VERSION 5.8 ;
BUSBITCHARS "[]" ;
DIVIDERCHAR "/" ;
UNITS
    DATABASE MICRONS 1000 ;
END UNITS

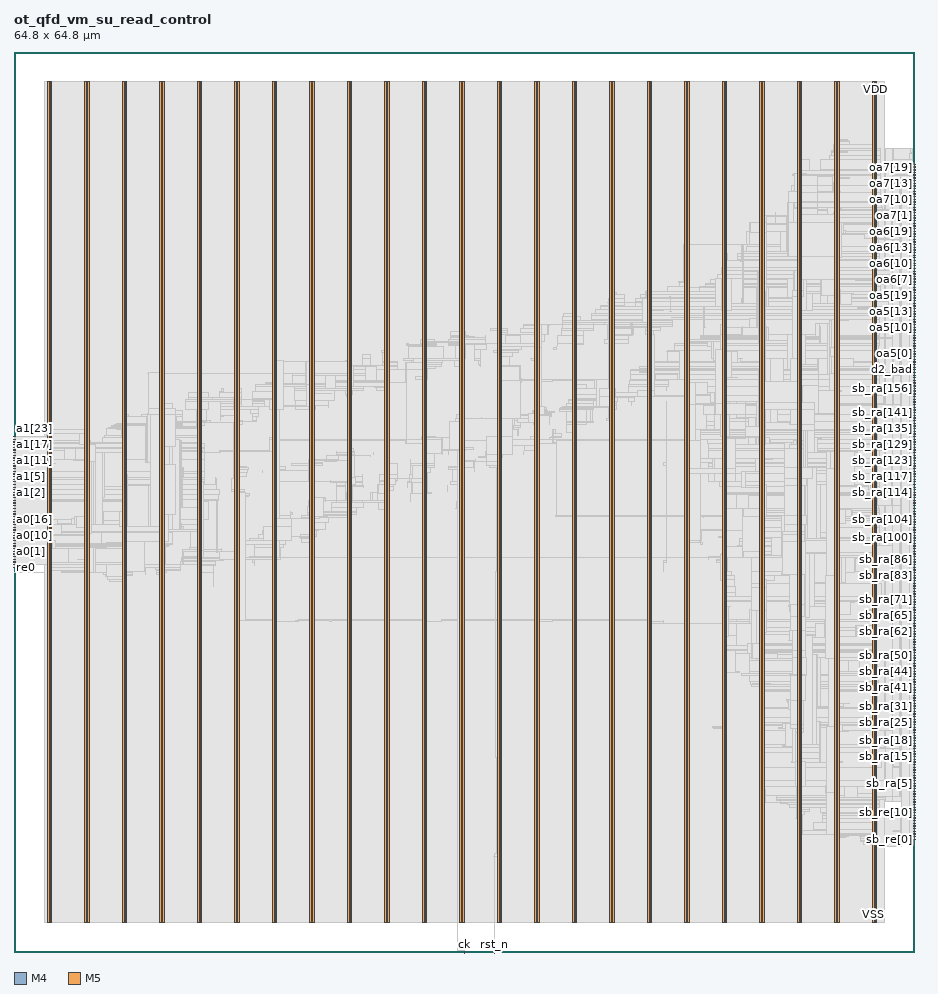
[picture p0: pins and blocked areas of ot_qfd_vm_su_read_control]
MACRO ot_qfd_vm_su_read_control
  FOREIGN ot_qfd_vm_su_read_control 0 0 ;
  CLASS BLOCK ;
  SIZE 64.8 BY 64.8 ;
  PIN a0[0]
    DIRECTION INPUT ;
    USE SIGNAL ;
    PORT
      LAYER M4 ;
        RECT  -0.072 28.08 0.072 28.104 ;
    END
  END a0[0]
  PIN a0[10]
    DIRECTION INPUT ;
    USE SIGNAL ;
    PORT
      LAYER M4 ;
        RECT  -0.072 30 0.072 30.024 ;
    END
  END a0[10]
  PIN a0[11]
    DIRECTION INPUT ;
    USE SIGNAL ;
    PORT
      LAYER M4 ;
        RECT  -0.072 30.192 0.072 30.216 ;
    END
  END a0[11]
  PIN a0[12]
    DIRECTION INPUT ;
    USE SIGNAL ;
    PORT
      LAYER M4 ;
        RECT  -0.072 30.384 0.072 30.408 ;
    END
  END a0[12]
  PIN a0[13]
    DIRECTION INPUT ;
    USE SIGNAL ;
    PORT
      LAYER M4 ;
        RECT  -0.072 30.576 0.072 30.6 ;
    END
  END a0[13]
  PIN a0[14]
    DIRECTION INPUT ;
    USE SIGNAL ;
    PORT
      LAYER M4 ;
        RECT  -0.072 30.768 0.072 30.792 ;
    END
  END a0[14]
  PIN a0[15]
    DIRECTION INPUT ;
    USE SIGNAL ;
    PORT
      LAYER M4 ;
        RECT  -0.072 30.96 0.072 30.984 ;
    END
  END a0[15]
  PIN a0[16]
    DIRECTION INPUT ;
    USE SIGNAL ;
    PORT
      LAYER M4 ;
        RECT  -0.072 31.152 0.072 31.176 ;
    END
  END a0[16]
  PIN a0[17]
    DIRECTION INPUT ;
    USE SIGNAL ;
    PORT
      LAYER M4 ;
        RECT  -0.072 31.344 0.072 31.368 ;
    END
  END a0[17]
  PIN a0[18]
    DIRECTION INPUT ;
    USE SIGNAL ;
    PORT
      LAYER M4 ;
        RECT  -0.072 31.536 0.072 31.56 ;
    END
  END a0[18]
  PIN a0[19]
    DIRECTION INPUT ;
    USE SIGNAL ;
    PORT
      LAYER M4 ;
        RECT  -0.072 31.728 0.072 31.752 ;
    END
  END a0[19]
  PIN a0[1]
    DIRECTION INPUT ;
    USE SIGNAL ;
    PORT
      LAYER M4 ;
        RECT  -0.072 28.272 0.072 28.296 ;
    END
  END a0[1]
  PIN a0[20]
    DIRECTION INPUT ;
    USE SIGNAL ;
    PORT
      LAYER M4 ;
        RECT  -0.072 31.92 0.072 31.944 ;
    END
  END a0[20]
  PIN a0[21]
    DIRECTION INPUT ;
    USE SIGNAL ;
    PORT
      LAYER M4 ;
        RECT  -0.072 32.112 0.072 32.136 ;
    END
  END a0[21]
  PIN a0[22]
    DIRECTION INPUT ;
    USE SIGNAL ;
    PORT
      LAYER M4 ;
        RECT  -0.072 32.304 0.072 32.328 ;
    END
  END a0[22]
  PIN a0[23]
    DIRECTION INPUT ;
    USE SIGNAL ;
    PORT
      LAYER M4 ;
        RECT  -0.072 32.496 0.072 32.52 ;
    END
  END a0[23]
  PIN a0[2]
    DIRECTION INPUT ;
    USE SIGNAL ;
    PORT
      LAYER M4 ;
        RECT  -0.072 28.464 0.072 28.488 ;
    END
  END a0[2]
  PIN a0[3]
    DIRECTION INPUT ;
    USE SIGNAL ;
    PORT
      LAYER M4 ;
        RECT  -0.072 28.656 0.072 28.68 ;
    END
  END a0[3]
  PIN a0[4]
    DIRECTION INPUT ;
    USE SIGNAL ;
    PORT
      LAYER M4 ;
        RECT  -0.072 28.848 0.072 28.872 ;
    END
  END a0[4]
  PIN a0[5]
    DIRECTION INPUT ;
    USE SIGNAL ;
    PORT
      LAYER M4 ;
        RECT  -0.072 29.04 0.072 29.064 ;
    END
  END a0[5]
  PIN a0[6]
    DIRECTION INPUT ;
    USE SIGNAL ;
    PORT
      LAYER M4 ;
        RECT  -0.072 29.232 0.072 29.256 ;
    END
  END a0[6]
  PIN a0[7]
    DIRECTION INPUT ;
    USE SIGNAL ;
    PORT
      LAYER M4 ;
        RECT  -0.072 29.424 0.072 29.448 ;
    END
  END a0[7]
  PIN a0[8]
    DIRECTION INPUT ;
    USE SIGNAL ;
    PORT
      LAYER M4 ;
        RECT  -0.072 29.616 0.072 29.64 ;
    END
  END a0[8]
  PIN a0[9]
    DIRECTION INPUT ;
    USE SIGNAL ;
    PORT
      LAYER M4 ;
        RECT  -0.072 29.808 0.072 29.832 ;
    END
  END a0[9]
  PIN a1[0]
    DIRECTION INPUT ;
    USE SIGNAL ;
    PORT
      LAYER M4 ;
        RECT  -0.072 32.688 0.072 32.712 ;
    END
  END a1[0]
  PIN a1[10]
    DIRECTION INPUT ;
    USE SIGNAL ;
    PORT
      LAYER M4 ;
        RECT  -0.072 34.608 0.072 34.632 ;
    END
  END a1[10]
  PIN a1[11]
    DIRECTION INPUT ;
    USE SIGNAL ;
    PORT
      LAYER M4 ;
        RECT  -0.072 34.8 0.072 34.824 ;
    END
  END a1[11]
  PIN a1[12]
    DIRECTION INPUT ;
    USE SIGNAL ;
    PORT
      LAYER M4 ;
        RECT  -0.072 34.992 0.072 35.016 ;
    END
  END a1[12]
  PIN a1[13]
    DIRECTION INPUT ;
    USE SIGNAL ;
    PORT
      LAYER M4 ;
        RECT  -0.072 35.184 0.072 35.208 ;
    END
  END a1[13]
  PIN a1[14]
    DIRECTION INPUT ;
    USE SIGNAL ;
    PORT
      LAYER M4 ;
        RECT  -0.072 35.376 0.072 35.4 ;
    END
  END a1[14]
  PIN a1[15]
    DIRECTION INPUT ;
    USE SIGNAL ;
    PORT
      LAYER M4 ;
        RECT  -0.072 35.568 0.072 35.592 ;
    END
  END a1[15]
  PIN a1[16]
    DIRECTION INPUT ;
    USE SIGNAL ;
    PORT
      LAYER M4 ;
        RECT  -0.072 35.76 0.072 35.784 ;
    END
  END a1[16]
  PIN a1[17]
    DIRECTION INPUT ;
    USE SIGNAL ;
    PORT
      LAYER M4 ;
        RECT  -0.072 35.952 0.072 35.976 ;
    END
  END a1[17]
  PIN a1[18]
    DIRECTION INPUT ;
    USE SIGNAL ;
    PORT
      LAYER M4 ;
        RECT  -0.072 36.144 0.072 36.168 ;
    END
  END a1[18]
  PIN a1[19]
    DIRECTION INPUT ;
    USE SIGNAL ;
    PORT
      LAYER M4 ;
        RECT  -0.072 36.336 0.072 36.36 ;
    END
  END a1[19]
  PIN a1[1]
    DIRECTION INPUT ;
    USE SIGNAL ;
    PORT
      LAYER M4 ;
        RECT  -0.072 32.88 0.072 32.904 ;
    END
  END a1[1]
  PIN a1[20]
    DIRECTION INPUT ;
    USE SIGNAL ;
    PORT
      LAYER M4 ;
        RECT  -0.072 36.528 0.072 36.552 ;
    END
  END a1[20]
  PIN a1[21]
    DIRECTION INPUT ;
    USE SIGNAL ;
    PORT
      LAYER M4 ;
        RECT  -0.072 36.72 0.072 36.744 ;
    END
  END a1[21]
  PIN a1[22]
    DIRECTION INPUT ;
    USE SIGNAL ;
    PORT
      LAYER M4 ;
        RECT  -0.072 36.912 0.072 36.936 ;
    END
  END a1[22]
  PIN a1[23]
    DIRECTION INPUT ;
    USE SIGNAL ;
    PORT
      LAYER M4 ;
        RECT  -0.072 37.104 0.072 37.128 ;
    END
  END a1[23]
  PIN a1[2]
    DIRECTION INPUT ;
    USE SIGNAL ;
    PORT
      LAYER M4 ;
        RECT  -0.072 33.072 0.072 33.096 ;
    END
  END a1[2]
  PIN a1[3]
    DIRECTION INPUT ;
    USE SIGNAL ;
    PORT
      LAYER M4 ;
        RECT  -0.072 33.264 0.072 33.288 ;
    END
  END a1[3]
  PIN a1[4]
    DIRECTION INPUT ;
    USE SIGNAL ;
    PORT
      LAYER M4 ;
        RECT  -0.072 33.456 0.072 33.48 ;
    END
  END a1[4]
  PIN a1[5]
    DIRECTION INPUT ;
    USE SIGNAL ;
    PORT
      LAYER M4 ;
        RECT  -0.072 33.648 0.072 33.672 ;
    END
  END a1[5]
  PIN a1[6]
    DIRECTION INPUT ;
    USE SIGNAL ;
    PORT
      LAYER M4 ;
        RECT  -0.072 33.84 0.072 33.864 ;
    END
  END a1[6]
  PIN a1[7]
    DIRECTION INPUT ;
    USE SIGNAL ;
    PORT
      LAYER M4 ;
        RECT  -0.072 34.032 0.072 34.056 ;
    END
  END a1[7]
  PIN a1[8]
    DIRECTION INPUT ;
    USE SIGNAL ;
    PORT
      LAYER M4 ;
        RECT  -0.072 34.224 0.072 34.248 ;
    END
  END a1[8]
  PIN a1[9]
    DIRECTION INPUT ;
    USE SIGNAL ;
    PORT
      LAYER M4 ;
        RECT  -0.072 34.416 0.072 34.44 ;
    END
  END a1[9]
  PIN ck
    DIRECTION INPUT ;
    USE SIGNAL ;
    PORT
      LAYER M5 ;
        RECT  32.4 -0.072 32.424 0.072 ;
    END
  END ck
  PIN d2_bad
    DIRECTION OUTPUT ;
    USE SIGNAL ;
    PORT
      LAYER M4 ;
        RECT  64.728 41.904 64.872 41.928 ;
    END
  END d2_bad
  PIN oa5[0]
    DIRECTION OUTPUT ;
    USE SIGNAL ;
    PORT
      LAYER M4 ;
        RECT  64.728 43.056 64.872 43.08 ;
    END
  END oa5[0]
  PIN oa5[10]
    DIRECTION OUTPUT ;
    USE SIGNAL ;
    PORT
      LAYER M4 ;
        RECT  64.728 44.976 64.872 45 ;
    END
  END oa5[10]
  PIN oa5[11]
    DIRECTION OUTPUT ;
    USE SIGNAL ;
    PORT
      LAYER M4 ;
        RECT  64.728 45.168 64.872 45.192 ;
    END
  END oa5[11]
  PIN oa5[12]
    DIRECTION OUTPUT ;
    USE SIGNAL ;
    PORT
      LAYER M4 ;
        RECT  64.728 45.36 64.872 45.384 ;
    END
  END oa5[12]
  PIN oa5[13]
    DIRECTION OUTPUT ;
    USE SIGNAL ;
    PORT
      LAYER M4 ;
        RECT  64.728 45.552 64.872 45.576 ;
    END
  END oa5[13]
  PIN oa5[14]
    DIRECTION OUTPUT ;
    USE SIGNAL ;
    PORT
      LAYER M4 ;
        RECT  64.728 45.744 64.872 45.768 ;
    END
  END oa5[14]
  PIN oa5[15]
    DIRECTION OUTPUT ;
    USE SIGNAL ;
    PORT
      LAYER M4 ;
        RECT  64.728 45.936 64.872 45.96 ;
    END
  END oa5[15]
  PIN oa5[16]
    DIRECTION OUTPUT ;
    USE SIGNAL ;
    PORT
      LAYER M4 ;
        RECT  64.728 46.128 64.872 46.152 ;
    END
  END oa5[16]
  PIN oa5[17]
    DIRECTION OUTPUT ;
    USE SIGNAL ;
    PORT
      LAYER M4 ;
        RECT  64.728 46.32 64.872 46.344 ;
    END
  END oa5[17]
  PIN oa5[18]
    DIRECTION OUTPUT ;
    USE SIGNAL ;
    PORT
      LAYER M4 ;
        RECT  64.728 46.512 64.872 46.536 ;
    END
  END oa5[18]
  PIN oa5[19]
    DIRECTION OUTPUT ;
    USE SIGNAL ;
    PORT
      LAYER M4 ;
        RECT  64.728 46.704 64.872 46.728 ;
    END
  END oa5[19]
  PIN oa5[1]
    DIRECTION OUTPUT ;
    USE SIGNAL ;
    PORT
      LAYER M4 ;
        RECT  64.728 43.248 64.872 43.272 ;
    END
  END oa5[1]
  PIN oa5[20]
    DIRECTION OUTPUT ;
    USE SIGNAL ;
    PORT
      LAYER M4 ;
        RECT  64.728 46.896 64.872 46.92 ;
    END
  END oa5[20]
  PIN oa5[21]
    DIRECTION OUTPUT ;
    USE SIGNAL ;
    PORT
      LAYER M4 ;
        RECT  64.728 47.088 64.872 47.112 ;
    END
  END oa5[21]
  PIN oa5[22]
    DIRECTION OUTPUT ;
    USE SIGNAL ;
    PORT
      LAYER M4 ;
        RECT  64.728 47.28 64.872 47.304 ;
    END
  END oa5[22]
  PIN oa5[23]
    DIRECTION OUTPUT ;
    USE SIGNAL ;
    PORT
      LAYER M4 ;
        RECT  64.728 47.472 64.872 47.496 ;
    END
  END oa5[23]
  PIN oa5[2]
    DIRECTION OUTPUT ;
    USE SIGNAL ;
    PORT
      LAYER M4 ;
        RECT  64.728 43.44 64.872 43.464 ;
    END
  END oa5[2]
  PIN oa5[3]
    DIRECTION OUTPUT ;
    USE SIGNAL ;
    PORT
      LAYER M4 ;
        RECT  64.728 43.632 64.872 43.656 ;
    END
  END oa5[3]
  PIN oa5[4]
    DIRECTION OUTPUT ;
    USE SIGNAL ;
    PORT
      LAYER M4 ;
        RECT  64.728 43.824 64.872 43.848 ;
    END
  END oa5[4]
  PIN oa5[5]
    DIRECTION OUTPUT ;
    USE SIGNAL ;
    PORT
      LAYER M4 ;
        RECT  64.728 44.016 64.872 44.04 ;
    END
  END oa5[5]
  PIN oa5[6]
    DIRECTION OUTPUT ;
    USE SIGNAL ;
    PORT
      LAYER M4 ;
        RECT  64.728 44.208 64.872 44.232 ;
    END
  END oa5[6]
  PIN oa5[7]
    DIRECTION OUTPUT ;
    USE SIGNAL ;
    PORT
      LAYER M4 ;
        RECT  64.728 44.4 64.872 44.424 ;
    END
  END oa5[7]
  PIN oa5[8]
    DIRECTION OUTPUT ;
    USE SIGNAL ;
    PORT
      LAYER M4 ;
        RECT  64.728 44.592 64.872 44.616 ;
    END
  END oa5[8]
  PIN oa5[9]
    DIRECTION OUTPUT ;
    USE SIGNAL ;
    PORT
      LAYER M4 ;
        RECT  64.728 44.784 64.872 44.808 ;
    END
  END oa5[9]
  PIN oa6[0]
    DIRECTION OUTPUT ;
    USE SIGNAL ;
    PORT
      LAYER M4 ;
        RECT  64.728 47.664 64.872 47.688 ;
    END
  END oa6[0]
  PIN oa6[10]
    DIRECTION OUTPUT ;
    USE SIGNAL ;
    PORT
      LAYER M4 ;
        RECT  64.728 49.584 64.872 49.608 ;
    END
  END oa6[10]
  PIN oa6[11]
    DIRECTION OUTPUT ;
    USE SIGNAL ;
    PORT
      LAYER M4 ;
        RECT  64.728 49.776 64.872 49.8 ;
    END
  END oa6[11]
  PIN oa6[12]
    DIRECTION OUTPUT ;
    USE SIGNAL ;
    PORT
      LAYER M4 ;
        RECT  64.728 49.968 64.872 49.992 ;
    END
  END oa6[12]
  PIN oa6[13]
    DIRECTION OUTPUT ;
    USE SIGNAL ;
    PORT
      LAYER M4 ;
        RECT  64.728 50.16 64.872 50.184 ;
    END
  END oa6[13]
  PIN oa6[14]
    DIRECTION OUTPUT ;
    USE SIGNAL ;
    PORT
      LAYER M4 ;
        RECT  64.728 50.352 64.872 50.376 ;
    END
  END oa6[14]
  PIN oa6[15]
    DIRECTION OUTPUT ;
    USE SIGNAL ;
    PORT
      LAYER M4 ;
        RECT  64.728 50.544 64.872 50.568 ;
    END
  END oa6[15]
  PIN oa6[16]
    DIRECTION OUTPUT ;
    USE SIGNAL ;
    PORT
      LAYER M4 ;
        RECT  64.728 50.736 64.872 50.76 ;
    END
  END oa6[16]
  PIN oa6[17]
    DIRECTION OUTPUT ;
    USE SIGNAL ;
    PORT
      LAYER M4 ;
        RECT  64.728 50.928 64.872 50.952 ;
    END
  END oa6[17]
  PIN oa6[18]
    DIRECTION OUTPUT ;
    USE SIGNAL ;
    PORT
      LAYER M4 ;
        RECT  64.728 51.12 64.872 51.144 ;
    END
  END oa6[18]
  PIN oa6[19]
    DIRECTION OUTPUT ;
    USE SIGNAL ;
    PORT
      LAYER M4 ;
        RECT  64.728 51.312 64.872 51.336 ;
    END
  END oa6[19]
  PIN oa6[1]
    DIRECTION OUTPUT ;
    USE SIGNAL ;
    PORT
      LAYER M4 ;
        RECT  64.728 47.856 64.872 47.88 ;
    END
  END oa6[1]
  PIN oa6[20]
    DIRECTION OUTPUT ;
    USE SIGNAL ;
    PORT
      LAYER M4 ;
        RECT  64.728 51.504 64.872 51.528 ;
    END
  END oa6[20]
  PIN oa6[21]
    DIRECTION OUTPUT ;
    USE SIGNAL ;
    PORT
      LAYER M4 ;
        RECT  64.728 51.696 64.872 51.72 ;
    END
  END oa6[21]
  PIN oa6[22]
    DIRECTION OUTPUT ;
    USE SIGNAL ;
    PORT
      LAYER M4 ;
        RECT  64.728 51.888 64.872 51.912 ;
    END
  END oa6[22]
  PIN oa6[23]
    DIRECTION OUTPUT ;
    USE SIGNAL ;
    PORT
      LAYER M4 ;
        RECT  64.728 52.08 64.872 52.104 ;
    END
  END oa6[23]
  PIN oa6[2]
    DIRECTION OUTPUT ;
    USE SIGNAL ;
    PORT
      LAYER M4 ;
        RECT  64.728 48.048 64.872 48.072 ;
    END
  END oa6[2]
  PIN oa6[3]
    DIRECTION OUTPUT ;
    USE SIGNAL ;
    PORT
      LAYER M4 ;
        RECT  64.728 48.24 64.872 48.264 ;
    END
  END oa6[3]
  PIN oa6[4]
    DIRECTION OUTPUT ;
    USE SIGNAL ;
    PORT
      LAYER M4 ;
        RECT  64.728 48.432 64.872 48.456 ;
    END
  END oa6[4]
  PIN oa6[5]
    DIRECTION OUTPUT ;
    USE SIGNAL ;
    PORT
      LAYER M4 ;
        RECT  64.728 48.624 64.872 48.648 ;
    END
  END oa6[5]
  PIN oa6[6]
    DIRECTION OUTPUT ;
    USE SIGNAL ;
    PORT
      LAYER M4 ;
        RECT  64.728 48.816 64.872 48.84 ;
    END
  END oa6[6]
  PIN oa6[7]
    DIRECTION OUTPUT ;
    USE SIGNAL ;
    PORT
      LAYER M4 ;
        RECT  64.728 49.008 64.872 49.032 ;
    END
  END oa6[7]
  PIN oa6[8]
    DIRECTION OUTPUT ;
    USE SIGNAL ;
    PORT
      LAYER M4 ;
        RECT  64.728 49.2 64.872 49.224 ;
    END
  END oa6[8]
  PIN oa6[9]
    DIRECTION OUTPUT ;
    USE SIGNAL ;
    PORT
      LAYER M4 ;
        RECT  64.728 49.392 64.872 49.416 ;
    END
  END oa6[9]
  PIN oa7[0]
    DIRECTION OUTPUT ;
    USE SIGNAL ;
    PORT
      LAYER M4 ;
        RECT  64.728 52.272 64.872 52.296 ;
    END
  END oa7[0]
  PIN oa7[10]
    DIRECTION OUTPUT ;
    USE SIGNAL ;
    PORT
      LAYER M4 ;
        RECT  64.728 54.192 64.872 54.216 ;
    END
  END oa7[10]
  PIN oa7[11]
    DIRECTION OUTPUT ;
    USE SIGNAL ;
    PORT
      LAYER M4 ;
        RECT  64.728 54.384 64.872 54.408 ;
    END
  END oa7[11]
  PIN oa7[12]
    DIRECTION OUTPUT ;
    USE SIGNAL ;
    PORT
      LAYER M4 ;
        RECT  64.728 54.576 64.872 54.6 ;
    END
  END oa7[12]
  PIN oa7[13]
    DIRECTION OUTPUT ;
    USE SIGNAL ;
    PORT
      LAYER M4 ;
        RECT  64.728 54.768 64.872 54.792 ;
    END
  END oa7[13]
  PIN oa7[14]
    DIRECTION OUTPUT ;
    USE SIGNAL ;
    PORT
      LAYER M4 ;
        RECT  64.728 54.96 64.872 54.984 ;
    END
  END oa7[14]
  PIN oa7[15]
    DIRECTION OUTPUT ;
    USE SIGNAL ;
    PORT
      LAYER M4 ;
        RECT  64.728 55.152 64.872 55.176 ;
    END
  END oa7[15]
  PIN oa7[16]
    DIRECTION OUTPUT ;
    USE SIGNAL ;
    PORT
      LAYER M4 ;
        RECT  64.728 55.344 64.872 55.368 ;
    END
  END oa7[16]
  PIN oa7[17]
    DIRECTION OUTPUT ;
    USE SIGNAL ;
    PORT
      LAYER M4 ;
        RECT  64.728 55.536 64.872 55.56 ;
    END
  END oa7[17]
  PIN oa7[18]
    DIRECTION OUTPUT ;
    USE SIGNAL ;
    PORT
      LAYER M4 ;
        RECT  64.728 55.728 64.872 55.752 ;
    END
  END oa7[18]
  PIN oa7[19]
    DIRECTION OUTPUT ;
    USE SIGNAL ;
    PORT
      LAYER M4 ;
        RECT  64.728 55.92 64.872 55.944 ;
    END
  END oa7[19]
  PIN oa7[1]
    DIRECTION OUTPUT ;
    USE SIGNAL ;
    PORT
      LAYER M4 ;
        RECT  64.728 52.464 64.872 52.488 ;
    END
  END oa7[1]
  PIN oa7[20]
    DIRECTION OUTPUT ;
    USE SIGNAL ;
    PORT
      LAYER M4 ;
        RECT  64.728 56.112 64.872 56.136 ;
    END
  END oa7[20]
  PIN oa7[21]
    DIRECTION OUTPUT ;
    USE SIGNAL ;
    PORT
      LAYER M4 ;
        RECT  64.728 56.304 64.872 56.328 ;
    END
  END oa7[21]
  PIN oa7[22]
    DIRECTION OUTPUT ;
    USE SIGNAL ;
    PORT
      LAYER M4 ;
        RECT  64.728 56.496 64.872 56.52 ;
    END
  END oa7[22]
  PIN oa7[23]
    DIRECTION OUTPUT ;
    USE SIGNAL ;
    PORT
      LAYER M4 ;
        RECT  64.728 56.688 64.872 56.712 ;
    END
  END oa7[23]
  PIN oa7[2]
    DIRECTION OUTPUT ;
    USE SIGNAL ;
    PORT
      LAYER M4 ;
        RECT  64.728 52.656 64.872 52.68 ;
    END
  END oa7[2]
  PIN oa7[3]
    DIRECTION OUTPUT ;
    USE SIGNAL ;
    PORT
      LAYER M4 ;
        RECT  64.728 52.848 64.872 52.872 ;
    END
  END oa7[3]
  PIN oa7[4]
    DIRECTION OUTPUT ;
    USE SIGNAL ;
    PORT
      LAYER M4 ;
        RECT  64.728 53.04 64.872 53.064 ;
    END
  END oa7[4]
  PIN oa7[5]
    DIRECTION OUTPUT ;
    USE SIGNAL ;
    PORT
      LAYER M4 ;
        RECT  64.728 53.232 64.872 53.256 ;
    END
  END oa7[5]
  PIN oa7[6]
    DIRECTION OUTPUT ;
    USE SIGNAL ;
    PORT
      LAYER M4 ;
        RECT  64.728 53.424 64.872 53.448 ;
    END
  END oa7[6]
  PIN oa7[7]
    DIRECTION OUTPUT ;
    USE SIGNAL ;
    PORT
      LAYER M4 ;
        RECT  64.728 53.616 64.872 53.64 ;
    END
  END oa7[7]
  PIN oa7[8]
    DIRECTION OUTPUT ;
    USE SIGNAL ;
    PORT
      LAYER M4 ;
        RECT  64.728 53.808 64.872 53.832 ;
    END
  END oa7[8]
  PIN oa7[9]
    DIRECTION OUTPUT ;
    USE SIGNAL ;
    PORT
      LAYER M4 ;
        RECT  64.728 54 64.872 54.024 ;
    END
  END oa7[9]
  PIN osi7
    DIRECTION OUTPUT ;
    USE SIGNAL ;
    PORT
      LAYER M4 ;
        RECT  64.728 42.864 64.872 42.888 ;
    END
  END osi7
  PIN ov3
    DIRECTION OUTPUT ;
    USE SIGNAL ;
    PORT
      LAYER M4 ;
        RECT  64.728 42.096 64.872 42.12 ;
    END
  END ov3
  PIN ov5
    DIRECTION OUTPUT ;
    USE SIGNAL ;
    PORT
      LAYER M4 ;
        RECT  64.728 42.288 64.872 42.312 ;
    END
  END ov5
  PIN ov6
    DIRECTION OUTPUT ;
    USE SIGNAL ;
    PORT
      LAYER M4 ;
        RECT  64.728 42.48 64.872 42.504 ;
    END
  END ov6
  PIN ov7
    DIRECTION OUTPUT ;
    USE SIGNAL ;
    PORT
      LAYER M4 ;
        RECT  64.728 42.672 64.872 42.696 ;
    END
  END ov7
  PIN re0
    DIRECTION INPUT ;
    USE SIGNAL ;
    PORT
      LAYER M4 ;
        RECT  -0.072 27.696 0.072 27.72 ;
    END
  END re0
  PIN re1
    DIRECTION INPUT ;
    USE SIGNAL ;
    PORT
      LAYER M4 ;
        RECT  -0.072 27.888 0.072 27.912 ;
    END
  END re1
  PIN rst_n
    DIRECTION INPUT ;
    USE SIGNAL ;
    PORT
      LAYER M5 ;
        RECT  34.56 -0.072 34.584 0.072 ;
    END
  END rst_n
  PIN sb_ra[0]
    DIRECTION OUTPUT ;
    USE SIGNAL ;
    PORT
      LAYER M4 ;
        RECT  64.728 11.184 64.872 11.208 ;
    END
  END sb_ra[0]
  PIN sb_ra[100]
    DIRECTION OUTPUT ;
    USE SIGNAL ;
    PORT
      LAYER M4 ;
        RECT  64.728 30.384 64.872 30.408 ;
    END
  END sb_ra[100]
  PIN sb_ra[101]
    DIRECTION OUTPUT ;
    USE SIGNAL ;
    PORT
      LAYER M4 ;
        RECT  64.728 30.576 64.872 30.6 ;
    END
  END sb_ra[101]
  PIN sb_ra[102]
    DIRECTION OUTPUT ;
    USE SIGNAL ;
    PORT
      LAYER M4 ;
        RECT  64.728 30.768 64.872 30.792 ;
    END
  END sb_ra[102]
  PIN sb_ra[103]
    DIRECTION OUTPUT ;
    USE SIGNAL ;
    PORT
      LAYER M4 ;
        RECT  64.728 30.96 64.872 30.984 ;
    END
  END sb_ra[103]
  PIN sb_ra[104]
    DIRECTION OUTPUT ;
    USE SIGNAL ;
    PORT
      LAYER M4 ;
        RECT  64.728 31.152 64.872 31.176 ;
    END
  END sb_ra[104]
  PIN sb_ra[105]
    DIRECTION OUTPUT ;
    USE SIGNAL ;
    PORT
      LAYER M4 ;
        RECT  64.728 31.344 64.872 31.368 ;
    END
  END sb_ra[105]
  PIN sb_ra[106]
    DIRECTION OUTPUT ;
    USE SIGNAL ;
    PORT
      LAYER M4 ;
        RECT  64.728 31.536 64.872 31.56 ;
    END
  END sb_ra[106]
  PIN sb_ra[107]
    DIRECTION OUTPUT ;
    USE SIGNAL ;
    PORT
      LAYER M4 ;
        RECT  64.728 31.728 64.872 31.752 ;
    END
  END sb_ra[107]
  PIN sb_ra[108]
    DIRECTION OUTPUT ;
    USE SIGNAL ;
    PORT
      LAYER M4 ;
        RECT  64.728 31.92 64.872 31.944 ;
    END
  END sb_ra[108]
  PIN sb_ra[109]
    DIRECTION OUTPUT ;
    USE SIGNAL ;
    PORT
      LAYER M4 ;
        RECT  64.728 32.112 64.872 32.136 ;
    END
  END sb_ra[109]
  PIN sb_ra[10]
    DIRECTION OUTPUT ;
    USE SIGNAL ;
    PORT
      LAYER M4 ;
        RECT  64.728 13.104 64.872 13.128 ;
    END
  END sb_ra[10]
  PIN sb_ra[110]
    DIRECTION OUTPUT ;
    USE SIGNAL ;
    PORT
      LAYER M4 ;
        RECT  64.728 32.304 64.872 32.328 ;
    END
  END sb_ra[110]
  PIN sb_ra[111]
    DIRECTION OUTPUT ;
    USE SIGNAL ;
    PORT
      LAYER M4 ;
        RECT  64.728 32.496 64.872 32.52 ;
    END
  END sb_ra[111]
  PIN sb_ra[112]
    DIRECTION OUTPUT ;
    USE SIGNAL ;
    PORT
      LAYER M4 ;
        RECT  64.728 32.688 64.872 32.712 ;
    END
  END sb_ra[112]
  PIN sb_ra[113]
    DIRECTION OUTPUT ;
    USE SIGNAL ;
    PORT
      LAYER M4 ;
        RECT  64.728 32.88 64.872 32.904 ;
    END
  END sb_ra[113]
  PIN sb_ra[114]
    DIRECTION OUTPUT ;
    USE SIGNAL ;
    PORT
      LAYER M4 ;
        RECT  64.728 33.072 64.872 33.096 ;
    END
  END sb_ra[114]
  PIN sb_ra[115]
    DIRECTION OUTPUT ;
    USE SIGNAL ;
    PORT
      LAYER M4 ;
        RECT  64.728 33.264 64.872 33.288 ;
    END
  END sb_ra[115]
  PIN sb_ra[116]
    DIRECTION OUTPUT ;
    USE SIGNAL ;
    PORT
      LAYER M4 ;
        RECT  64.728 33.456 64.872 33.48 ;
    END
  END sb_ra[116]
  PIN sb_ra[117]
    DIRECTION OUTPUT ;
    USE SIGNAL ;
    PORT
      LAYER M4 ;
        RECT  64.728 33.648 64.872 33.672 ;
    END
  END sb_ra[117]
  PIN sb_ra[118]
    DIRECTION OUTPUT ;
    USE SIGNAL ;
    PORT
      LAYER M4 ;
        RECT  64.728 33.84 64.872 33.864 ;
    END
  END sb_ra[118]
  PIN sb_ra[119]
    DIRECTION OUTPUT ;
    USE SIGNAL ;
    PORT
      LAYER M4 ;
        RECT  64.728 34.032 64.872 34.056 ;
    END
  END sb_ra[119]
  PIN sb_ra[11]
    DIRECTION OUTPUT ;
    USE SIGNAL ;
    PORT
      LAYER M4 ;
        RECT  64.728 13.296 64.872 13.32 ;
    END
  END sb_ra[11]
  PIN sb_ra[120]
    DIRECTION OUTPUT ;
    USE SIGNAL ;
    PORT
      LAYER M4 ;
        RECT  64.728 34.224 64.872 34.248 ;
    END
  END sb_ra[120]
  PIN sb_ra[121]
    DIRECTION OUTPUT ;
    USE SIGNAL ;
    PORT
      LAYER M4 ;
        RECT  64.728 34.416 64.872 34.44 ;
    END
  END sb_ra[121]
  PIN sb_ra[122]
    DIRECTION OUTPUT ;
    USE SIGNAL ;
    PORT
      LAYER M4 ;
        RECT  64.728 34.608 64.872 34.632 ;
    END
  END sb_ra[122]
  PIN sb_ra[123]
    DIRECTION OUTPUT ;
    USE SIGNAL ;
    PORT
      LAYER M4 ;
        RECT  64.728 34.8 64.872 34.824 ;
    END
  END sb_ra[123]
  PIN sb_ra[124]
    DIRECTION OUTPUT ;
    USE SIGNAL ;
    PORT
      LAYER M4 ;
        RECT  64.728 34.992 64.872 35.016 ;
    END
  END sb_ra[124]
  PIN sb_ra[125]
    DIRECTION OUTPUT ;
    USE SIGNAL ;
    PORT
      LAYER M4 ;
        RECT  64.728 35.184 64.872 35.208 ;
    END
  END sb_ra[125]
  PIN sb_ra[126]
    DIRECTION OUTPUT ;
    USE SIGNAL ;
    PORT
      LAYER M4 ;
        RECT  64.728 35.376 64.872 35.4 ;
    END
  END sb_ra[126]
  PIN sb_ra[127]
    DIRECTION OUTPUT ;
    USE SIGNAL ;
    PORT
      LAYER M4 ;
        RECT  64.728 35.568 64.872 35.592 ;
    END
  END sb_ra[127]
  PIN sb_ra[128]
    DIRECTION OUTPUT ;
    USE SIGNAL ;
    PORT
      LAYER M4 ;
        RECT  64.728 35.76 64.872 35.784 ;
    END
  END sb_ra[128]
  PIN sb_ra[129]
    DIRECTION OUTPUT ;
    USE SIGNAL ;
    PORT
      LAYER M4 ;
        RECT  64.728 35.952 64.872 35.976 ;
    END
  END sb_ra[129]
  PIN sb_ra[12]
    DIRECTION OUTPUT ;
    USE SIGNAL ;
    PORT
      LAYER M4 ;
        RECT  64.728 13.488 64.872 13.512 ;
    END
  END sb_ra[12]
  PIN sb_ra[130]
    DIRECTION OUTPUT ;
    USE SIGNAL ;
    PORT
      LAYER M4 ;
        RECT  64.728 36.144 64.872 36.168 ;
    END
  END sb_ra[130]
  PIN sb_ra[131]
    DIRECTION OUTPUT ;
    USE SIGNAL ;
    PORT
      LAYER M4 ;
        RECT  64.728 36.336 64.872 36.36 ;
    END
  END sb_ra[131]
  PIN sb_ra[132]
    DIRECTION OUTPUT ;
    USE SIGNAL ;
    PORT
      LAYER M4 ;
        RECT  64.728 36.528 64.872 36.552 ;
    END
  END sb_ra[132]
  PIN sb_ra[133]
    DIRECTION OUTPUT ;
    USE SIGNAL ;
    PORT
      LAYER M4 ;
        RECT  64.728 36.72 64.872 36.744 ;
    END
  END sb_ra[133]
  PIN sb_ra[134]
    DIRECTION OUTPUT ;
    USE SIGNAL ;
    PORT
      LAYER M4 ;
        RECT  64.728 36.912 64.872 36.936 ;
    END
  END sb_ra[134]
  PIN sb_ra[135]
    DIRECTION OUTPUT ;
    USE SIGNAL ;
    PORT
      LAYER M4 ;
        RECT  64.728 37.104 64.872 37.128 ;
    END
  END sb_ra[135]
  PIN sb_ra[136]
    DIRECTION OUTPUT ;
    USE SIGNAL ;
    PORT
      LAYER M4 ;
        RECT  64.728 37.296 64.872 37.32 ;
    END
  END sb_ra[136]
  PIN sb_ra[137]
    DIRECTION OUTPUT ;
    USE SIGNAL ;
    PORT
      LAYER M4 ;
        RECT  64.728 37.488 64.872 37.512 ;
    END
  END sb_ra[137]
  PIN sb_ra[138]
    DIRECTION OUTPUT ;
    USE SIGNAL ;
    PORT
      LAYER M4 ;
        RECT  64.728 37.68 64.872 37.704 ;
    END
  END sb_ra[138]
  PIN sb_ra[139]
    DIRECTION OUTPUT ;
    USE SIGNAL ;
    PORT
      LAYER M4 ;
        RECT  64.728 37.872 64.872 37.896 ;
    END
  END sb_ra[139]
  PIN sb_ra[13]
    DIRECTION OUTPUT ;
    USE SIGNAL ;
    PORT
      LAYER M4 ;
        RECT  64.728 13.68 64.872 13.704 ;
    END
  END sb_ra[13]
  PIN sb_ra[140]
    DIRECTION OUTPUT ;
    USE SIGNAL ;
    PORT
      LAYER M4 ;
        RECT  64.728 38.064 64.872 38.088 ;
    END
  END sb_ra[140]
  PIN sb_ra[141]
    DIRECTION OUTPUT ;
    USE SIGNAL ;
    PORT
      LAYER M4 ;
        RECT  64.728 38.256 64.872 38.28 ;
    END
  END sb_ra[141]
  PIN sb_ra[142]
    DIRECTION OUTPUT ;
    USE SIGNAL ;
    PORT
      LAYER M4 ;
        RECT  64.728 38.448 64.872 38.472 ;
    END
  END sb_ra[142]
  PIN sb_ra[143]
    DIRECTION OUTPUT ;
    USE SIGNAL ;
    PORT
      LAYER M4 ;
        RECT  64.728 38.64 64.872 38.664 ;
    END
  END sb_ra[143]
  PIN sb_ra[144]
    DIRECTION OUTPUT ;
    USE SIGNAL ;
    PORT
      LAYER M4 ;
        RECT  64.728 38.832 64.872 38.856 ;
    END
  END sb_ra[144]
  PIN sb_ra[145]
    DIRECTION OUTPUT ;
    USE SIGNAL ;
    PORT
      LAYER M4 ;
        RECT  64.728 39.024 64.872 39.048 ;
    END
  END sb_ra[145]
  PIN sb_ra[146]
    DIRECTION OUTPUT ;
    USE SIGNAL ;
    PORT
      LAYER M4 ;
        RECT  64.728 39.216 64.872 39.24 ;
    END
  END sb_ra[146]
  PIN sb_ra[147]
    DIRECTION OUTPUT ;
    USE SIGNAL ;
    PORT
      LAYER M4 ;
        RECT  64.728 39.408 64.872 39.432 ;
    END
  END sb_ra[147]
  PIN sb_ra[148]
    DIRECTION OUTPUT ;
    USE SIGNAL ;
    PORT
      LAYER M4 ;
        RECT  64.728 39.6 64.872 39.624 ;
    END
  END sb_ra[148]
  PIN sb_ra[149]
    DIRECTION OUTPUT ;
    USE SIGNAL ;
    PORT
      LAYER M4 ;
        RECT  64.728 39.792 64.872 39.816 ;
    END
  END sb_ra[149]
  PIN sb_ra[14]
    DIRECTION OUTPUT ;
    USE SIGNAL ;
    PORT
      LAYER M4 ;
        RECT  64.728 13.872 64.872 13.896 ;
    END
  END sb_ra[14]
  PIN sb_ra[150]
    DIRECTION OUTPUT ;
    USE SIGNAL ;
    PORT
      LAYER M4 ;
        RECT  64.728 39.984 64.872 40.008 ;
    END
  END sb_ra[150]
  PIN sb_ra[151]
    DIRECTION OUTPUT ;
    USE SIGNAL ;
    PORT
      LAYER M4 ;
        RECT  64.728 40.176 64.872 40.2 ;
    END
  END sb_ra[151]
  PIN sb_ra[152]
    DIRECTION OUTPUT ;
    USE SIGNAL ;
    PORT
      LAYER M4 ;
        RECT  64.728 40.368 64.872 40.392 ;
    END
  END sb_ra[152]
  PIN sb_ra[153]
    DIRECTION OUTPUT ;
    USE SIGNAL ;
    PORT
      LAYER M4 ;
        RECT  64.728 40.56 64.872 40.584 ;
    END
  END sb_ra[153]
  PIN sb_ra[154]
    DIRECTION OUTPUT ;
    USE SIGNAL ;
    PORT
      LAYER M4 ;
        RECT  64.728 40.752 64.872 40.776 ;
    END
  END sb_ra[154]
  PIN sb_ra[155]
    DIRECTION OUTPUT ;
    USE SIGNAL ;
    PORT
      LAYER M4 ;
        RECT  64.728 40.944 64.872 40.968 ;
    END
  END sb_ra[155]
  PIN sb_ra[156]
    DIRECTION OUTPUT ;
    USE SIGNAL ;
    PORT
      LAYER M4 ;
        RECT  64.728 41.136 64.872 41.16 ;
    END
  END sb_ra[156]
  PIN sb_ra[157]
    DIRECTION OUTPUT ;
    USE SIGNAL ;
    PORT
      LAYER M4 ;
        RECT  64.728 41.328 64.872 41.352 ;
    END
  END sb_ra[157]
  PIN sb_ra[158]
    DIRECTION OUTPUT ;
    USE SIGNAL ;
    PORT
      LAYER M4 ;
        RECT  64.728 41.52 64.872 41.544 ;
    END
  END sb_ra[158]
  PIN sb_ra[159]
    DIRECTION OUTPUT ;
    USE SIGNAL ;
    PORT
      LAYER M4 ;
        RECT  64.728 41.712 64.872 41.736 ;
    END
  END sb_ra[159]
  PIN sb_ra[15]
    DIRECTION OUTPUT ;
    USE SIGNAL ;
    PORT
      LAYER M4 ;
        RECT  64.728 14.064 64.872 14.088 ;
    END
  END sb_ra[15]
  PIN sb_ra[16]
    DIRECTION OUTPUT ;
    USE SIGNAL ;
    PORT
      LAYER M4 ;
        RECT  64.728 14.256 64.872 14.28 ;
    END
  END sb_ra[16]
  PIN sb_ra[17]
    DIRECTION OUTPUT ;
    USE SIGNAL ;
    PORT
      LAYER M4 ;
        RECT  64.728 14.448 64.872 14.472 ;
    END
  END sb_ra[17]
  PIN sb_ra[18]
    DIRECTION OUTPUT ;
    USE SIGNAL ;
    PORT
      LAYER M4 ;
        RECT  64.728 14.64 64.872 14.664 ;
    END
  END sb_ra[18]
  PIN sb_ra[19]
    DIRECTION OUTPUT ;
    USE SIGNAL ;
    PORT
      LAYER M4 ;
        RECT  64.728 14.832 64.872 14.856 ;
    END
  END sb_ra[19]
  PIN sb_ra[1]
    DIRECTION OUTPUT ;
    USE SIGNAL ;
    PORT
      LAYER M4 ;
        RECT  64.728 11.376 64.872 11.4 ;
    END
  END sb_ra[1]
  PIN sb_ra[20]
    DIRECTION OUTPUT ;
    USE SIGNAL ;
    PORT
      LAYER M4 ;
        RECT  64.728 15.024 64.872 15.048 ;
    END
  END sb_ra[20]
  PIN sb_ra[21]
    DIRECTION OUTPUT ;
    USE SIGNAL ;
    PORT
      LAYER M4 ;
        RECT  64.728 15.216 64.872 15.24 ;
    END
  END sb_ra[21]
  PIN sb_ra[22]
    DIRECTION OUTPUT ;
    USE SIGNAL ;
    PORT
      LAYER M4 ;
        RECT  64.728 15.408 64.872 15.432 ;
    END
  END sb_ra[22]
  PIN sb_ra[23]
    DIRECTION OUTPUT ;
    USE SIGNAL ;
    PORT
      LAYER M4 ;
        RECT  64.728 15.6 64.872 15.624 ;
    END
  END sb_ra[23]
  PIN sb_ra[24]
    DIRECTION OUTPUT ;
    USE SIGNAL ;
    PORT
      LAYER M4 ;
        RECT  64.728 15.792 64.872 15.816 ;
    END
  END sb_ra[24]
  PIN sb_ra[25]
    DIRECTION OUTPUT ;
    USE SIGNAL ;
    PORT
      LAYER M4 ;
        RECT  64.728 15.984 64.872 16.008 ;
    END
  END sb_ra[25]
  PIN sb_ra[26]
    DIRECTION OUTPUT ;
    USE SIGNAL ;
    PORT
      LAYER M4 ;
        RECT  64.728 16.176 64.872 16.2 ;
    END
  END sb_ra[26]
  PIN sb_ra[27]
    DIRECTION OUTPUT ;
    USE SIGNAL ;
    PORT
      LAYER M4 ;
        RECT  64.728 16.368 64.872 16.392 ;
    END
  END sb_ra[27]
  PIN sb_ra[28]
    DIRECTION OUTPUT ;
    USE SIGNAL ;
    PORT
      LAYER M4 ;
        RECT  64.728 16.56 64.872 16.584 ;
    END
  END sb_ra[28]
  PIN sb_ra[29]
    DIRECTION OUTPUT ;
    USE SIGNAL ;
    PORT
      LAYER M4 ;
        RECT  64.728 16.752 64.872 16.776 ;
    END
  END sb_ra[29]
  PIN sb_ra[2]
    DIRECTION OUTPUT ;
    USE SIGNAL ;
    PORT
      LAYER M4 ;
        RECT  64.728 11.568 64.872 11.592 ;
    END
  END sb_ra[2]
  PIN sb_ra[30]
    DIRECTION OUTPUT ;
    USE SIGNAL ;
    PORT
      LAYER M4 ;
        RECT  64.728 16.944 64.872 16.968 ;
    END
  END sb_ra[30]
  PIN sb_ra[31]
    DIRECTION OUTPUT ;
    USE SIGNAL ;
    PORT
      LAYER M4 ;
        RECT  64.728 17.136 64.872 17.16 ;
    END
  END sb_ra[31]
  PIN sb_ra[32]
    DIRECTION OUTPUT ;
    USE SIGNAL ;
    PORT
      LAYER M4 ;
        RECT  64.728 17.328 64.872 17.352 ;
    END
  END sb_ra[32]
  PIN sb_ra[33]
    DIRECTION OUTPUT ;
    USE SIGNAL ;
    PORT
      LAYER M4 ;
        RECT  64.728 17.52 64.872 17.544 ;
    END
  END sb_ra[33]
  PIN sb_ra[34]
    DIRECTION OUTPUT ;
    USE SIGNAL ;
    PORT
      LAYER M4 ;
        RECT  64.728 17.712 64.872 17.736 ;
    END
  END sb_ra[34]
  PIN sb_ra[35]
    DIRECTION OUTPUT ;
    USE SIGNAL ;
    PORT
      LAYER M4 ;
        RECT  64.728 17.904 64.872 17.928 ;
    END
  END sb_ra[35]
  PIN sb_ra[36]
    DIRECTION OUTPUT ;
    USE SIGNAL ;
    PORT
      LAYER M4 ;
        RECT  64.728 18.096 64.872 18.12 ;
    END
  END sb_ra[36]
  PIN sb_ra[37]
    DIRECTION OUTPUT ;
    USE SIGNAL ;
    PORT
      LAYER M4 ;
        RECT  64.728 18.288 64.872 18.312 ;
    END
  END sb_ra[37]
  PIN sb_ra[38]
    DIRECTION OUTPUT ;
    USE SIGNAL ;
    PORT
      LAYER M4 ;
        RECT  64.728 18.48 64.872 18.504 ;
    END
  END sb_ra[38]
  PIN sb_ra[39]
    DIRECTION OUTPUT ;
    USE SIGNAL ;
    PORT
      LAYER M4 ;
        RECT  64.728 18.672 64.872 18.696 ;
    END
  END sb_ra[39]
  PIN sb_ra[3]
    DIRECTION OUTPUT ;
    USE SIGNAL ;
    PORT
      LAYER M4 ;
        RECT  64.728 11.76 64.872 11.784 ;
    END
  END sb_ra[3]
  PIN sb_ra[40]
    DIRECTION OUTPUT ;
    USE SIGNAL ;
    PORT
      LAYER M4 ;
        RECT  64.728 18.864 64.872 18.888 ;
    END
  END sb_ra[40]
  PIN sb_ra[41]
    DIRECTION OUTPUT ;
    USE SIGNAL ;
    PORT
      LAYER M4 ;
        RECT  64.728 19.056 64.872 19.08 ;
    END
  END sb_ra[41]
  PIN sb_ra[42]
    DIRECTION OUTPUT ;
    USE SIGNAL ;
    PORT
      LAYER M4 ;
        RECT  64.728 19.248 64.872 19.272 ;
    END
  END sb_ra[42]
  PIN sb_ra[43]
    DIRECTION OUTPUT ;
    USE SIGNAL ;
    PORT
      LAYER M4 ;
        RECT  64.728 19.44 64.872 19.464 ;
    END
  END sb_ra[43]
  PIN sb_ra[44]
    DIRECTION OUTPUT ;
    USE SIGNAL ;
    PORT
      LAYER M4 ;
        RECT  64.728 19.632 64.872 19.656 ;
    END
  END sb_ra[44]
  PIN sb_ra[45]
    DIRECTION OUTPUT ;
    USE SIGNAL ;
    PORT
      LAYER M4 ;
        RECT  64.728 19.824 64.872 19.848 ;
    END
  END sb_ra[45]
  PIN sb_ra[46]
    DIRECTION OUTPUT ;
    USE SIGNAL ;
    PORT
      LAYER M4 ;
        RECT  64.728 20.016 64.872 20.04 ;
    END
  END sb_ra[46]
  PIN sb_ra[47]
    DIRECTION OUTPUT ;
    USE SIGNAL ;
    PORT
      LAYER M4 ;
        RECT  64.728 20.208 64.872 20.232 ;
    END
  END sb_ra[47]
  PIN sb_ra[48]
    DIRECTION OUTPUT ;
    USE SIGNAL ;
    PORT
      LAYER M4 ;
        RECT  64.728 20.4 64.872 20.424 ;
    END
  END sb_ra[48]
  PIN sb_ra[49]
    DIRECTION OUTPUT ;
    USE SIGNAL ;
    PORT
      LAYER M4 ;
        RECT  64.728 20.592 64.872 20.616 ;
    END
  END sb_ra[49]
  PIN sb_ra[4]
    DIRECTION OUTPUT ;
    USE SIGNAL ;
    PORT
      LAYER M4 ;
        RECT  64.728 11.952 64.872 11.976 ;
    END
  END sb_ra[4]
  PIN sb_ra[50]
    DIRECTION OUTPUT ;
    USE SIGNAL ;
    PORT
      LAYER M4 ;
        RECT  64.728 20.784 64.872 20.808 ;
    END
  END sb_ra[50]
  PIN sb_ra[51]
    DIRECTION OUTPUT ;
    USE SIGNAL ;
    PORT
      LAYER M4 ;
        RECT  64.728 20.976 64.872 21 ;
    END
  END sb_ra[51]
  PIN sb_ra[52]
    DIRECTION OUTPUT ;
    USE SIGNAL ;
    PORT
      LAYER M4 ;
        RECT  64.728 21.168 64.872 21.192 ;
    END
  END sb_ra[52]
  PIN sb_ra[53]
    DIRECTION OUTPUT ;
    USE SIGNAL ;
    PORT
      LAYER M4 ;
        RECT  64.728 21.36 64.872 21.384 ;
    END
  END sb_ra[53]
  PIN sb_ra[54]
    DIRECTION OUTPUT ;
    USE SIGNAL ;
    PORT
      LAYER M4 ;
        RECT  64.728 21.552 64.872 21.576 ;
    END
  END sb_ra[54]
  PIN sb_ra[55]
    DIRECTION OUTPUT ;
    USE SIGNAL ;
    PORT
      LAYER M4 ;
        RECT  64.728 21.744 64.872 21.768 ;
    END
  END sb_ra[55]
  PIN sb_ra[56]
    DIRECTION OUTPUT ;
    USE SIGNAL ;
    PORT
      LAYER M4 ;
        RECT  64.728 21.936 64.872 21.96 ;
    END
  END sb_ra[56]
  PIN sb_ra[57]
    DIRECTION OUTPUT ;
    USE SIGNAL ;
    PORT
      LAYER M4 ;
        RECT  64.728 22.128 64.872 22.152 ;
    END
  END sb_ra[57]
  PIN sb_ra[58]
    DIRECTION OUTPUT ;
    USE SIGNAL ;
    PORT
      LAYER M4 ;
        RECT  64.728 22.32 64.872 22.344 ;
    END
  END sb_ra[58]
  PIN sb_ra[59]
    DIRECTION OUTPUT ;
    USE SIGNAL ;
    PORT
      LAYER M4 ;
        RECT  64.728 22.512 64.872 22.536 ;
    END
  END sb_ra[59]
  PIN sb_ra[5]
    DIRECTION OUTPUT ;
    USE SIGNAL ;
    PORT
      LAYER M4 ;
        RECT  64.728 12.144 64.872 12.168 ;
    END
  END sb_ra[5]
  PIN sb_ra[60]
    DIRECTION OUTPUT ;
    USE SIGNAL ;
    PORT
      LAYER M4 ;
        RECT  64.728 22.704 64.872 22.728 ;
    END
  END sb_ra[60]
  PIN sb_ra[61]
    DIRECTION OUTPUT ;
    USE SIGNAL ;
    PORT
      LAYER M4 ;
        RECT  64.728 22.896 64.872 22.92 ;
    END
  END sb_ra[61]
  PIN sb_ra[62]
    DIRECTION OUTPUT ;
    USE SIGNAL ;
    PORT
      LAYER M4 ;
        RECT  64.728 23.088 64.872 23.112 ;
    END
  END sb_ra[62]
  PIN sb_ra[63]
    DIRECTION OUTPUT ;
    USE SIGNAL ;
    PORT
      LAYER M4 ;
        RECT  64.728 23.28 64.872 23.304 ;
    END
  END sb_ra[63]
  PIN sb_ra[64]
    DIRECTION OUTPUT ;
    USE SIGNAL ;
    PORT
      LAYER M4 ;
        RECT  64.728 23.472 64.872 23.496 ;
    END
  END sb_ra[64]
  PIN sb_ra[65]
    DIRECTION OUTPUT ;
    USE SIGNAL ;
    PORT
      LAYER M4 ;
        RECT  64.728 23.664 64.872 23.688 ;
    END
  END sb_ra[65]
  PIN sb_ra[66]
    DIRECTION OUTPUT ;
    USE SIGNAL ;
    PORT
      LAYER M4 ;
        RECT  64.728 23.856 64.872 23.88 ;
    END
  END sb_ra[66]
  PIN sb_ra[67]
    DIRECTION OUTPUT ;
    USE SIGNAL ;
    PORT
      LAYER M4 ;
        RECT  64.728 24.048 64.872 24.072 ;
    END
  END sb_ra[67]
  PIN sb_ra[68]
    DIRECTION OUTPUT ;
    USE SIGNAL ;
    PORT
      LAYER M4 ;
        RECT  64.728 24.24 64.872 24.264 ;
    END
  END sb_ra[68]
  PIN sb_ra[69]
    DIRECTION OUTPUT ;
    USE SIGNAL ;
    PORT
      LAYER M4 ;
        RECT  64.728 24.432 64.872 24.456 ;
    END
  END sb_ra[69]
  PIN sb_ra[6]
    DIRECTION OUTPUT ;
    USE SIGNAL ;
    PORT
      LAYER M4 ;
        RECT  64.728 12.336 64.872 12.36 ;
    END
  END sb_ra[6]
  PIN sb_ra[70]
    DIRECTION OUTPUT ;
    USE SIGNAL ;
    PORT
      LAYER M4 ;
        RECT  64.728 24.624 64.872 24.648 ;
    END
  END sb_ra[70]
  PIN sb_ra[71]
    DIRECTION OUTPUT ;
    USE SIGNAL ;
    PORT
      LAYER M4 ;
        RECT  64.728 24.816 64.872 24.84 ;
    END
  END sb_ra[71]
  PIN sb_ra[72]
    DIRECTION OUTPUT ;
    USE SIGNAL ;
    PORT
      LAYER M4 ;
        RECT  64.728 25.008 64.872 25.032 ;
    END
  END sb_ra[72]
  PIN sb_ra[73]
    DIRECTION OUTPUT ;
    USE SIGNAL ;
    PORT
      LAYER M4 ;
        RECT  64.728 25.2 64.872 25.224 ;
    END
  END sb_ra[73]
  PIN sb_ra[74]
    DIRECTION OUTPUT ;
    USE SIGNAL ;
    PORT
      LAYER M4 ;
        RECT  64.728 25.392 64.872 25.416 ;
    END
  END sb_ra[74]
  PIN sb_ra[75]
    DIRECTION OUTPUT ;
    USE SIGNAL ;
    PORT
      LAYER M4 ;
        RECT  64.728 25.584 64.872 25.608 ;
    END
  END sb_ra[75]
  PIN sb_ra[76]
    DIRECTION OUTPUT ;
    USE SIGNAL ;
    PORT
      LAYER M4 ;
        RECT  64.728 25.776 64.872 25.8 ;
    END
  END sb_ra[76]
  PIN sb_ra[77]
    DIRECTION OUTPUT ;
    USE SIGNAL ;
    PORT
      LAYER M4 ;
        RECT  64.728 25.968 64.872 25.992 ;
    END
  END sb_ra[77]
  PIN sb_ra[78]
    DIRECTION OUTPUT ;
    USE SIGNAL ;
    PORT
      LAYER M4 ;
        RECT  64.728 26.16 64.872 26.184 ;
    END
  END sb_ra[78]
  PIN sb_ra[79]
    DIRECTION OUTPUT ;
    USE SIGNAL ;
    PORT
      LAYER M4 ;
        RECT  64.728 26.352 64.872 26.376 ;
    END
  END sb_ra[79]
  PIN sb_ra[7]
    DIRECTION OUTPUT ;
    USE SIGNAL ;
    PORT
      LAYER M4 ;
        RECT  64.728 12.528 64.872 12.552 ;
    END
  END sb_ra[7]
  PIN sb_ra[80]
    DIRECTION OUTPUT ;
    USE SIGNAL ;
    PORT
      LAYER M4 ;
        RECT  64.728 26.544 64.872 26.568 ;
    END
  END sb_ra[80]
  PIN sb_ra[81]
    DIRECTION OUTPUT ;
    USE SIGNAL ;
    PORT
      LAYER M4 ;
        RECT  64.728 26.736 64.872 26.76 ;
    END
  END sb_ra[81]
  PIN sb_ra[82]
    DIRECTION OUTPUT ;
    USE SIGNAL ;
    PORT
      LAYER M4 ;
        RECT  64.728 26.928 64.872 26.952 ;
    END
  END sb_ra[82]
  PIN sb_ra[83]
    DIRECTION OUTPUT ;
    USE SIGNAL ;
    PORT
      LAYER M4 ;
        RECT  64.728 27.12 64.872 27.144 ;
    END
  END sb_ra[83]
  PIN sb_ra[84]
    DIRECTION OUTPUT ;
    USE SIGNAL ;
    PORT
      LAYER M4 ;
        RECT  64.728 27.312 64.872 27.336 ;
    END
  END sb_ra[84]
  PIN sb_ra[85]
    DIRECTION OUTPUT ;
    USE SIGNAL ;
    PORT
      LAYER M4 ;
        RECT  64.728 27.504 64.872 27.528 ;
    END
  END sb_ra[85]
  PIN sb_ra[86]
    DIRECTION OUTPUT ;
    USE SIGNAL ;
    PORT
      LAYER M4 ;
        RECT  64.728 27.696 64.872 27.72 ;
    END
  END sb_ra[86]
  PIN sb_ra[87]
    DIRECTION OUTPUT ;
    USE SIGNAL ;
    PORT
      LAYER M4 ;
        RECT  64.728 27.888 64.872 27.912 ;
    END
  END sb_ra[87]
  PIN sb_ra[88]
    DIRECTION OUTPUT ;
    USE SIGNAL ;
    PORT
      LAYER M4 ;
        RECT  64.728 28.08 64.872 28.104 ;
    END
  END sb_ra[88]
  PIN sb_ra[89]
    DIRECTION OUTPUT ;
    USE SIGNAL ;
    PORT
      LAYER M4 ;
        RECT  64.728 28.272 64.872 28.296 ;
    END
  END sb_ra[89]
  PIN sb_ra[8]
    DIRECTION OUTPUT ;
    USE SIGNAL ;
    PORT
      LAYER M4 ;
        RECT  64.728 12.72 64.872 12.744 ;
    END
  END sb_ra[8]
  PIN sb_ra[90]
    DIRECTION OUTPUT ;
    USE SIGNAL ;
    PORT
      LAYER M4 ;
        RECT  64.728 28.464 64.872 28.488 ;
    END
  END sb_ra[90]
  PIN sb_ra[91]
    DIRECTION OUTPUT ;
    USE SIGNAL ;
    PORT
      LAYER M4 ;
        RECT  64.728 28.656 64.872 28.68 ;
    END
  END sb_ra[91]
  PIN sb_ra[92]
    DIRECTION OUTPUT ;
    USE SIGNAL ;
    PORT
      LAYER M4 ;
        RECT  64.728 28.848 64.872 28.872 ;
    END
  END sb_ra[92]
  PIN sb_ra[93]
    DIRECTION OUTPUT ;
    USE SIGNAL ;
    PORT
      LAYER M4 ;
        RECT  64.728 29.04 64.872 29.064 ;
    END
  END sb_ra[93]
  PIN sb_ra[94]
    DIRECTION OUTPUT ;
    USE SIGNAL ;
    PORT
      LAYER M4 ;
        RECT  64.728 29.232 64.872 29.256 ;
    END
  END sb_ra[94]
  PIN sb_ra[95]
    DIRECTION OUTPUT ;
    USE SIGNAL ;
    PORT
      LAYER M4 ;
        RECT  64.728 29.424 64.872 29.448 ;
    END
  END sb_ra[95]
  PIN sb_ra[96]
    DIRECTION OUTPUT ;
    USE SIGNAL ;
    PORT
      LAYER M4 ;
        RECT  64.728 29.616 64.872 29.64 ;
    END
  END sb_ra[96]
  PIN sb_ra[97]
    DIRECTION OUTPUT ;
    USE SIGNAL ;
    PORT
      LAYER M4 ;
        RECT  64.728 29.808 64.872 29.832 ;
    END
  END sb_ra[97]
  PIN sb_ra[98]
    DIRECTION OUTPUT ;
    USE SIGNAL ;
    PORT
      LAYER M4 ;
        RECT  64.728 30 64.872 30.024 ;
    END
  END sb_ra[98]
  PIN sb_ra[99]
    DIRECTION OUTPUT ;
    USE SIGNAL ;
    PORT
      LAYER M4 ;
        RECT  64.728 30.192 64.872 30.216 ;
    END
  END sb_ra[99]
  PIN sb_ra[9]
    DIRECTION OUTPUT ;
    USE SIGNAL ;
    PORT
      LAYER M4 ;
        RECT  64.728 12.912 64.872 12.936 ;
    END
  END sb_ra[9]
  PIN sb_re[0]
    DIRECTION OUTPUT ;
    USE SIGNAL ;
    PORT
      LAYER M4 ;
        RECT  64.728 8.112 64.872 8.136 ;
    END
  END sb_re[0]
  PIN sb_re[10]
    DIRECTION OUTPUT ;
    USE SIGNAL ;
    PORT
      LAYER M4 ;
        RECT  64.728 10.032 64.872 10.056 ;
    END
  END sb_re[10]
  PIN sb_re[11]
    DIRECTION OUTPUT ;
    USE SIGNAL ;
    PORT
      LAYER M4 ;
        RECT  64.728 10.224 64.872 10.248 ;
    END
  END sb_re[11]
  PIN sb_re[12]
    DIRECTION OUTPUT ;
    USE SIGNAL ;
    PORT
      LAYER M4 ;
        RECT  64.728 10.416 64.872 10.44 ;
    END
  END sb_re[12]
  PIN sb_re[13]
    DIRECTION OUTPUT ;
    USE SIGNAL ;
    PORT
      LAYER M4 ;
        RECT  64.728 10.608 64.872 10.632 ;
    END
  END sb_re[13]
  PIN sb_re[14]
    DIRECTION OUTPUT ;
    USE SIGNAL ;
    PORT
      LAYER M4 ;
        RECT  64.728 10.8 64.872 10.824 ;
    END
  END sb_re[14]
  PIN sb_re[15]
    DIRECTION OUTPUT ;
    USE SIGNAL ;
    PORT
      LAYER M4 ;
        RECT  64.728 10.992 64.872 11.016 ;
    END
  END sb_re[15]
  PIN sb_re[1]
    DIRECTION OUTPUT ;
    USE SIGNAL ;
    PORT
      LAYER M4 ;
        RECT  64.728 8.304 64.872 8.328 ;
    END
  END sb_re[1]
  PIN sb_re[2]
    DIRECTION OUTPUT ;
    USE SIGNAL ;
    PORT
      LAYER M4 ;
        RECT  64.728 8.496 64.872 8.52 ;
    END
  END sb_re[2]
  PIN sb_re[3]
    DIRECTION OUTPUT ;
    USE SIGNAL ;
    PORT
      LAYER M4 ;
        RECT  64.728 8.688 64.872 8.712 ;
    END
  END sb_re[3]
  PIN sb_re[4]
    DIRECTION OUTPUT ;
    USE SIGNAL ;
    PORT
      LAYER M4 ;
        RECT  64.728 8.88 64.872 8.904 ;
    END
  END sb_re[4]
  PIN sb_re[5]
    DIRECTION OUTPUT ;
    USE SIGNAL ;
    PORT
      LAYER M4 ;
        RECT  64.728 9.072 64.872 9.096 ;
    END
  END sb_re[5]
  PIN sb_re[6]
    DIRECTION OUTPUT ;
    USE SIGNAL ;
    PORT
      LAYER M4 ;
        RECT  64.728 9.264 64.872 9.288 ;
    END
  END sb_re[6]
  PIN sb_re[7]
    DIRECTION OUTPUT ;
    USE SIGNAL ;
    PORT
      LAYER M4 ;
        RECT  64.728 9.456 64.872 9.48 ;
    END
  END sb_re[7]
  PIN sb_re[8]
    DIRECTION OUTPUT ;
    USE SIGNAL ;
    PORT
      LAYER M4 ;
        RECT  64.728 9.648 64.872 9.672 ;
    END
  END sb_re[8]
  PIN sb_re[9]
    DIRECTION OUTPUT ;
    USE SIGNAL ;
    PORT
      LAYER M4 ;
        RECT  64.728 9.84 64.872 9.864 ;
    END
  END sb_re[9]
  PIN VDD
    DIRECTION INOUT ;
    USE POWER ;
    PORT
      LAYER M5 ;
        RECT  61.992 2.151 62.112 62.649 ;
        RECT  59.292 2.151 59.412 62.649 ;
        RECT  56.592 2.151 56.712 62.649 ;
        RECT  53.892 2.151 54.012 62.649 ;
        RECT  51.192 2.151 51.312 62.649 ;
        RECT  48.492 2.151 48.612 62.649 ;
        RECT  45.792 2.151 45.912 62.649 ;
        RECT  43.092 2.151 43.212 62.649 ;
        RECT  40.392 2.151 40.512 62.649 ;
        RECT  37.692 2.151 37.812 62.649 ;
        RECT  34.992 2.151 35.112 62.649 ;
        RECT  32.292 2.151 32.412 62.649 ;
        RECT  29.592 2.151 29.712 62.649 ;
        RECT  26.892 2.151 27.012 62.649 ;
        RECT  24.192 2.151 24.312 62.649 ;
        RECT  21.492 2.151 21.612 62.649 ;
        RECT  18.792 2.151 18.912 62.649 ;
        RECT  16.092 2.151 16.212 62.649 ;
        RECT  13.392 2.151 13.512 62.649 ;
        RECT  10.692 2.151 10.812 62.649 ;
        RECT  7.992 2.151 8.112 62.649 ;
        RECT  5.292 2.151 5.412 62.649 ;
        RECT  2.592 2.151 2.712 62.649 ;
    END
  END VDD
  PIN VSS
    DIRECTION INOUT ;
    USE GROUND ;
    PORT
      LAYER M5 ;
        RECT  61.8 2.137 61.92 62.663 ;
        RECT  59.1 2.137 59.22 62.663 ;
        RECT  56.4 2.137 56.52 62.663 ;
        RECT  53.7 2.137 53.82 62.663 ;
        RECT  51 2.137 51.12 62.663 ;
        RECT  48.3 2.137 48.42 62.663 ;
        RECT  45.6 2.137 45.72 62.663 ;
        RECT  42.9 2.137 43.02 62.663 ;
        RECT  40.2 2.137 40.32 62.663 ;
        RECT  37.5 2.137 37.62 62.663 ;
        RECT  34.8 2.137 34.92 62.663 ;
        RECT  32.1 2.137 32.22 62.663 ;
        RECT  29.4 2.137 29.52 62.663 ;
        RECT  26.7 2.137 26.82 62.663 ;
        RECT  24 2.137 24.12 62.663 ;
        RECT  21.3 2.137 21.42 62.663 ;
        RECT  18.6 2.137 18.72 62.663 ;
        RECT  15.9 2.137 16.02 62.663 ;
        RECT  13.2 2.137 13.32 62.663 ;
        RECT  10.5 2.137 10.62 62.663 ;
        RECT  7.8 2.137 7.92 62.663 ;
        RECT  5.1 2.137 5.22 62.663 ;
        RECT  2.4 2.137 2.52 62.663 ;
    END
  END VSS
  OBS
    LAYER RVTN ;
     RECT  2.16 2.16 62.64 2.295 ;
     RECT  2.16 2.565 62.64 2.835 ;
     RECT  2.16 3.105 62.64 3.375 ;
     RECT  2.16 3.645 62.64 3.915 ;
     RECT  2.16 4.185 62.64 4.455 ;
     RECT  2.16 4.725 62.64 4.995 ;
     RECT  2.16 5.265 62.64 5.535 ;
     RECT  2.16 5.805 62.64 6.075 ;
     RECT  2.16 6.345 62.64 6.615 ;
     RECT  2.16 6.885 62.64 7.155 ;
     RECT  2.16 7.425 62.64 7.695 ;
     RECT  2.16 7.965 62.64 8.235 ;
     RECT  2.16 8.505 62.64 8.775 ;
     RECT  2.16 9.045 62.64 9.315 ;
     RECT  2.16 9.585 62.64 9.855 ;
     RECT  2.16 10.125 62.64 10.395 ;
     RECT  2.16 10.665 62.64 10.935 ;
     RECT  2.16 11.205 62.64 11.475 ;
     RECT  2.16 11.745 62.64 12.015 ;
     RECT  2.16 12.285 62.64 12.555 ;
     RECT  2.16 12.825 62.64 13.095 ;
     RECT  2.16 13.365 62.64 13.635 ;
     RECT  2.16 13.905 62.64 14.175 ;
     RECT  2.16 14.445 62.64 14.715 ;
     RECT  2.16 14.985 62.64 15.255 ;
     RECT  2.16 15.525 62.64 15.795 ;
     RECT  2.16 16.065 62.64 16.335 ;
     RECT  2.16 16.605 62.64 16.875 ;
     RECT  2.16 17.145 62.64 17.415 ;
     RECT  2.16 17.685 62.64 17.955 ;
     RECT  2.16 18.225 62.64 18.495 ;
     RECT  2.16 18.765 62.64 19.035 ;
     RECT  2.16 19.305 62.64 19.575 ;
     RECT  2.16 19.845 62.64 20.115 ;
     RECT  2.16 20.385 62.64 20.655 ;
     RECT  2.16 20.925 62.64 21.195 ;
     RECT  2.16 21.465 62.64 21.735 ;
     RECT  2.16 22.005 62.64 22.275 ;
     RECT  2.16 22.545 62.64 22.815 ;
     RECT  2.16 23.085 62.64 23.355 ;
     RECT  2.16 23.625 62.64 23.895 ;
     RECT  2.16 24.165 62.64 24.435 ;
     RECT  2.16 24.705 62.64 24.975 ;
     RECT  2.16 25.245 62.64 25.515 ;
     RECT  2.16 25.785 62.64 26.055 ;
     RECT  2.16 26.325 62.64 26.595 ;
     RECT  2.16 26.865 62.64 27.135 ;
     RECT  2.16 27.405 62.64 27.675 ;
     RECT  2.16 27.945 62.64 28.215 ;
     RECT  2.16 28.485 62.64 28.755 ;
     RECT  2.16 29.025 62.64 29.295 ;
     RECT  2.16 29.565 62.64 29.835 ;
     RECT  2.16 30.105 62.64 30.375 ;
     RECT  2.16 30.645 62.64 30.915 ;
     RECT  2.16 31.185 62.64 31.455 ;
     RECT  2.16 31.725 62.64 31.995 ;
     RECT  2.16 32.265 62.64 32.535 ;
     RECT  2.16 32.805 62.64 33.075 ;
     RECT  2.16 33.345 62.64 33.615 ;
     RECT  2.16 33.885 62.64 34.155 ;
     RECT  2.16 34.425 62.64 34.695 ;
     RECT  2.16 34.965 62.64 35.235 ;
     RECT  2.16 35.505 62.64 35.775 ;
     RECT  2.16 36.045 62.64 36.315 ;
     RECT  2.16 36.585 62.64 36.855 ;
     RECT  2.16 37.125 62.64 37.395 ;
     RECT  2.16 37.665 62.64 37.935 ;
     RECT  2.16 38.205 62.64 38.475 ;
     RECT  2.16 38.745 62.64 39.015 ;
     RECT  2.16 39.285 62.64 39.555 ;
     RECT  2.16 39.825 62.64 40.095 ;
     RECT  2.16 40.365 62.64 40.635 ;
     RECT  2.16 40.905 62.64 41.175 ;
     RECT  2.16 41.445 62.64 41.715 ;
     RECT  2.16 41.985 62.64 42.255 ;
     RECT  2.16 42.525 62.64 42.795 ;
     RECT  2.16 43.065 62.64 43.335 ;
     RECT  2.16 43.605 62.64 43.875 ;
     RECT  2.16 44.145 62.64 44.415 ;
     RECT  2.16 44.685 62.64 44.955 ;
     RECT  2.16 45.225 62.64 45.495 ;
     RECT  2.16 45.765 62.64 46.035 ;
     RECT  2.16 46.305 62.64 46.575 ;
     RECT  2.16 46.845 62.64 47.115 ;
     RECT  2.16 47.385 62.64 47.655 ;
     RECT  2.16 47.925 62.64 48.195 ;
     RECT  2.16 48.465 62.64 48.735 ;
     RECT  2.16 49.005 62.64 49.275 ;
     RECT  2.16 49.545 62.64 49.815 ;
     RECT  2.16 50.085 62.64 50.355 ;
     RECT  2.16 50.625 62.64 50.895 ;
     RECT  2.16 51.165 62.64 51.435 ;
     RECT  2.16 51.705 62.64 51.975 ;
     RECT  2.16 52.245 62.64 52.515 ;
     RECT  2.16 52.785 62.64 53.055 ;
     RECT  2.16 53.325 62.64 53.595 ;
     RECT  2.16 53.865 62.64 54.135 ;
     RECT  2.16 54.405 62.64 54.675 ;
     RECT  2.16 54.945 62.64 55.215 ;
     RECT  2.16 55.485 62.64 55.755 ;
     RECT  2.16 56.025 62.64 56.295 ;
     RECT  2.16 56.565 62.64 56.835 ;
     RECT  2.16 57.105 62.64 57.375 ;
     RECT  2.16 57.645 62.64 57.915 ;
     RECT  2.16 58.185 62.64 58.455 ;
     RECT  2.16 58.725 62.64 58.995 ;
     RECT  2.16 59.265 62.64 59.535 ;
     RECT  2.16 59.805 62.64 60.075 ;
     RECT  2.16 60.345 62.64 60.615 ;
     RECT  2.16 60.885 62.64 61.155 ;
     RECT  2.16 61.425 62.64 61.695 ;
     RECT  2.16 61.965 62.64 62.235 ;
     RECT  2.16 62.505 62.64 62.64 ;
    LAYER RVTP ;
     RECT  2.16 2.295 62.64 2.565 ;
     RECT  2.16 2.835 62.64 3.105 ;
     RECT  2.16 3.375 62.64 3.645 ;
     RECT  2.16 3.915 62.64 4.185 ;
     RECT  2.16 4.455 62.64 4.725 ;
     RECT  2.16 4.995 62.64 5.265 ;
     RECT  2.16 5.535 62.64 5.805 ;
     RECT  2.16 6.075 62.64 6.345 ;
     RECT  2.16 6.615 62.64 6.885 ;
     RECT  2.16 7.155 62.64 7.425 ;
     RECT  2.16 7.695 62.64 7.965 ;
     RECT  2.16 8.235 62.64 8.505 ;
     RECT  2.16 8.775 62.64 9.045 ;
     RECT  2.16 9.315 62.64 9.585 ;
     RECT  2.16 9.855 62.64 10.125 ;
     RECT  2.16 10.395 62.64 10.665 ;
     RECT  2.16 10.935 62.64 11.205 ;
     RECT  2.16 11.475 62.64 11.745 ;
     RECT  2.16 12.015 62.64 12.285 ;
     RECT  2.16 12.555 62.64 12.825 ;
     RECT  2.16 13.095 62.64 13.365 ;
     RECT  2.16 13.635 62.64 13.905 ;
     RECT  2.16 14.175 62.64 14.445 ;
     RECT  2.16 14.715 62.64 14.985 ;
     RECT  2.16 15.255 62.64 15.525 ;
     RECT  2.16 15.795 62.64 16.065 ;
     RECT  2.16 16.335 62.64 16.605 ;
     RECT  2.16 16.875 62.64 17.145 ;
     RECT  2.16 17.415 62.64 17.685 ;
     RECT  2.16 17.955 62.64 18.225 ;
     RECT  2.16 18.495 62.64 18.765 ;
     RECT  2.16 19.035 62.64 19.305 ;
     RECT  2.16 19.575 62.64 19.845 ;
     RECT  2.16 20.115 62.64 20.385 ;
     RECT  2.16 20.655 62.64 20.925 ;
     RECT  2.16 21.195 62.64 21.465 ;
     RECT  2.16 21.735 62.64 22.005 ;
     RECT  2.16 22.275 62.64 22.545 ;
     RECT  2.16 22.815 62.64 23.085 ;
     RECT  2.16 23.355 62.64 23.625 ;
     RECT  2.16 23.895 62.64 24.165 ;
     RECT  2.16 24.435 62.64 24.705 ;
     RECT  2.16 24.975 62.64 25.245 ;
     RECT  2.16 25.515 62.64 25.785 ;
     RECT  2.16 26.055 62.64 26.325 ;
     RECT  2.16 26.595 62.64 26.865 ;
     RECT  2.16 27.135 62.64 27.405 ;
     RECT  2.16 27.675 62.64 27.945 ;
     RECT  2.16 28.215 62.64 28.485 ;
     RECT  2.16 28.755 62.64 29.025 ;
     RECT  2.16 29.295 62.64 29.565 ;
     RECT  2.16 29.835 62.64 30.105 ;
     RECT  2.16 30.375 62.64 30.645 ;
     RECT  2.16 30.915 62.64 31.185 ;
     RECT  2.16 31.455 62.64 31.725 ;
     RECT  2.16 31.995 62.64 32.265 ;
     RECT  2.16 32.535 62.64 32.805 ;
     RECT  2.16 33.075 62.64 33.345 ;
     RECT  2.16 33.615 62.64 33.885 ;
     RECT  2.16 34.155 62.64 34.425 ;
     RECT  2.16 34.695 62.64 34.965 ;
     RECT  2.16 35.235 62.64 35.505 ;
     RECT  2.16 35.775 62.64 36.045 ;
     RECT  2.16 36.315 62.64 36.585 ;
     RECT  2.16 36.855 62.64 37.125 ;
     RECT  2.16 37.395 62.64 37.665 ;
     RECT  2.16 37.935 62.64 38.205 ;
     RECT  2.16 38.475 62.64 38.745 ;
     RECT  2.16 39.015 62.64 39.285 ;
     RECT  2.16 39.555 62.64 39.825 ;
     RECT  2.16 40.095 62.64 40.365 ;
     RECT  2.16 40.635 62.64 40.905 ;
     RECT  2.16 41.175 62.64 41.445 ;
     RECT  2.16 41.715 62.64 41.985 ;
     RECT  2.16 42.255 62.64 42.525 ;
     RECT  2.16 42.795 62.64 43.065 ;
     RECT  2.16 43.335 62.64 43.605 ;
     RECT  2.16 43.875 62.64 44.145 ;
     RECT  2.16 44.415 62.64 44.685 ;
     RECT  2.16 44.955 62.64 45.225 ;
     RECT  2.16 45.495 62.64 45.765 ;
     RECT  2.16 46.035 62.64 46.305 ;
     RECT  2.16 46.575 62.64 46.845 ;
     RECT  2.16 47.115 62.64 47.385 ;
     RECT  2.16 47.655 62.64 47.925 ;
     RECT  2.16 48.195 62.64 48.465 ;
     RECT  2.16 48.735 62.64 49.005 ;
     RECT  2.16 49.275 62.64 49.545 ;
     RECT  2.16 49.815 62.64 50.085 ;
     RECT  2.16 50.355 62.64 50.625 ;
     RECT  2.16 50.895 62.64 51.165 ;
     RECT  2.16 51.435 62.64 51.705 ;
     RECT  2.16 51.975 62.64 52.245 ;
     RECT  2.16 52.515 62.64 52.785 ;
     RECT  2.16 53.055 62.64 53.325 ;
     RECT  2.16 53.595 62.64 53.865 ;
     RECT  2.16 54.135 62.64 54.405 ;
     RECT  2.16 54.675 62.64 54.945 ;
     RECT  2.16 55.215 62.64 55.485 ;
     RECT  2.16 55.755 62.64 56.025 ;
     RECT  2.16 56.295 62.64 56.565 ;
     RECT  2.16 56.835 62.64 57.105 ;
     RECT  2.16 57.375 62.64 57.645 ;
     RECT  2.16 57.915 62.64 58.185 ;
     RECT  2.16 58.455 62.64 58.725 ;
     RECT  2.16 58.995 62.64 59.265 ;
     RECT  2.16 59.535 62.64 59.805 ;
     RECT  2.16 60.075 62.64 60.345 ;
     RECT  2.16 60.615 62.64 60.885 ;
     RECT  2.16 61.155 62.64 61.425 ;
     RECT  2.16 61.695 62.64 61.965 ;
     RECT  2.16 62.235 62.64 62.505 ;
    LAYER M1 ;
     RECT  2.16 2.151 62.64 62.649 ;
    LAYER M2 ;
     RECT  0.067 27.342 2.16 27.36 ;
     RECT  0.067 32.472 2.16 32.49 ;
     RECT  0.067 34.74 2.16 34.758 ;
     RECT  2.16 2.151 62.64 62.649 ;
     RECT  62.64 10.836 62.735 36.612 ;
     RECT  62.64 37.44 62.735 57.834 ;
     RECT  62.735 22.446 63.239 36.612 ;
     RECT  62.735 10.836 63.275 21.654 ;
     RECT  63.239 22.446 63.275 34.65 ;
     RECT  63.239 35.406 63.275 36.612 ;
     RECT  62.735 37.566 63.275 57.834 ;
     RECT  63.275 13.176 63.311 21.654 ;
     RECT  63.275 37.566 63.311 52.812 ;
     RECT  63.275 53.946 63.311 57.834 ;
     RECT  63.311 13.176 63.815 19.494 ;
     RECT  63.275 23.598 63.815 34.65 ;
     RECT  63.311 37.566 63.815 52.002 ;
     RECT  62.64 7.596 63.851 10.044 ;
     RECT  63.815 13.176 63.851 17.334 ;
     RECT  63.815 18.126 63.851 19.494 ;
     RECT  63.311 20.322 63.851 21.654 ;
     RECT  63.275 22.446 63.851 22.806 ;
     RECT  63.815 23.598 63.851 27.63 ;
     RECT  63.815 28.386 63.851 34.65 ;
     RECT  63.275 35.676 63.851 36.612 ;
     RECT  63.815 37.566 63.851 37.584 ;
     RECT  63.815 38.376 63.851 52.002 ;
     RECT  63.851 8.946 63.887 9.846 ;
     RECT  63.275 10.836 63.887 12.276 ;
     RECT  63.851 13.176 63.887 13.284 ;
     RECT  63.851 14.256 63.887 14.472 ;
     RECT  63.851 16.146 63.887 17.064 ;
     RECT  63.851 20.322 63.887 21.456 ;
     RECT  63.851 26.226 63.887 27.63 ;
     RECT  63.851 30.186 63.887 34.65 ;
     RECT  63.851 35.748 63.887 36.612 ;
     RECT  63.851 44.19 63.887 46.944 ;
     RECT  63.851 47.826 63.887 50.184 ;
     RECT  63.851 51.066 63.887 52.002 ;
     RECT  63.851 7.596 63.923 7.92 ;
     RECT  63.887 30.186 63.923 31.212 ;
     RECT  63.887 44.766 63.923 45.864 ;
     RECT  63.887 48.942 63.923 50.184 ;
     RECT  63.923 7.902 63.959 7.92 ;
     RECT  63.887 9.018 63.959 9.846 ;
     RECT  63.887 32.004 63.959 32.526 ;
     RECT  63.851 38.988 63.959 43.164 ;
     RECT  63.923 45.27 63.959 45.864 ;
     RECT  63.923 49.248 63.959 50.184 ;
     RECT  63.959 9.018 63.995 9.036 ;
     RECT  63.887 48.006 63.995 48.15 ;
     RECT  63.311 54.414 64.535 57.834 ;
     RECT  64.535 54.414 64.571 56.484 ;
     RECT  64.535 57.42 64.571 57.834 ;
     RECT  63.923 30.816 64.607 31.212 ;
     RECT  64.571 55.386 64.607 56.484 ;
     RECT  63.887 33.588 64.615 34.65 ;
     RECT  63.959 38.988 64.643 41.976 ;
     RECT  64.571 54.414 64.643 54.504 ;
     RECT  64.607 55.386 64.643 56.124 ;
     RECT  63.851 18.396 64.679 19.404 ;
     RECT  63.887 20.664 64.679 21.186 ;
     RECT  63.851 23.598 64.679 24.93 ;
     RECT  64.607 30.816 64.679 31.176 ;
     RECT  63.887 36.288 64.679 36.504 ;
     RECT  64.643 38.988 64.679 41.778 ;
     RECT  63.959 43.038 64.679 43.164 ;
     RECT  63.959 45.306 64.679 45.864 ;
     RECT  63.887 46.89 64.679 46.944 ;
     RECT  63.887 51.516 64.679 52.002 ;
     RECT  64.643 54.486 64.679 54.504 ;
     RECT  64.643 55.386 64.679 55.584 ;
     RECT  64.571 57.546 64.679 57.834 ;
     RECT  63.959 9.828 64.715 9.846 ;
     RECT  63.887 10.836 64.715 10.854 ;
     RECT  63.887 11.754 64.715 11.772 ;
     RECT  63.887 13.176 64.715 13.194 ;
     RECT  63.887 14.256 64.715 14.274 ;
     RECT  63.887 16.146 64.715 16.164 ;
     RECT  64.679 18.396 64.715 18.414 ;
     RECT  64.679 19.386 64.715 19.404 ;
     RECT  64.679 20.664 64.715 20.682 ;
     RECT  63.851 22.788 64.715 22.806 ;
     RECT  64.679 23.706 64.715 24.156 ;
     RECT  64.679 24.912 64.715 24.93 ;
     RECT  63.887 26.226 64.715 26.964 ;
     RECT  63.851 28.728 64.715 29.394 ;
     RECT  63.959 32.004 64.715 32.184 ;
     RECT  64.615 33.048 64.715 34.65 ;
     RECT  64.679 36.486 64.715 36.504 ;
     RECT  64.679 38.988 64.715 39.924 ;
     RECT  64.679 41.76 64.715 41.778 ;
     RECT  64.679 43.146 64.715 43.164 ;
     RECT  64.679 45.846 64.715 45.864 ;
     RECT  64.679 46.89 64.715 46.908 ;
     RECT  63.995 48.006 64.715 48.024 ;
     RECT  63.959 49.86 64.715 50.184 ;
     RECT  64.679 51.516 64.715 51.534 ;
     RECT  63.311 52.794 64.715 52.812 ;
     RECT  64.679 55.566 64.715 55.584 ;
     RECT  64.679 57.546 64.715 57.564 ;
    LAYER M3 ;
     RECT  2.415 2.143 2.505 2.413 ;
     RECT  5.115 2.143 5.205 2.413 ;
     RECT  7.815 2.143 7.905 2.413 ;
     RECT  10.515 2.143 10.605 2.413 ;
     RECT  13.215 2.143 13.305 2.413 ;
     RECT  15.915 2.143 16.005 2.413 ;
     RECT  18.615 2.143 18.705 2.413 ;
     RECT  21.315 2.143 21.405 2.413 ;
     RECT  24.015 2.143 24.105 2.413 ;
     RECT  26.715 2.143 26.805 2.413 ;
     RECT  29.415 2.143 29.505 2.413 ;
     RECT  32.115 2.143 32.205 2.413 ;
     RECT  34.815 2.143 34.905 2.413 ;
     RECT  37.515 2.143 37.605 2.413 ;
     RECT  40.215 2.143 40.305 2.413 ;
     RECT  42.915 2.143 43.005 2.413 ;
     RECT  45.615 2.143 45.705 2.413 ;
     RECT  48.315 2.143 48.405 2.413 ;
     RECT  51.015 2.143 51.105 2.413 ;
     RECT  53.715 2.143 53.805 2.413 ;
     RECT  56.415 2.143 56.505 2.413 ;
     RECT  59.115 2.143 59.205 2.413 ;
     RECT  61.815 2.143 61.905 2.413 ;
     RECT  34.815 2.413 35.097 6.859 ;
     RECT  34.596 6.859 35.097 7.115 ;
     RECT  61.815 2.413 62.097 7.501 ;
     RECT  61.815 7.501 62.298 7.735 ;
     RECT  63.9 7.591 63.918 7.861 ;
     RECT  63.864 7.861 63.918 7.897 ;
     RECT  61.128 7.735 62.298 7.933 ;
     RECT  60.912 7.933 62.298 8.005 ;
     RECT  60.912 8.005 62.334 8.159 ;
     RECT  59.115 2.413 59.397 8.275 ;
     RECT  59.115 8.275 59.886 8.311 ;
     RECT  60.912 8.159 62.19 8.311 ;
     RECT  59.115 8.311 60.102 8.401 ;
     RECT  60.876 8.311 62.19 8.401 ;
     RECT  59.115 8.401 62.19 8.465 ;
     RECT  56.415 2.413 56.697 8.491 ;
     RECT  63.864 7.897 63.954 8.491 ;
     RECT  56.415 8.491 57.33 8.537 ;
     RECT  59.115 8.465 62.154 8.539 ;
     RECT  63.828 8.491 63.954 8.671 ;
     RECT  63.288 8.671 63.954 8.717 ;
     RECT  57.528 8.581 57.546 8.851 ;
     RECT  58.5 8.539 62.154 8.851 ;
     RECT  63.828 8.717 63.954 9.013 ;
     RECT  56.415 8.537 56.754 9.067 ;
     RECT  56.412 9.067 56.754 9.113 ;
     RECT  57.528 8.851 62.154 9.311 ;
     RECT  56.415 9.113 56.754 9.589 ;
     RECT  58.212 9.311 62.154 9.625 ;
     RECT  63.828 9.013 63.99 9.643 ;
     RECT  58.212 9.625 62.334 9.823 ;
     RECT  56.415 9.589 56.79 9.931 ;
     RECT  58.212 9.823 62.694 9.959 ;
     RECT  63.828 9.643 64.71 10.049 ;
     RECT  58.212 9.959 62.334 10.057 ;
     RECT  63.864 10.049 64.71 10.061 ;
     RECT  56.415 9.931 56.898 10.129 ;
     RECT  56.415 10.129 57.258 10.291 ;
     RECT  56.376 10.291 57.258 10.435 ;
     RECT  58.032 10.057 62.334 10.435 ;
     RECT  63.9 10.061 64.71 10.445 ;
     RECT  55.8 10.435 62.334 10.651 ;
     RECT  55.728 10.651 62.334 10.705 ;
     RECT  63.936 10.445 64.71 10.829 ;
     RECT  55.152 10.705 62.334 10.939 ;
     RECT  54.864 10.939 62.334 10.975 ;
     RECT  54.864 10.975 62.694 11.011 ;
     RECT  54.864 11.011 62.766 11.129 ;
     RECT  53.715 2.413 53.997 11.281 ;
     RECT  54.864 11.129 59.778 11.281 ;
     RECT  60.696 11.129 62.766 11.405 ;
     RECT  63.864 11.173 63.882 11.755 ;
     RECT  64.692 10.829 64.71 11.777 ;
     RECT  53.715 11.281 59.778 11.947 ;
     RECT  60.696 11.405 62.298 11.947 ;
     RECT  63.828 11.755 63.882 12.139 ;
     RECT  53.715 11.947 62.298 12.325 ;
     RECT  63.252 12.139 63.882 12.325 ;
     RECT  53.715 12.325 63.882 12.365 ;
     RECT  53.715 12.365 62.097 13.261 ;
     RECT  63.252 12.365 63.882 13.361 ;
     RECT  34.704 7.115 35.097 13.981 ;
     RECT  63.792 13.361 63.882 14.251 ;
     RECT  64.692 12.907 64.71 14.279 ;
     RECT  53.715 13.261 62.442 14.377 ;
     RECT  53.715 14.377 62.73 14.711 ;
     RECT  63.756 14.251 63.882 14.827 ;
     RECT  53.715 14.711 62.154 14.945 ;
     RECT  63.252 14.827 63.882 15.245 ;
     RECT  63.252 15.245 63.846 15.521 ;
     RECT  53.715 14.945 62.097 15.979 ;
     RECT  51.015 2.413 51.297 16.069 ;
     RECT  50.328 16.069 51.297 16.141 ;
     RECT  64.692 15.595 64.71 16.169 ;
     RECT  50.256 16.141 51.297 16.259 ;
     RECT  53.715 15.979 62.262 16.303 ;
     RECT  53.715 16.303 62.694 16.363 ;
     RECT  63.828 15.521 63.846 16.363 ;
     RECT  53.715 16.363 63.846 16.501 ;
     RECT  53.715 16.501 63.882 16.871 ;
     RECT  63.792 16.871 63.882 17.357 ;
     RECT  53.715 16.871 62.73 17.549 ;
     RECT  53.715 17.549 62.334 17.609 ;
     RECT  63.792 17.357 63.846 17.899 ;
     RECT  63.252 17.899 63.846 18.059 ;
     RECT  64.692 18.091 64.71 18.283 ;
     RECT  64.656 18.283 64.71 18.419 ;
     RECT  63.288 18.059 63.846 18.701 ;
     RECT  53.715 17.609 62.154 18.769 ;
     RECT  53.715 18.769 62.298 18.841 ;
     RECT  53.715 18.841 62.73 18.893 ;
     RECT  53.715 18.893 62.298 19.111 ;
     RECT  64.656 18.419 64.674 19.139 ;
     RECT  53.064 19.111 62.298 19.229 ;
     RECT  53.064 19.229 62.262 19.237 ;
     RECT  63.828 18.701 63.846 19.435 ;
     RECT  63.252 19.435 63.846 19.499 ;
     RECT  53.028 19.237 62.262 19.507 ;
     RECT  63.252 19.499 63.306 19.627 ;
     RECT  52.956 19.507 62.262 19.921 ;
     RECT  52.344 19.921 62.262 20.039 ;
     RECT  63.216 19.627 63.306 20.045 ;
     RECT  52.956 20.039 62.262 20.083 ;
     RECT  52.956 20.083 62.694 20.183 ;
     RECT  52.2 20.149 52.218 20.189 ;
     RECT  60.84 20.183 62.694 20.237 ;
     RECT  64.692 19.243 64.71 20.395 ;
     RECT  63.864 20.317 63.882 20.621 ;
     RECT  64.656 20.395 64.71 20.687 ;
     RECT  52.956 20.183 60.102 20.965 ;
     RECT  60.84 20.237 62.154 20.965 ;
     RECT  64.656 20.687 64.674 21.191 ;
     RECT  63.252 20.779 63.846 21.197 ;
     RECT  52.956 20.965 62.154 21.235 ;
     RECT  63.792 21.197 63.846 21.389 ;
     RECT  63.828 21.389 63.846 21.433 ;
     RECT  51.015 16.259 51.297 21.541 ;
     RECT  52.956 21.235 62.334 21.541 ;
     RECT  52.956 21.541 62.73 21.643 ;
     RECT  52.776 21.643 62.73 21.739 ;
     RECT  51.015 21.541 51.93 21.775 ;
     RECT  52.74 21.739 62.73 21.775 ;
     RECT  63.828 21.433 63.882 21.965 ;
     RECT  51.015 21.775 62.73 22.073 ;
     RECT  52.848 22.073 62.73 22.157 ;
     RECT  52.848 22.157 62.334 22.205 ;
     RECT  63.828 21.965 63.846 22.315 ;
     RECT  63.792 22.315 63.846 22.469 ;
     RECT  64.692 22.507 64.71 22.699 ;
     RECT  63.792 22.469 63.81 22.739 ;
     RECT  51.015 22.073 52.038 22.775 ;
     RECT  53.1 22.205 62.334 22.891 ;
     RECT  53.1 22.891 62.694 23.081 ;
     RECT  63.252 23.275 63.27 23.351 ;
     RECT  53.1 23.081 62.514 23.395 ;
     RECT  53.064 23.395 62.514 23.803 ;
     RECT  20.268 23.791 20.502 23.837 ;
     RECT  46.764 23.659 46.782 23.837 ;
     RECT  52.956 23.803 62.514 23.927 ;
     RECT  20.484 23.837 20.502 23.933 ;
     RECT  22.716 23.803 22.842 23.933 ;
     RECT  30.78 23.803 30.798 23.933 ;
     RECT  38.772 23.803 38.79 23.933 ;
     RECT  51.015 22.775 52.002 23.971 ;
     RECT  52.956 23.927 62.334 23.971 ;
     RECT  64.656 22.699 64.71 24.539 ;
     RECT  63.252 24.235 63.27 24.601 ;
     RECT  63.252 24.601 63.306 24.781 ;
     RECT  63.252 24.781 63.882 24.845 ;
     RECT  64.692 24.539 64.71 24.935 ;
     RECT  51.015 23.971 62.334 25.213 ;
     RECT  63.252 24.845 63.306 25.213 ;
     RECT  51.015 25.213 63.306 25.241 ;
     RECT  51.015 25.241 62.694 25.313 ;
     RECT  51.015 25.313 62.442 25.583 ;
     RECT  51.015 25.583 51.966 25.861 ;
     RECT  63.828 25.579 63.846 25.963 ;
     RECT  50.976 25.861 51.966 26.321 ;
     RECT  53.064 25.583 62.442 26.519 ;
     RECT  7.815 2.413 8.097 26.671 ;
     RECT  50.976 26.321 51.894 26.789 ;
     RECT  6.84 26.671 8.097 26.833 ;
     RECT  64.692 26.155 64.71 26.969 ;
     RECT  6.696 26.833 8.097 27.031 ;
     RECT  51.015 26.789 51.894 27.095 ;
     RECT  6.552 27.031 8.097 27.103 ;
     RECT  63.252 25.963 63.846 27.167 ;
     RECT  6.552 27.103 8.514 27.211 ;
     RECT  10.515 2.413 10.797 27.211 ;
     RECT  6.444 27.211 8.514 27.301 ;
     RECT  10.26 27.211 10.797 27.301 ;
     RECT  5.115 2.413 5.397 27.307 ;
     RECT  6.264 27.301 8.514 27.307 ;
     RECT  5.115 27.307 8.514 27.337 ;
     RECT  13.215 2.413 13.497 27.337 ;
     RECT  14.364 26.329 14.382 27.337 ;
     RECT  34.668 13.981 35.097 27.365 ;
     RECT  51.015 27.095 51.678 27.365 ;
     RECT  9.432 27.175 9.45 27.4 ;
     RECT  3.42 27.337 8.514 27.409 ;
     RECT  9.396 27.4 9.45 27.409 ;
     RECT  53.064 26.519 62.298 27.409 ;
     RECT  2.415 2.413 2.697 27.445 ;
     RECT  3.42 27.409 9.45 27.445 ;
     RECT  10.26 27.301 10.962 27.481 ;
     RECT  11.988 27.445 12.006 27.481 ;
     RECT  10.26 27.481 12.006 27.571 ;
     RECT  63.792 27.167 63.846 27.607 ;
     RECT  2.415 27.445 9.45 27.679 ;
     RECT  10.188 27.571 12.006 27.679 ;
     RECT  0.072 27.337 0.09 27.725 ;
     RECT  13.215 27.337 14.382 27.841 ;
     RECT  2.415 27.679 12.006 27.869 ;
     RECT  63.792 27.607 63.882 27.869 ;
     RECT  11.988 27.869 12.006 27.883 ;
     RECT  2.415 27.869 10.962 27.905 ;
     RECT  11.988 27.883 12.222 27.913 ;
     RECT  13.215 27.841 14.526 27.913 ;
     RECT  63.828 27.869 63.882 27.917 ;
     RECT  17.316 27.841 17.334 27.985 ;
     RECT  15.915 2.413 16.197 28.021 ;
     RECT  17.28 27.985 17.334 28.021 ;
     RECT  46.764 27.409 46.782 28.021 ;
     RECT  51.015 27.365 51.39 28.021 ;
     RECT  2.415 27.905 10.926 28.049 ;
     RECT  2.415 28.049 2.697 28.075 ;
     RECT  11.988 27.913 14.526 28.139 ;
     RECT  50.544 28.021 51.39 28.175 ;
     RECT  12.024 28.139 14.526 28.183 ;
     RECT  46.764 28.021 46.962 28.211 ;
     RECT  50.544 28.175 51.354 28.247 ;
     RECT  18.615 2.413 18.897 28.267 ;
     RECT  17.136 28.021 17.334 28.291 ;
     RECT  12.024 28.183 15.066 28.319 ;
     RECT  53.064 27.409 62.694 28.381 ;
     RECT  12.024 28.319 14.994 28.409 ;
     RECT  50.832 28.247 51.354 28.409 ;
     RECT  52.776 28.381 62.694 28.417 ;
     RECT  16.92 28.291 17.874 28.445 ;
     RECT  17.316 28.445 17.874 28.489 ;
     RECT  18.615 28.267 19.17 28.489 ;
     RECT  50.004 28.291 50.022 28.493 ;
     RECT  15.876 28.021 16.197 28.507 ;
     RECT  52.632 28.417 62.694 28.553 ;
     RECT  52.632 28.553 54.522 28.651 ;
     RECT  12.132 28.409 14.994 28.679 ;
     RECT  50.904 28.409 51.354 28.679 ;
     RECT  55.296 28.553 62.694 28.787 ;
     RECT  15.876 28.507 16.578 28.831 ;
     RECT  52.308 28.651 54.522 28.831 ;
     RECT  2.304 28.075 2.697 28.985 ;
     RECT  12.132 28.679 14.922 28.985 ;
     RECT  15.84 28.831 16.578 28.985 ;
     RECT  2.412 28.985 2.697 29.035 ;
     RECT  3.924 28.049 10.926 29.035 ;
     RECT  64.692 27.691 64.71 29.035 ;
     RECT  14.904 28.985 14.922 29.057 ;
     RECT  12.636 28.985 13.554 29.093 ;
     RECT  17.316 28.489 19.17 29.101 ;
     RECT  52.128 28.831 54.522 29.179 ;
     RECT  2.412 29.035 10.926 29.191 ;
     RECT  52.092 29.179 54.522 29.255 ;
     RECT  2.412 29.191 11.106 29.299 ;
     RECT  2.412 29.299 11.178 29.371 ;
     RECT  15.915 28.985 16.578 29.371 ;
     RECT  17.316 29.101 19.386 29.371 ;
     RECT  2.412 29.371 11.394 29.399 ;
     RECT  64.656 29.035 64.71 29.399 ;
     RECT  21.315 2.413 21.597 29.461 ;
     RECT  49.392 29.371 49.59 29.461 ;
     RECT  49.32 29.461 49.59 29.489 ;
     RECT  49.32 29.489 49.41 29.501 ;
     RECT  52.2 29.255 54.522 29.525 ;
     RECT  55.296 28.787 62.298 29.605 ;
     RECT  15.915 29.371 19.53 29.633 ;
     RECT  16.92 29.633 19.53 29.641 ;
     RECT  49.392 29.501 49.41 29.645 ;
     RECT  16.92 29.641 19.674 29.759 ;
     RECT  55.296 29.605 62.334 29.759 ;
     RECT  17.604 29.759 19.53 29.795 ;
     RECT  52.236 29.525 54.522 29.795 ;
     RECT  20.7 29.461 21.597 29.803 ;
     RECT  51.015 28.679 51.297 29.839 ;
     RECT  52.704 29.795 54.522 29.839 ;
     RECT  55.296 29.759 62.298 29.839 ;
     RECT  63.828 27.917 63.846 29.839 ;
     RECT  20.628 29.803 21.597 29.875 ;
     RECT  20.556 29.875 21.597 29.911 ;
     RECT  20.556 29.911 21.762 29.933 ;
     RECT  50.724 29.839 51.297 29.939 ;
     RECT  2.412 29.399 5.454 29.995 ;
     RECT  2.304 29.995 5.454 30.029 ;
     RECT  17.604 29.795 19.422 30.029 ;
     RECT  20.628 29.933 21.762 30.029 ;
     RECT  63.252 29.839 63.846 30.029 ;
     RECT  17.892 30.029 19.422 30.065 ;
     RECT  20.7 30.029 21.762 30.065 ;
     RECT  2.304 30.029 2.697 30.073 ;
     RECT  3.42 30.029 5.454 30.181 ;
     RECT  6.3 29.399 11.394 30.181 ;
     RECT  63.828 30.029 63.846 30.181 ;
     RECT  2.268 30.073 2.697 30.221 ;
     RECT  3.42 30.181 11.394 30.271 ;
     RECT  12.708 29.093 13.554 30.271 ;
     RECT  17.892 30.065 19.062 30.335 ;
     RECT  21.315 30.065 21.762 30.379 ;
     RECT  21.315 30.379 21.906 30.451 ;
     RECT  52.704 29.839 62.298 30.569 ;
     RECT  17.964 30.335 19.062 30.611 ;
     RECT  64.656 29.399 64.674 30.763 ;
     RECT  2.304 30.221 2.697 30.811 ;
     RECT  3.42 30.271 13.554 30.811 ;
     RECT  0.072 30.763 0.09 30.893 ;
     RECT  18.615 30.611 19.062 30.955 ;
     RECT  21.315 30.451 22.446 30.955 ;
     RECT  51.015 29.939 51.297 31.081 ;
     RECT  53.064 30.569 62.298 31.081 ;
     RECT  49.392 30.811 49.41 31.109 ;
     RECT  2.304 30.811 13.554 31.117 ;
     RECT  63.828 30.181 63.918 31.189 ;
     RECT  64.656 30.763 64.71 31.189 ;
     RECT  18.615 30.955 19.602 31.195 ;
     RECT  53.064 31.081 62.442 31.217 ;
     RECT  21.315 30.955 22.662 31.261 ;
     RECT  24.015 2.413 24.297 31.261 ;
     RECT  51.015 31.081 51.354 31.261 ;
     RECT  18.615 31.195 19.926 31.415 ;
     RECT  20.7 31.261 24.297 31.415 ;
     RECT  49.608 31.261 49.626 31.421 ;
     RECT  19.908 31.415 19.926 31.531 ;
     RECT  21.096 31.415 24.297 31.531 ;
     RECT  53.064 31.217 62.334 31.621 ;
     RECT  19.908 31.531 20.07 31.649 ;
     RECT  21.096 31.531 24.678 31.649 ;
     RECT  63.828 31.189 64.71 31.649 ;
     RECT  19.908 31.649 19.926 31.685 ;
     RECT  22.356 31.649 24.678 31.685 ;
     RECT  52.992 31.621 62.334 31.801 ;
     RECT  26.715 2.413 26.997 31.891 ;
     RECT  32.115 2.413 32.397 31.915 ;
     RECT  51.015 31.261 51.966 31.915 ;
     RECT  52.812 31.801 62.334 31.915 ;
     RECT  51.015 31.915 62.334 31.919 ;
     RECT  51.015 31.919 62.262 31.949 ;
     RECT  51.015 31.949 52.11 31.955 ;
     RECT  22.824 31.685 24.678 32.035 ;
     RECT  21.096 31.649 21.597 32.063 ;
     RECT  22.824 32.035 25.182 32.341 ;
     RECT  26.244 31.891 26.997 32.341 ;
     RECT  22.824 32.341 26.997 32.369 ;
     RECT  31.824 31.915 32.397 32.459 ;
     RECT  2.304 31.117 14.022 32.467 ;
     RECT  2.232 32.467 14.022 32.491 ;
     RECT  21.168 32.063 21.597 32.495 ;
     RECT  25.092 32.369 26.997 32.495 ;
     RECT  25.164 32.495 26.997 32.525 ;
     RECT  2.232 32.491 14.598 32.539 ;
     RECT  2.232 32.539 14.742 32.567 ;
     RECT  21.315 32.495 21.597 32.683 ;
     RECT  22.392 32.467 22.41 32.683 ;
     RECT  0.072 32.467 0.09 32.717 ;
     RECT  21.315 32.683 22.41 32.729 ;
     RECT  15.915 29.633 16.197 32.809 ;
     RECT  52.848 31.949 62.262 32.845 ;
     RECT  63.864 31.649 64.71 32.872 ;
     RECT  15.915 32.809 16.902 32.881 ;
     RECT  2.304 32.567 14.742 32.971 ;
     RECT  51.015 31.955 52.002 32.971 ;
     RECT  52.848 32.845 62.334 32.971 ;
     RECT  15.915 32.881 16.974 32.999 ;
     RECT  29.415 2.413 29.697 33.007 ;
     RECT  28.512 32.431 28.53 33.035 ;
     RECT  51.015 32.971 62.334 33.043 ;
     RECT  29.415 33.007 30.078 33.053 ;
     RECT  25.668 32.525 26.997 33.058 ;
     RECT  51.015 33.043 62.406 33.107 ;
     RECT  15.915 32.999 16.614 33.151 ;
     RECT  26.136 33.058 26.997 33.151 ;
     RECT  63.828 32.872 64.71 33.151 ;
     RECT  63.18 33.151 64.71 33.197 ;
     RECT  26.136 33.151 27.054 33.241 ;
     RECT  2.304 32.971 14.814 33.269 ;
     RECT  15.66 33.151 16.614 33.269 ;
     RECT  63.18 33.197 63.954 33.293 ;
     RECT  63.252 33.293 63.954 33.485 ;
     RECT  23.184 32.369 24.354 33.511 ;
     RECT  25.128 33.421 25.146 33.511 ;
     RECT  51.015 33.107 62.298 33.511 ;
     RECT  26.136 33.241 27.306 33.539 ;
     RECT  23.184 33.511 25.146 33.575 ;
     RECT  31.176 33.151 31.194 33.575 ;
     RECT  26.28 33.539 27.306 33.643 ;
     RECT  32.115 32.459 32.397 33.655 ;
     RECT  2.304 33.269 14.562 33.683 ;
     RECT  28.332 33.421 28.35 33.781 ;
     RECT  29.415 33.053 29.754 33.781 ;
     RECT  23.184 33.575 25.074 33.787 ;
     RECT  28.332 33.781 28.53 33.787 ;
     RECT  22.788 33.787 25.074 33.845 ;
     RECT  28.332 33.787 28.674 33.845 ;
     RECT  31.392 33.655 32.397 33.845 ;
     RECT  26.28 33.643 27.486 33.853 ;
     RECT  63.252 33.485 63.882 33.869 ;
     RECT  50.76 33.511 62.298 33.883 ;
     RECT  50.472 33.883 62.298 33.889 ;
     RECT  22.788 33.845 22.806 33.917 ;
     RECT  26.28 33.853 27.558 33.925 ;
     RECT  2.304 33.683 13.734 34.027 ;
     RECT  14.508 33.683 14.562 34.079 ;
     RECT  15.66 33.269 16.197 34.115 ;
     RECT  14.508 34.079 14.526 34.151 ;
     RECT  15.804 34.115 16.197 34.157 ;
     RECT  2.268 34.027 13.734 34.187 ;
     RECT  24.015 33.845 25.074 34.205 ;
     RECT  15.915 34.157 16.197 34.231 ;
     RECT  26.28 33.925 27.63 34.349 ;
     RECT  25.056 34.205 25.074 34.385 ;
     RECT  28.44 33.845 28.674 34.385 ;
     RECT  63.252 33.869 63.846 34.445 ;
     RECT  50.004 33.889 62.298 34.465 ;
     RECT  15.915 34.231 16.758 34.501 ;
     RECT  29.415 33.781 29.79 34.501 ;
     RECT  2.304 34.187 13.734 34.619 ;
     RECT  18.615 31.415 18.897 34.627 ;
     RECT  21.315 32.729 21.597 34.651 ;
     RECT  17.856 34.501 17.874 34.655 ;
     RECT  18.612 34.627 18.897 34.685 ;
     RECT  15.915 34.501 16.83 34.735 ;
     RECT  31.536 33.845 32.397 34.735 ;
     RECT  18.615 34.685 18.897 34.771 ;
     RECT  63.252 34.445 63.27 34.795 ;
     RECT  0.072 34.735 0.09 34.829 ;
     RECT  29.415 34.501 29.97 34.861 ;
     RECT  34.74 27.365 35.097 34.861 ;
     RECT  15.915 34.735 16.902 34.889 ;
     RECT  31.284 34.735 32.397 34.891 ;
     RECT  33.12 34.591 33.138 34.891 ;
     RECT  15.915 34.889 16.758 34.925 ;
     RECT  18.615 34.771 19.566 34.925 ;
     RECT  31.284 34.891 33.138 34.925 ;
     RECT  50.004 34.465 62.334 34.987 ;
     RECT  63.216 34.795 63.27 34.987 ;
     RECT  21.204 34.651 21.597 35.005 ;
     RECT  19.944 35.005 21.597 35.041 ;
     RECT  28.512 34.385 28.674 35.041 ;
     RECT  29.415 34.861 30.258 35.041 ;
     RECT  34.236 34.861 35.097 35.041 ;
     RECT  46.944 28.211 46.962 35.041 ;
     RECT  19.944 35.041 22.194 35.159 ;
     RECT  28.512 35.041 30.258 35.159 ;
     RECT  50.004 34.987 63.27 35.179 ;
     RECT  19.944 35.159 19.962 35.195 ;
     RECT  20.808 35.159 22.194 35.195 ;
     RECT  26.715 34.349 27.63 35.195 ;
     RECT  21.204 35.195 22.194 35.231 ;
     RECT  46.764 35.041 46.962 35.231 ;
     RECT  50.004 35.179 63.882 35.231 ;
     RECT  50.004 35.231 62.334 35.275 ;
     RECT  32.115 34.925 33.138 35.311 ;
     RECT  32.115 35.311 33.246 35.357 ;
     RECT  22.32 35.311 23.202 35.419 ;
     RECT  24.015 34.205 24.297 35.419 ;
     RECT  2.304 34.619 13.698 35.453 ;
     RECT  21.204 35.231 21.597 35.453 ;
     RECT  22.32 35.419 24.297 35.465 ;
     RECT  28.512 35.159 28.53 35.465 ;
     RECT  33.228 35.357 33.246 35.465 ;
     RECT  49.428 35.275 62.334 35.549 ;
     RECT  33.984 35.041 35.097 35.581 ;
     RECT  33.444 35.581 35.19 35.699 ;
     RECT  22.464 35.465 24.297 35.735 ;
     RECT  25.668 35.707 25.686 35.744 ;
     RECT  23.184 35.735 24.297 35.779 ;
     RECT  23.184 35.779 24.462 35.851 ;
     RECT  26.715 35.195 27.054 35.851 ;
     RECT  33.948 35.699 35.19 35.851 ;
     RECT  23.184 35.851 24.534 35.969 ;
     RECT  25.848 35.851 25.866 35.969 ;
     RECT  23.184 35.969 23.202 36.005 ;
     RECT  24.015 35.969 24.534 36.005 ;
     RECT  29.415 35.159 30.258 36.005 ;
     RECT  33.948 35.851 35.658 36.005 ;
     RECT  36.684 35.851 36.702 36.005 ;
     RECT  14.832 35.947 14.85 36.077 ;
     RECT  63.252 35.231 63.882 36.077 ;
     RECT  26.712 35.851 27.054 36.121 ;
     RECT  31.284 35.851 31.302 36.121 ;
     RECT  32.115 35.357 32.397 36.121 ;
     RECT  34.632 36.005 35.658 36.121 ;
     RECT  37.515 2.413 37.797 36.121 ;
     RECT  50.004 35.549 62.334 36.121 ;
     RECT  2.304 35.453 3.618 36.139 ;
     RECT  31.284 36.121 32.49 36.211 ;
     RECT  24.015 36.005 24.462 36.239 ;
     RECT  26.676 36.121 27.054 36.239 ;
     RECT  50.004 36.121 62.442 36.239 ;
     RECT  2.268 36.139 3.618 36.247 ;
     RECT  4.392 35.453 13.698 36.247 ;
     RECT  24.015 36.239 24.354 36.275 ;
     RECT  26.676 36.239 26.997 36.275 ;
     RECT  64.692 33.197 64.71 36.283 ;
     RECT  31.284 36.211 33.066 36.311 ;
     RECT  63.864 36.077 63.882 36.319 ;
     RECT  64.656 36.283 64.71 36.319 ;
     RECT  2.268 36.247 13.698 36.347 ;
     RECT  34.632 36.121 35.91 36.481 ;
     RECT  63.864 36.319 64.71 36.509 ;
     RECT  63.864 36.509 64.674 36.557 ;
     RECT  2.304 36.347 13.698 36.581 ;
     RECT  31.284 36.311 32.397 36.589 ;
     RECT  28.224 36.619 28.242 36.625 ;
     RECT  50.004 36.239 62.262 36.625 ;
     RECT  2.304 36.581 13.497 36.689 ;
     RECT  18.615 34.925 18.897 36.751 ;
     RECT  28.224 36.625 28.386 36.779 ;
     RECT  34.632 36.481 36.018 36.779 ;
     RECT  2.304 36.689 5.49 36.815 ;
     RECT  28.224 36.779 28.242 36.815 ;
     RECT  30.78 36.589 32.397 36.815 ;
     RECT  34.632 36.779 35.37 36.815 ;
     RECT  0.072 36.715 0.09 36.845 ;
     RECT  18.615 36.751 19.062 36.859 ;
     RECT  36.756 36.121 37.797 36.887 ;
     RECT  63.864 36.557 63.954 36.907 ;
     RECT  29.415 36.005 29.697 36.931 ;
     RECT  30.78 36.815 30.798 36.931 ;
     RECT  38.7 36.661 38.79 36.931 ;
     RECT  49.896 36.625 62.262 36.931 ;
     RECT  38.52 36.931 38.826 37.021 ;
     RECT  6.372 36.689 13.497 37.049 ;
     RECT  18.396 36.859 19.062 37.049 ;
     RECT  29.304 36.931 30.798 37.049 ;
     RECT  38.52 37.021 39.402 37.049 ;
     RECT  29.304 37.049 30.33 37.085 ;
     RECT  37.188 36.887 37.797 37.085 ;
     RECT  38.7 37.049 39.402 37.085 ;
     RECT  63.828 36.907 63.954 37.099 ;
     RECT  6.516 37.049 13.497 37.193 ;
     RECT  34.815 36.815 35.37 37.193 ;
     RECT  49.428 36.931 62.262 37.291 ;
     RECT  38.808 37.085 39.402 37.319 ;
     RECT  63.792 37.099 63.954 37.325 ;
     RECT  2.304 36.815 5.397 37.355 ;
     RECT  29.376 37.085 29.697 37.355 ;
     RECT  31.788 36.815 32.397 37.355 ;
     RECT  40.215 2.413 40.497 37.435 ;
     RECT  49.428 37.291 62.298 37.435 ;
     RECT  49.428 37.435 62.73 37.517 ;
     RECT  2.415 37.355 5.397 37.589 ;
     RECT  38.808 37.319 38.97 37.589 ;
     RECT  36.216 37.201 36.342 37.597 ;
     RECT  48.315 2.413 48.597 37.597 ;
     RECT  49.428 37.517 62.478 37.597 ;
     RECT  2.415 37.589 3.69 37.625 ;
     RECT  4.644 37.589 5.397 37.625 ;
     RECT  34.815 37.193 35.19 37.625 ;
     RECT  38.808 37.589 38.826 37.625 ;
     RECT  48.315 37.597 62.478 37.625 ;
     RECT  6.624 37.193 13.497 37.661 ;
     RECT  31.896 37.355 32.397 37.675 ;
     RECT  33.84 37.051 33.858 37.675 ;
     RECT  35.928 37.597 36.342 37.741 ;
     RECT  6.768 37.661 13.497 37.769 ;
     RECT  7.02 37.769 13.497 37.859 ;
     RECT  35.928 37.741 36.45 37.895 ;
     RECT  7.02 37.859 12.15 37.931 ;
     RECT  13.104 37.859 13.497 37.939 ;
     RECT  7.236 37.931 12.15 37.967 ;
     RECT  15.915 34.925 16.197 37.975 ;
     RECT  31.896 37.675 32.526 38.011 ;
     RECT  33.336 37.675 33.858 38.011 ;
     RECT  34.815 37.625 35.097 38.011 ;
     RECT  37.515 37.085 37.797 38.011 ;
     RECT  39.744 37.435 40.497 38.011 ;
     RECT  7.344 37.967 12.15 38.039 ;
     RECT  13.104 37.939 13.698 38.107 ;
     RECT  31.896 38.011 35.097 38.129 ;
     RECT  39.744 38.011 41.202 38.137 ;
     RECT  31.896 38.129 32.526 38.155 ;
     RECT  33.336 38.129 35.097 38.165 ;
     RECT  39.744 38.137 41.67 38.165 ;
     RECT  49.86 37.625 62.478 38.165 ;
     RECT  31.824 38.155 32.526 38.189 ;
     RECT  41.22 38.165 41.67 38.189 ;
     RECT  13.104 38.107 14.13 38.237 ;
     RECT  15.915 37.975 16.47 38.237 ;
     RECT  17.424 38.203 17.442 38.281 ;
     RECT  36 37.895 36.45 38.281 ;
     RECT  37.368 38.011 37.797 38.281 ;
     RECT  42.915 2.413 43.197 38.281 ;
     RECT  31.824 38.189 32.397 38.371 ;
     RECT  33.336 38.165 33.678 38.399 ;
     RECT  48.315 37.625 48.978 38.399 ;
     RECT  31.788 38.371 32.397 38.429 ;
     RECT  42.624 38.281 43.197 38.435 ;
     RECT  63.792 37.325 63.846 38.443 ;
     RECT  33.624 38.399 33.642 38.471 ;
     RECT  14.868 38.281 14.886 38.551 ;
     RECT  17.208 38.281 17.478 38.551 ;
     RECT  38.52 38.011 38.538 38.551 ;
     RECT  7.815 38.039 12.15 38.579 ;
     RECT  14.868 38.551 15.066 38.641 ;
     RECT  15.915 38.237 16.197 38.641 ;
     RECT  36 38.281 37.797 38.641 ;
     RECT  38.52 38.551 38.718 38.641 ;
     RECT  7.815 38.579 8.262 38.669 ;
     RECT  9.144 38.579 12.15 38.669 ;
     RECT  31.824 38.429 32.397 38.669 ;
     RECT  63.252 38.443 63.846 38.669 ;
     RECT  36 38.641 38.718 38.705 ;
     RECT  49.86 38.165 62.442 38.713 ;
     RECT  9.648 38.669 9.666 38.765 ;
     RECT  37.08 38.705 38.718 38.765 ;
     RECT  17.208 38.551 17.586 38.785 ;
     RECT  18.615 37.049 18.897 38.821 ;
     RECT  37.332 38.765 38.718 38.821 ;
     RECT  37.332 38.821 38.898 38.939 ;
     RECT  39.744 38.165 40.497 38.947 ;
     RECT  10.44 38.669 12.15 38.975 ;
     RECT  37.332 38.939 38.43 38.975 ;
     RECT  18.615 38.821 19.026 39.067 ;
     RECT  37.476 38.975 38.322 39.083 ;
     RECT  13.104 38.237 13.878 39.091 ;
     RECT  14.868 38.641 16.197 39.091 ;
     RECT  16.992 38.785 17.586 39.091 ;
     RECT  21.315 35.453 21.597 39.091 ;
     RECT  39.276 38.947 40.497 39.091 ;
     RECT  41.22 38.189 41.49 39.091 ;
     RECT  42.768 38.435 43.197 39.091 ;
     RECT  39.276 39.091 41.706 39.119 ;
     RECT  37.515 39.083 38.322 39.209 ;
     RECT  39.348 39.119 41.706 39.209 ;
     RECT  14.868 39.091 17.586 39.245 ;
     RECT  39.492 39.209 41.706 39.245 ;
     RECT  63.252 38.669 63.27 39.281 ;
     RECT  37.515 39.209 38.178 39.293 ;
     RECT  17.172 39.245 17.586 39.307 ;
     RECT  18.432 39.067 19.026 39.307 ;
     RECT  20.268 39.091 21.69 39.361 ;
     RECT  22.608 39.181 22.626 39.361 ;
     RECT  42.768 39.091 43.398 39.361 ;
     RECT  49.608 38.713 62.442 39.361 ;
     RECT  48.315 38.399 48.597 39.403 ;
     RECT  49.608 39.361 62.514 39.403 ;
     RECT  14.868 39.245 16.398 39.479 ;
     RECT  17.172 39.307 19.026 39.479 ;
     RECT  48.315 39.403 62.694 39.479 ;
     RECT  10.44 38.975 11.43 39.515 ;
     RECT  39.78 39.245 41.706 39.515 ;
     RECT  42.696 39.361 43.398 39.515 ;
     RECT  12.312 39.091 14.022 39.631 ;
     RECT  14.868 39.479 16.362 39.631 ;
     RECT  17.208 39.479 19.026 39.631 ;
     RECT  42.768 39.515 43.398 39.631 ;
     RECT  44.46 39.361 44.478 39.631 ;
     RECT  10.44 39.515 10.797 39.659 ;
     RECT  46.944 35.231 46.962 39.659 ;
     RECT  17.208 39.631 19.062 39.721 ;
     RECT  20.268 39.361 22.626 39.721 ;
     RECT  39.888 39.515 41.706 39.739 ;
     RECT  39.888 39.739 41.958 39.749 ;
     RECT  12.312 39.631 16.362 39.785 ;
     RECT  64.692 37.675 64.71 39.787 ;
     RECT  17.208 39.721 19.422 39.821 ;
     RECT  40.212 39.749 41.958 39.857 ;
     RECT  42.768 39.631 43.47 39.901 ;
     RECT  44.244 39.631 44.694 39.901 ;
     RECT  12.528 39.785 16.362 39.917 ;
     RECT  24.015 36.275 24.297 39.991 ;
     RECT  48.315 39.479 62.622 40.091 ;
     RECT  63.9 40.099 63.918 40.165 ;
     RECT  23.94 39.991 24.297 40.171 ;
     RECT  40.215 39.857 41.958 40.171 ;
     RECT  42.768 39.901 44.694 40.171 ;
     RECT  45.615 2.413 45.897 40.171 ;
     RECT  63.864 40.165 63.918 40.205 ;
     RECT  12.528 39.917 14.022 40.289 ;
     RECT  14.796 39.917 16.362 40.289 ;
     RECT  42.768 40.171 46.134 40.289 ;
     RECT  42.768 40.289 43.434 40.301 ;
     RECT  14.796 40.289 15.102 40.325 ;
     RECT  17.208 39.821 19.386 40.325 ;
     RECT  63.9 40.205 63.918 40.363 ;
     RECT  64.656 39.787 64.71 40.363 ;
     RECT  23.832 40.171 24.39 40.405 ;
     RECT  20.196 39.721 23.058 40.441 ;
     RECT  23.832 40.405 24.714 40.441 ;
     RECT  26.715 36.275 26.997 40.441 ;
     RECT  14.94 40.325 15.102 40.559 ;
     RECT  15.84 40.289 16.362 40.559 ;
     RECT  63.9 40.363 64.71 40.589 ;
     RECT  14.94 40.559 14.958 40.595 ;
     RECT  15.84 40.559 16.197 40.595 ;
     RECT  20.16 40.441 25.146 40.595 ;
     RECT  40.215 40.171 42.03 40.595 ;
     RECT  26.064 40.441 26.997 40.675 ;
     RECT  17.352 40.325 19.386 40.711 ;
     RECT  20.16 40.595 22.41 40.711 ;
     RECT  23.148 40.595 25.146 40.711 ;
     RECT  25.956 40.675 26.997 40.711 ;
     RECT  44.208 40.289 46.134 40.711 ;
     RECT  46.944 40.441 46.962 40.711 ;
     RECT  48.315 40.091 62.514 40.739 ;
     RECT  40.215 40.595 41.202 40.829 ;
     RECT  17.352 40.711 22.41 40.865 ;
     RECT  44.208 40.711 47.106 40.865 ;
     RECT  18.072 40.865 22.41 40.901 ;
     RECT  42.768 40.301 43.197 40.909 ;
     RECT  18.072 40.901 19.134 40.973 ;
     RECT  23.148 40.711 26.997 40.981 ;
     RECT  18.216 40.973 19.134 41.009 ;
     RECT  42.444 40.909 43.197 41.009 ;
     RECT  23.148 40.981 27.27 41.035 ;
     RECT  36.504 40.981 36.522 41.071 ;
     RECT  23.148 41.035 27.99 41.099 ;
     RECT  35.892 41.071 36.522 41.117 ;
     RECT  63.864 40.981 63.882 41.131 ;
     RECT  23.148 41.099 27.27 41.135 ;
     RECT  44.316 40.865 47.106 41.135 ;
     RECT  42.768 41.009 43.197 41.207 ;
     RECT  38.664 41.083 38.79 41.213 ;
     RECT  42.84 41.207 43.197 41.213 ;
     RECT  29.415 37.355 29.697 41.215 ;
     RECT  44.352 41.135 47.106 41.215 ;
     RECT  48.315 40.739 62.334 41.215 ;
     RECT  29.124 41.215 29.697 41.251 ;
     RECT  36.504 41.117 36.522 41.309 ;
     RECT  63.828 41.131 63.882 41.369 ;
     RECT  28.908 41.251 29.754 41.405 ;
     RECT  20.052 40.901 22.41 41.521 ;
     RECT  23.148 41.135 25.326 41.521 ;
     RECT  44.352 41.215 62.334 41.611 ;
     RECT  18.615 41.009 19.134 41.639 ;
     RECT  18.615 41.639 18.99 41.675 ;
     RECT  20.052 41.521 25.326 41.675 ;
     RECT  28.152 41.521 28.17 41.675 ;
     RECT  42.876 41.213 43.197 41.675 ;
     RECT  44.352 41.611 62.406 41.881 ;
     RECT  20.196 41.675 20.394 41.909 ;
     RECT  21.315 41.675 25.326 41.909 ;
     RECT  26.064 41.135 27.09 41.917 ;
     RECT  20.196 41.909 20.214 41.945 ;
     RECT  21.315 41.909 22.122 41.945 ;
     RECT  22.932 41.909 25.326 41.945 ;
     RECT  44.352 41.881 62.694 41.945 ;
     RECT  45 41.945 62.694 41.981 ;
     RECT  63.864 41.369 63.882 41.989 ;
     RECT  64.62 40.589 64.71 41.989 ;
     RECT  45 41.981 62.622 42.017 ;
     RECT  29.376 41.405 29.754 42.025 ;
     RECT  63.864 41.989 64.71 42.091 ;
     RECT  23.22 41.945 25.326 42.151 ;
     RECT  26.064 41.917 27.594 42.151 ;
     RECT  29.376 42.025 30.366 42.151 ;
     RECT  32.115 38.669 32.397 42.151 ;
     RECT  23.22 42.151 27.594 42.179 ;
     RECT  45 42.017 62.298 42.179 ;
     RECT  34.815 38.165 35.097 42.187 ;
     RECT  23.832 42.179 27.594 42.215 ;
     RECT  25.056 42.215 27.594 42.221 ;
     RECT  33.552 42.151 33.57 42.259 ;
     RECT  28.584 42.061 28.602 42.295 ;
     RECT  29.376 42.151 30.798 42.295 ;
     RECT  33.516 42.259 33.57 42.331 ;
     RECT  26.496 42.221 27.594 42.421 ;
     RECT  28.584 42.295 30.798 42.421 ;
     RECT  45.615 42.179 62.298 42.449 ;
     RECT  45.615 42.449 62.262 42.485 ;
     RECT  26.496 42.421 27.63 42.521 ;
     RECT  23.832 42.215 24.297 42.557 ;
     RECT  28.584 42.421 30.834 42.601 ;
     RECT  31.68 42.151 32.397 42.601 ;
     RECT  33.408 42.331 33.57 42.601 ;
     RECT  37.515 39.293 37.797 42.601 ;
     RECT  63.828 42.091 64.71 42.667 ;
     RECT  25.056 42.221 25.65 42.719 ;
     RECT  33.156 42.601 33.57 42.727 ;
     RECT  37.224 42.601 37.797 42.749 ;
     RECT  28.044 42.601 32.397 42.755 ;
     RECT  34.815 42.187 35.694 42.871 ;
     RECT  63.792 42.667 64.71 42.893 ;
     RECT  25.092 42.719 25.65 42.989 ;
     RECT  64.656 42.893 64.71 43.061 ;
     RECT  26.496 42.521 26.997 43.141 ;
     RECT  34.815 42.871 35.91 43.141 ;
     RECT  64.692 43.061 64.71 43.169 ;
     RECT  63.792 42.893 63.918 43.231 ;
     RECT  47.016 42.485 62.262 43.277 ;
     RECT  26.424 43.141 26.997 43.295 ;
     RECT  34.488 43.141 36.306 43.295 ;
     RECT  33.12 42.727 33.57 43.411 ;
     RECT  34.815 43.295 36.306 43.411 ;
     RECT  38.844 43.375 38.862 43.411 ;
     RECT  37.515 42.749 37.797 43.483 ;
     RECT  38.844 43.411 39.042 43.529 ;
     RECT  28.368 42.755 30.906 43.565 ;
     RECT  39.024 43.529 39.042 43.565 ;
     RECT  34.815 43.411 36.558 43.609 ;
     RECT  37.515 43.483 37.926 43.609 ;
     RECT  47.556 43.277 62.262 43.645 ;
     RECT  63.288 43.231 63.918 43.661 ;
     RECT  28.368 43.565 30.402 43.681 ;
     RECT  31.788 42.755 32.397 43.681 ;
     RECT  28.224 43.681 30.402 43.709 ;
     RECT  31.284 43.681 32.397 43.771 ;
     RECT  33.12 43.411 34.002 43.771 ;
     RECT  40.215 40.829 40.497 43.771 ;
     RECT  28.224 43.709 28.386 43.799 ;
     RECT  29.232 43.709 30.402 43.799 ;
     RECT  31.284 43.771 34.002 43.799 ;
     RECT  34.815 43.609 37.926 43.799 ;
     RECT  47.556 43.645 62.334 43.799 ;
     RECT  28.224 43.799 28.242 43.835 ;
     RECT  37.404 43.799 37.926 43.835 ;
     RECT  47.556 43.799 47.574 43.835 ;
     RECT  39.096 43.681 39.114 43.843 ;
     RECT  40.215 43.771 41.022 43.843 ;
     RECT  42.915 41.675 43.197 43.843 ;
     RECT  37.44 43.835 37.926 43.951 ;
     RECT  63.288 43.661 63.882 44.045 ;
     RECT  48.315 43.799 62.334 44.069 ;
     RECT  29.232 43.799 30.294 44.105 ;
     RECT  31.284 43.799 33.93 44.105 ;
     RECT  42.48 43.843 44.262 44.105 ;
     RECT  49.392 44.069 62.334 44.203 ;
     RECT  31.392 44.105 33.93 44.213 ;
     RECT  49.392 44.203 62.694 44.249 ;
     RECT  31.392 44.213 33.138 44.339 ;
     RECT  49.392 44.249 62.334 44.339 ;
     RECT  31.392 44.339 32.706 44.375 ;
     RECT  33.912 44.213 33.93 44.375 ;
     RECT  34.815 43.799 36.45 44.375 ;
     RECT  39.096 43.843 41.022 44.375 ;
     RECT  42.732 44.105 44.262 44.383 ;
     RECT  49.392 44.339 62.298 44.411 ;
     RECT  37.44 43.951 38.178 44.443 ;
     RECT  45.615 42.485 45.897 44.443 ;
     RECT  36.432 44.375 36.45 44.477 ;
     RECT  42.732 44.383 44.478 44.491 ;
     RECT  45.615 44.443 46.062 44.491 ;
     RECT  37.44 44.443 38.502 44.581 ;
     RECT  64.656 44.395 64.674 44.587 ;
     RECT  34.815 44.375 35.55 44.609 ;
     RECT  31.392 44.375 32.526 44.645 ;
     RECT  45.432 44.491 46.062 44.725 ;
     RECT  34.815 44.609 35.514 44.761 ;
     RECT  39.384 44.375 41.022 44.761 ;
     RECT  63.864 44.045 63.882 44.761 ;
     RECT  64.62 44.587 64.674 44.761 ;
     RECT  34.308 44.761 35.514 44.879 ;
     RECT  34.308 44.879 35.37 44.915 ;
     RECT  36.468 44.581 38.502 44.915 ;
     RECT  39.384 44.761 41.706 44.915 ;
     RECT  63.864 44.761 64.674 44.971 ;
     RECT  42.732 44.491 44.622 44.995 ;
     RECT  45.432 44.725 46.566 44.995 ;
     RECT  42.732 44.995 46.566 45.031 ;
     RECT  36.684 44.915 38.502 45.121 ;
     RECT  36.684 45.121 38.574 45.149 ;
     RECT  42.732 45.031 47.394 45.163 ;
     RECT  63.864 44.971 64.71 45.163 ;
     RECT  36.684 45.149 36.702 45.185 ;
     RECT  37.515 45.149 38.574 45.185 ;
     RECT  38.556 45.185 38.574 45.197 ;
     RECT  39.492 44.915 41.706 45.301 ;
     RECT  42.48 45.163 47.394 45.301 ;
     RECT  48.315 44.069 48.597 45.391 ;
     RECT  39.492 45.301 47.394 45.455 ;
     RECT  48.24 45.391 48.597 45.535 ;
     RECT  49.608 44.411 62.298 45.535 ;
     RECT  41.544 45.455 47.394 45.571 ;
     RECT  48.168 45.535 62.298 45.571 ;
     RECT  63.252 45.163 64.71 45.599 ;
     RECT  39.492 45.455 40.77 45.725 ;
     RECT  63.252 45.599 63.954 45.773 ;
     RECT  41.544 45.571 62.298 45.805 ;
     RECT  39.564 45.725 40.497 45.959 ;
     RECT  41.544 45.805 62.982 45.995 ;
     RECT  41.868 45.995 62.982 46.265 ;
     RECT  42.192 46.265 62.982 46.499 ;
     RECT  42.192 46.499 43.938 46.535 ;
     RECT  63.864 45.773 63.954 46.541 ;
     RECT  64.692 45.599 64.71 46.699 ;
     RECT  44.712 46.499 62.982 46.841 ;
     RECT  63.864 46.541 63.882 46.891 ;
     RECT  64.656 46.699 64.71 46.949 ;
     RECT  42.804 46.535 43.938 47.039 ;
     RECT  44.712 46.841 62.514 47.039 ;
     RECT  44.712 47.039 62.442 47.075 ;
     RECT  63.828 46.891 63.882 47.083 ;
     RECT  45.072 47.075 62.442 47.111 ;
     RECT  42.915 47.039 43.938 47.309 ;
     RECT  42.915 47.309 43.506 47.345 ;
     RECT  45.072 47.111 62.37 47.345 ;
     RECT  42.915 47.345 43.362 47.453 ;
     RECT  45.504 47.345 62.37 47.579 ;
     RECT  45.504 47.579 45.897 47.615 ;
     RECT  47.016 47.579 48.597 47.885 ;
     RECT  49.32 47.579 62.37 47.891 ;
     RECT  49.752 47.891 62.37 48.043 ;
     RECT  63.252 47.083 63.882 48.043 ;
     RECT  49.752 48.043 63.882 48.119 ;
     RECT  50.112 48.119 63.882 48.127 ;
     RECT  64.692 46.949 64.71 48.127 ;
     RECT  47.88 47.885 48.597 48.269 ;
     RECT  50.112 48.127 64.71 48.425 ;
     RECT  50.508 48.425 64.71 48.461 ;
     RECT  50.652 48.461 64.71 48.767 ;
     RECT  50.904 48.767 64.71 49.037 ;
     RECT  50.904 49.037 62.154 49.271 ;
     RECT  63.252 49.037 64.71 49.421 ;
     RECT  63.252 49.421 63.954 49.577 ;
     RECT  51.015 49.271 62.154 49.775 ;
     RECT  52.092 49.775 62.154 49.891 ;
     RECT  52.092 49.891 62.334 50.045 ;
     RECT  51.015 49.775 51.354 50.279 ;
     RECT  52.092 50.045 62.298 50.279 ;
     RECT  52.452 50.279 62.298 50.315 ;
     RECT  63.828 49.577 63.954 50.347 ;
     RECT  63.792 50.347 63.954 50.387 ;
     RECT  52.488 50.315 62.298 50.459 ;
     RECT  52.74 50.459 62.298 50.819 ;
     RECT  63.828 50.387 63.954 51.149 ;
     RECT  64.692 49.421 64.71 51.499 ;
     RECT  52.776 50.819 62.262 51.665 ;
     RECT  63.828 51.149 63.882 51.725 ;
     RECT  63.828 51.725 63.846 51.737 ;
     RECT  53.604 51.665 62.262 51.745 ;
     RECT  52.776 51.665 52.794 51.869 ;
     RECT  53.604 51.745 62.334 51.899 ;
     RECT  64.656 51.499 64.71 52.007 ;
     RECT  63.252 52.075 63.306 52.267 ;
     RECT  53.604 51.899 62.226 52.349 ;
     RECT  53.715 52.349 62.226 52.439 ;
     RECT  55.656 52.439 62.226 52.493 ;
     RECT  63.216 52.267 63.306 52.493 ;
     RECT  64.692 52.007 64.71 52.817 ;
     RECT  55.764 52.493 62.226 52.861 ;
     RECT  53.715 52.439 54.846 52.979 ;
     RECT  64.656 52.843 64.674 53.035 ;
     RECT  55.764 52.861 62.334 53.131 ;
     RECT  54.828 52.979 54.846 53.249 ;
     RECT  55.764 53.131 62.442 53.365 ;
     RECT  63.216 52.493 63.27 53.365 ;
     RECT  64.62 53.035 64.674 53.419 ;
     RECT  55.764 53.365 63.27 53.429 ;
     RECT  55.764 53.429 62.514 53.591 ;
     RECT  64.548 53.419 64.674 53.611 ;
     RECT  63.252 53.429 63.27 53.941 ;
     RECT  55.764 53.591 62.442 53.981 ;
     RECT  64.512 53.611 64.674 53.995 ;
     RECT  56.196 53.981 62.442 54.059 ;
     RECT  63.252 53.941 63.306 54.221 ;
     RECT  64.476 53.995 64.674 54.379 ;
     RECT  56.196 54.059 62.37 54.715 ;
     RECT  64.476 54.379 64.71 55.139 ;
     RECT  55.98 54.715 62.37 55.175 ;
     RECT  63.252 54.221 63.27 55.339 ;
     RECT  56.304 55.175 62.37 55.915 ;
     RECT  63.252 55.339 63.846 55.915 ;
     RECT  64.584 55.139 64.71 55.915 ;
     RECT  63.252 55.915 64.71 55.949 ;
     RECT  56.052 55.915 62.37 55.955 ;
     RECT  56.415 55.955 62.37 56.255 ;
     RECT  58.068 56.255 62.37 56.371 ;
     RECT  63.252 55.949 63.27 56.683 ;
     RECT  64.476 55.949 64.71 56.683 ;
     RECT  56.415 56.255 57.258 57.029 ;
     RECT  63.252 56.683 64.71 57.029 ;
     RECT  56.415 57.029 56.934 57.065 ;
     RECT  58.068 56.371 62.406 57.065 ;
     RECT  58.716 57.065 62.406 57.335 ;
     RECT  63.252 57.029 63.27 57.407 ;
     RECT  64.476 57.029 64.71 57.479 ;
     RECT  64.656 57.479 64.71 57.569 ;
     RECT  58.824 57.335 62.406 57.713 ;
     RECT  64.656 57.569 64.674 57.839 ;
     RECT  58.968 57.713 62.406 57.875 ;
     RECT  58.968 57.875 62.097 58.109 ;
     RECT  59.076 58.109 60.426 58.145 ;
     RECT  59.076 58.145 60.174 58.379 ;
     RECT  59.115 58.379 60.102 58.415 ;
     RECT  59.115 58.415 60.03 58.523 ;
     RECT  2.415 37.625 2.697 62.387 ;
     RECT  5.115 37.625 5.397 62.387 ;
     RECT  7.815 38.669 8.097 62.387 ;
     RECT  10.515 39.659 10.797 62.387 ;
     RECT  13.215 40.289 13.497 62.387 ;
     RECT  15.915 40.595 16.197 62.387 ;
     RECT  18.615 41.675 18.897 62.387 ;
     RECT  21.315 41.945 21.597 62.387 ;
     RECT  24.015 42.557 24.297 62.387 ;
     RECT  26.715 43.295 26.997 62.387 ;
     RECT  29.415 44.105 29.697 62.387 ;
     RECT  32.115 44.645 32.397 62.387 ;
     RECT  34.815 44.915 35.097 62.387 ;
     RECT  37.515 45.185 37.797 62.387 ;
     RECT  40.215 45.959 40.497 62.387 ;
     RECT  42.915 47.453 43.197 62.387 ;
     RECT  45.615 47.615 45.897 62.387 ;
     RECT  48.315 48.269 48.597 62.387 ;
     RECT  51.015 50.279 51.297 62.387 ;
     RECT  53.715 52.979 53.997 62.387 ;
     RECT  56.415 57.065 56.697 62.387 ;
     RECT  59.115 58.523 59.397 62.387 ;
     RECT  61.815 58.109 62.097 62.387 ;
     RECT  2.415 62.387 2.505 62.657 ;
     RECT  5.115 62.387 5.205 62.657 ;
     RECT  7.815 62.387 7.905 62.657 ;
     RECT  10.515 62.387 10.605 62.657 ;
     RECT  13.215 62.387 13.305 62.657 ;
     RECT  15.915 62.387 16.005 62.657 ;
     RECT  18.615 62.387 18.705 62.657 ;
     RECT  21.315 62.387 21.405 62.657 ;
     RECT  24.015 62.387 24.105 62.657 ;
     RECT  26.715 62.387 26.805 62.657 ;
     RECT  29.415 62.387 29.505 62.657 ;
     RECT  32.115 62.387 32.205 62.657 ;
     RECT  34.815 62.387 34.905 62.657 ;
     RECT  37.515 62.387 37.605 62.657 ;
     RECT  40.215 62.387 40.305 62.657 ;
     RECT  42.915 62.387 43.005 62.657 ;
     RECT  45.615 62.387 45.705 62.657 ;
     RECT  48.315 62.387 48.405 62.657 ;
     RECT  51.015 62.387 51.105 62.657 ;
     RECT  53.715 62.387 53.805 62.657 ;
     RECT  56.415 62.387 56.505 62.657 ;
     RECT  59.115 62.387 59.205 62.657 ;
     RECT  61.815 62.387 61.905 62.657 ;
    LAYER M4 ;
     RECT  0.06 27.696 0.101 37.128 ;
     RECT  0.101 27.888 2.408 37.128 ;
     RECT  2.408 2.148 2.512 62.652 ;
     RECT  2.512 2.418 2.704 62.382 ;
     RECT  2.704 29.04 2.765 29.832 ;
     RECT  2.704 33.648 2.765 33.672 ;
     RECT  2.765 29.04 3.017 29.64 ;
     RECT  2.704 35.184 3.017 35.208 ;
     RECT  2.704 30.816 3.125 31.176 ;
     RECT  3.017 29.04 3.233 29.064 ;
     RECT  2.704 36.816 3.557 36.84 ;
     RECT  3.125 30.816 4.165 30.84 ;
     RECT  4.165 30.816 4.381 31.224 ;
     RECT  4.381 30.816 4.525 31.368 ;
     RECT  3.805 37.344 4.705 37.368 ;
     RECT  4.525 30.576 5.065 31.368 ;
     RECT  5.065 30.576 5.101 31.512 ;
     RECT  4.561 28.272 5.108 28.296 ;
     RECT  5.101 30.576 5.108 32.28 ;
     RECT  4.273 35.424 5.108 35.448 ;
     RECT  4.705 36.528 5.108 37.368 ;
     RECT  5.108 2.148 5.212 62.652 ;
     RECT  5.212 2.418 5.404 62.382 ;
     RECT  5.404 30.144 5.555 36.552 ;
     RECT  5.555 30.576 5.609 36.552 ;
     RECT  5.609 30.816 5.699 36.552 ;
     RECT  5.699 30.816 5.869 36.504 ;
     RECT  5.404 27.312 5.897 29.112 ;
     RECT  5.869 30.816 6.401 35.976 ;
     RECT  6.401 30.816 6.437 31.704 ;
     RECT  6.401 32.736 6.545 35.976 ;
     RECT  5.897 27.312 6.649 27.912 ;
     RECT  5.897 29.088 6.649 29.112 ;
     RECT  6.649 29.088 6.689 29.496 ;
     RECT  6.437 31.104 7.621 31.704 ;
     RECT  7.405 37.584 7.765 37.608 ;
     RECT  6.649 27.072 7.808 27.912 ;
     RECT  6.689 29.472 7.808 29.496 ;
     RECT  7.621 30.672 7.808 31.704 ;
     RECT  6.545 33.552 7.808 35.976 ;
     RECT  7.765 37.056 7.808 37.608 ;
     RECT  7.808 2.148 7.912 62.652 ;
     RECT  7.912 2.418 8.104 62.382 ;
     RECT  8.104 30.672 8.201 34.392 ;
     RECT  8.104 27.408 9.425 29.592 ;
     RECT  8.104 35.472 9.457 37.944 ;
     RECT  9.457 35.232 9.529 37.944 ;
     RECT  9.529 35.232 9.601 38.472 ;
     RECT  9.601 35.232 9.637 38.664 ;
     RECT  8.201 30.672 9.673 33.576 ;
     RECT  9.673 30.624 9.817 33.576 ;
     RECT  9.637 35.232 9.817 38.76 ;
     RECT  9.425 27.888 10.508 29.592 ;
     RECT  9.817 30.624 10.508 38.76 ;
     RECT  9.637 41.664 10.508 41.688 ;
     RECT  10.508 2.148 10.612 62.652 ;
     RECT  10.612 2.418 10.804 62.382 ;
     RECT  10.804 27.888 10.829 28.488 ;
     RECT  10.829 27.888 10.865 28.296 ;
     RECT  10.804 29.568 11.117 39.096 ;
     RECT  11.117 30.432 11.441 39.096 ;
     RECT  11.441 37.92 11.603 39.096 ;
     RECT  11.603 37.92 11.657 38.472 ;
     RECT  11.657 38.16 11.693 38.472 ;
     RECT  11.441 30.432 11.945 36.888 ;
     RECT  11.945 30.432 11.981 36.792 ;
     RECT  11.981 32.016 12.053 36.792 ;
     RECT  11.981 30.432 12.089 30.888 ;
     RECT  10.865 27.888 12.121 27.912 ;
     RECT  12.053 32.016 12.125 34.872 ;
     RECT  12.125 34.128 12.161 34.872 ;
     RECT  12.089 30.432 12.197 30.648 ;
     RECT  12.121 27.888 12.233 28.824 ;
     RECT  12.161 34.176 12.233 34.872 ;
     RECT  12.233 28.512 13.208 28.824 ;
     RECT  12.197 30.432 13.208 30.456 ;
     RECT  12.125 32.016 13.208 32.616 ;
     RECT  12.233 34.176 13.208 34.488 ;
     RECT  12.053 36.048 13.208 36.072 ;
     RECT  11.693 38.16 13.208 38.184 ;
     RECT  10.804 41.664 13.208 41.688 ;
     RECT  13.208 2.148 13.312 62.652 ;
     RECT  13.312 2.418 13.504 62.382 ;
     RECT  13.504 35.952 13.601 36.072 ;
     RECT  13.504 28.416 13.619 28.968 ;
     RECT  13.504 33.84 13.619 33.864 ;
     RECT  13.504 38.112 13.889 38.184 ;
     RECT  13.504 39.792 14.285 39.912 ;
     RECT  14.569 32.496 14.653 32.52 ;
     RECT  13.619 28.416 14.821 28.824 ;
     RECT  13.601 35.952 14.821 35.976 ;
     RECT  14.821 35.952 14.861 36.072 ;
     RECT  14.285 39.792 15.781 39.816 ;
     RECT  14.821 28.272 15.908 28.824 ;
     RECT  15.781 34.128 15.908 34.152 ;
     RECT  14.861 36.048 15.908 36.072 ;
     RECT  13.889 38.112 15.908 38.136 ;
     RECT  15.781 39.12 15.908 39.816 ;
     RECT  13.504 41.664 15.908 41.688 ;
     RECT  15.908 2.148 16.012 62.652 ;
     RECT  16.012 2.418 16.204 62.382 ;
     RECT  16.204 27.888 16.337 29.64 ;
     RECT  16.337 27.888 16.355 28.536 ;
     RECT  16.355 28.272 16.381 28.536 ;
     RECT  16.204 33.072 16.669 33.096 ;
     RECT  16.204 38.208 17.453 38.232 ;
     RECT  16.337 29.616 17.941 29.64 ;
     RECT  16.204 39.792 18.061 39.816 ;
     RECT  16.204 36.048 18.385 36.072 ;
     RECT  18.061 39.312 18.421 39.816 ;
     RECT  16.204 23.904 18.608 23.928 ;
     RECT  16.381 28.272 18.608 28.44 ;
     RECT  17.941 29.616 18.608 30.6 ;
     RECT  18.601 34.656 18.608 34.68 ;
     RECT  18.385 36.048 18.608 36.888 ;
     RECT  18.421 39.072 18.608 39.816 ;
     RECT  16.204 41.664 18.608 41.688 ;
     RECT  18.608 2.148 18.712 62.652 ;
     RECT  18.712 2.418 18.904 62.382 ;
     RECT  18.904 36.048 19.091 37.032 ;
     RECT  18.904 28.272 19.181 28.44 ;
     RECT  18.904 39.072 19.379 39.336 ;
     RECT  18.904 29.616 19.909 29.64 ;
     RECT  19.909 29.616 19.955 29.928 ;
     RECT  18.904 23.808 20.297 23.832 ;
     RECT  18.904 41.664 21.02 42.552 ;
     RECT  19.379 39.312 21.061 39.336 ;
     RECT  21.02 40.8 21.061 42.552 ;
     RECT  18.904 33.888 21.193 34.68 ;
     RECT  20.473 23.904 21.308 23.928 ;
     RECT  19.181 28.416 21.308 28.44 ;
     RECT  19.955 29.904 21.308 29.928 ;
     RECT  19.871 31.2 21.308 31.224 ;
     RECT  21.193 33.888 21.308 35.448 ;
     RECT  19.091 36.864 21.308 36.888 ;
     RECT  21.061 39.312 21.308 42.552 ;
     RECT  21.308 2.148 21.412 62.652 ;
     RECT  21.412 2.418 21.604 62.382 ;
     RECT  21.604 31.2 21.989 31.416 ;
     RECT  21.604 32.496 22.3 32.712 ;
     RECT  21.989 31.392 22.565 31.416 ;
     RECT  21.604 23.904 22.705 23.928 ;
     RECT  21.604 33.888 22.777 33.912 ;
     RECT  22.777 33.792 22.817 33.912 ;
     RECT  22.705 23.808 22.853 23.928 ;
     RECT  21.604 40.224 22.889 40.248 ;
     RECT  21.604 35.424 23.353 35.448 ;
     RECT  22.3 32.496 23.893 32.52 ;
     RECT  22.817 33.792 23.893 33.816 ;
     RECT  22.853 23.904 24.008 23.928 ;
     RECT  21.604 28.416 24.008 28.44 ;
     RECT  23.893 32.496 24.008 33.816 ;
     RECT  23.353 35.424 24.008 35.736 ;
     RECT  21.604 36.864 24.008 36.888 ;
     RECT  21.604 41.664 24.008 42.552 ;
     RECT  24.008 2.148 24.112 62.652 ;
     RECT  24.112 2.418 24.304 62.382 ;
     RECT  24.304 40.704 24.419 42.216 ;
     RECT  24.304 33.648 24.617 34.2 ;
     RECT  24.419 40.704 24.725 40.728 ;
     RECT  24.304 35.712 25.697 35.736 ;
     RECT  24.304 32.496 25.837 32.52 ;
     RECT  24.419 42.192 26.125 42.216 ;
     RECT  25.837 32.496 26.197 33.048 ;
     RECT  24.304 23.904 26.708 23.928 ;
     RECT  24.304 28.416 26.708 28.44 ;
     RECT  26.197 32.496 26.708 33.672 ;
     RECT  24.304 36.864 26.708 36.888 ;
     RECT  26.125 41.952 26.708 42.216 ;
     RECT  26.708 2.148 26.812 62.652 ;
     RECT  26.812 2.418 27.004 62.382 ;
     RECT  27.004 33.648 27.497 34.104 ;
     RECT  27.004 36.864 28.175 36.888 ;
     RECT  27.004 41.04 28.213 41.976 ;
     RECT  28.213 41.04 28.259 42.456 ;
     RECT  27.497 34.08 28.604 34.104 ;
     RECT  28.604 33.792 28.645 34.104 ;
     RECT  28.259 41.952 28.741 42.456 ;
     RECT  27.004 23.904 29.408 23.928 ;
     RECT  27.004 28.416 29.408 28.44 ;
     RECT  28.645 33.024 29.408 34.104 ;
     RECT  28.175 36.624 29.408 36.888 ;
     RECT  28.741 41.952 29.408 42.744 ;
     RECT  29.408 2.148 29.512 62.652 ;
     RECT  29.512 2.418 29.704 62.382 ;
     RECT  29.704 33.024 30.089 33.048 ;
     RECT  29.704 23.808 30.769 23.832 ;
     RECT  29.704 35.856 30.769 36.888 ;
     RECT  30.769 23.808 30.809 23.928 ;
     RECT  30.769 35.856 30.851 37.032 ;
     RECT  31.333 38.16 31.777 38.184 ;
     RECT  31.813 31.92 31.909 31.944 ;
     RECT  30.809 23.904 32.108 23.928 ;
     RECT  29.704 28.416 32.108 28.44 ;
     RECT  31.909 31.92 32.108 32.328 ;
     RECT  31.993 34.896 32.108 34.92 ;
     RECT  30.851 36.144 32.108 37.032 ;
     RECT  31.777 38.16 32.108 38.424 ;
     RECT  31.885 42.72 32.108 42.744 ;
     RECT  29.704 43.92 32.108 43.944 ;
     RECT  32.108 2.148 32.212 62.652 ;
     RECT  32.212 2.418 32.404 62.382 ;
     RECT  31.909 0.096 32.435 0.12 ;
     RECT  32.404 42.72 32.531 42.744 ;
     RECT  32.404 34.896 33.077 35.352 ;
     RECT  32.404 43.776 33.901 43.8 ;
     RECT  33.077 35.328 34.021 35.352 ;
     RECT  34.541 6.864 34.808 6.888 ;
     RECT  32.404 23.904 34.808 23.928 ;
     RECT  32.404 28.416 34.808 28.44 ;
     RECT  34.021 35.328 34.808 35.88 ;
     RECT  32.404 36.864 34.808 38.424 ;
     RECT  33.901 43.776 34.808 43.848 ;
     RECT  34.808 2.148 34.912 62.652 ;
     RECT  34.912 2.418 35.104 62.382 ;
     RECT  35.104 35.856 35.165 38.424 ;
     RECT  35.104 43.824 35.381 44.472 ;
     RECT  35.165 35.856 35.891 36.888 ;
     RECT  35.104 41.088 35.921 41.112 ;
     RECT  35.165 38.4 36.277 38.424 ;
     RECT  35.104 42.192 36.421 42.216 ;
     RECT  36.421 41.184 36.467 42.216 ;
     RECT  36.467 41.184 36.533 41.304 ;
     RECT  36.277 38.112 37.069 38.424 ;
     RECT  35.104 23.904 37.508 23.928 ;
     RECT  35.104 28.416 37.508 28.44 ;
     RECT  35.891 36.48 37.508 36.888 ;
     RECT  37.069 38.112 37.508 38.76 ;
     RECT  36.533 41.184 37.508 41.208 ;
     RECT  37.213 42.72 37.508 42.744 ;
     RECT  35.381 44.448 37.508 44.472 ;
     RECT  37.508 2.148 37.612 62.652 ;
     RECT  37.612 2.418 37.804 62.382 ;
     RECT  37.804 42.72 37.955 45.192 ;
     RECT  37.955 43.488 37.981 45.192 ;
     RECT  37.804 38.736 38.189 39.288 ;
     RECT  37.981 44.448 38.441 45.192 ;
     RECT  37.804 36.624 38.773 36.888 ;
     RECT  37.804 23.808 38.801 23.928 ;
     RECT  37.804 41.088 38.801 41.208 ;
     RECT  38.773 36.624 38.86 37.608 ;
     RECT  38.86 36.624 39.059 36.888 ;
     RECT  38.801 23.904 40.208 23.928 ;
     RECT  37.804 28.416 40.208 28.44 ;
     RECT  39.013 31.392 40.208 31.416 ;
     RECT  39.059 36.864 40.208 36.888 ;
     RECT  40.129 39.216 40.208 39.24 ;
     RECT  38.801 41.184 40.208 41.208 ;
     RECT  38.441 45.168 40.208 45.192 ;
     RECT  40.208 2.148 40.312 62.652 ;
     RECT  40.312 2.418 40.504 62.382 ;
     RECT  41.605 38.16 41.692 38.184 ;
     RECT  40.504 41.184 41.821 41.208 ;
     RECT  40.504 39.216 41.929 39.24 ;
     RECT  41.821 40.56 41.929 41.208 ;
     RECT  40.504 23.904 42.908 23.928 ;
     RECT  40.504 28.416 42.908 28.44 ;
     RECT  40.504 31.392 42.908 31.416 ;
     RECT  40.504 36.864 42.908 36.888 ;
     RECT  41.929 39.216 42.908 41.208 ;
     RECT  40.504 45.168 42.908 45.192 ;
     RECT  42.757 46.752 42.908 46.776 ;
     RECT  42.908 2.148 43.012 62.652 ;
     RECT  43.012 2.418 43.204 62.382 ;
     RECT  43.204 39.216 43.265 40.536 ;
     RECT  43.265 40.032 43.331 40.536 ;
     RECT  43.204 44.88 44.399 44.904 ;
     RECT  44.399 44.88 44.437 45.336 ;
     RECT  44.437 44.4 44.524 45.336 ;
     RECT  43.331 40.032 44.917 40.296 ;
     RECT  43.204 46.752 45.212 46.776 ;
     RECT  44.524 45.312 45.253 45.336 ;
     RECT  45.212 46.656 45.253 46.776 ;
     RECT  45.253 45.312 45.452 47.064 ;
     RECT  43.204 23.904 45.608 23.928 ;
     RECT  43.204 28.416 45.608 28.44 ;
     RECT  43.204 31.392 45.608 31.416 ;
     RECT  43.204 36.864 45.608 36.888 ;
     RECT  44.917 40.032 45.608 40.44 ;
     RECT  45.061 41.76 45.608 41.784 ;
     RECT  45.452 45.312 45.608 47.592 ;
     RECT  45.608 2.148 45.712 62.652 ;
     RECT  45.712 2.418 45.904 62.382 ;
     RECT  45.904 40.032 46.115 41.784 ;
     RECT  45.904 44.448 46.117 44.472 ;
     RECT  46.115 41.232 46.181 41.64 ;
     RECT  45.904 23.664 46.793 23.832 ;
     RECT  45.904 46.224 46.793 46.248 ;
     RECT  47.213 47.184 47.297 47.208 ;
     RECT  47.221 46.128 47.305 46.152 ;
     RECT  46.181 41.616 47.761 41.64 ;
     RECT  47.761 41.232 47.893 41.64 ;
     RECT  46.793 23.664 48.308 23.688 ;
     RECT  45.904 28.416 48.308 28.44 ;
     RECT  45.904 31.392 48.308 31.416 ;
     RECT  45.904 36.864 48.308 36.888 ;
     RECT  46.115 40.032 48.308 40.056 ;
     RECT  47.893 41.232 48.308 42.072 ;
     RECT  47.005 43.248 48.308 43.272 ;
     RECT  47.329 45.696 48.308 45.72 ;
     RECT  47.869 48.24 48.308 48.264 ;
     RECT  48.181 50.928 48.308 50.952 ;
     RECT  48.308 2.148 48.412 62.652 ;
     RECT  48.412 2.418 48.604 62.382 ;
     RECT  48.604 39.408 49.061 41.016 ;
     RECT  48.604 29.472 49.372 31.416 ;
     RECT  49.372 29.616 49.421 31.416 ;
     RECT  48.604 36.768 49.427 37.608 ;
     RECT  49.421 29.616 49.465 30.408 ;
     RECT  48.604 45.696 49.669 45.72 ;
     RECT  49.669 44.976 49.715 46.488 ;
     RECT  49.715 44.976 49.756 45 ;
     RECT  49.427 37.584 49.885 37.608 ;
     RECT  48.604 43.92 49.921 43.944 ;
     RECT  49.061 40.176 49.961 41.016 ;
     RECT  48.604 28.416 49.993 28.44 ;
     RECT  49.961 40.176 50.173 40.296 ;
     RECT  49.921 43.632 50.209 43.944 ;
     RECT  50.137 34.464 50.273 34.488 ;
     RECT  48.604 35.52 50.273 35.544 ;
     RECT  50.209 42.72 50.389 43.944 ;
     RECT  50.273 34.464 50.461 35.544 ;
     RECT  49.885 37.584 50.461 37.896 ;
     RECT  50.173 39.552 50.461 40.296 ;
     RECT  49.715 46.464 50.497 46.488 ;
     RECT  48.604 47.856 50.497 47.88 ;
     RECT  49.993 28.416 50.849 28.488 ;
     RECT  50.389 42.576 50.869 43.944 ;
     RECT  50.461 37.584 50.893 40.296 ;
     RECT  50.785 41.376 50.893 41.4 ;
     RECT  50.869 42.576 50.893 45.144 ;
     RECT  50.497 46.464 50.965 48.456 ;
     RECT  48.604 23.664 51.008 23.688 ;
     RECT  50.869 26.736 51.008 26.76 ;
     RECT  50.849 28.416 51.008 28.632 ;
     RECT  49.465 30.384 51.008 30.408 ;
     RECT  49.421 31.392 51.008 31.416 ;
     RECT  50.461 33.888 51.008 35.544 ;
     RECT  50.893 37.104 51.008 40.296 ;
     RECT  50.893 41.376 51.008 45.144 ;
     RECT  50.965 46.224 51.008 48.456 ;
     RECT  48.604 50.928 51.008 50.952 ;
     RECT  51.008 2.148 51.112 62.652 ;
     RECT  51.112 2.418 51.304 62.382 ;
     RECT  51.304 22.752 51.443 23.832 ;
     RECT  51.304 34.896 51.545 39.624 ;
     RECT  51.304 24.864 51.581 24.888 ;
     RECT  51.545 34.896 51.617 37.128 ;
     RECT  51.304 46.224 51.653 48.504 ;
     RECT  51.304 41.376 51.689 43.272 ;
     RECT  51.617 36.24 51.923 37.128 ;
     RECT  51.545 38.448 52.049 39.624 ;
     RECT  51.689 41.376 52.121 41.4 ;
     RECT  51.689 42.432 52.121 43.272 ;
     RECT  51.304 20.16 52.229 20.184 ;
     RECT  52.121 42.432 52.301 42.744 ;
     RECT  51.304 44.448 52.364 45 ;
     RECT  51.304 33.888 52.369 33.912 ;
     RECT  52.297 49.728 52.412 49.752 ;
     RECT  51.304 50.928 52.412 50.952 ;
     RECT  52.364 44.352 52.451 45 ;
     RECT  51.304 28.416 52.453 29.208 ;
     RECT  51.304 30.384 52.453 31.944 ;
     RECT  51.653 46.704 52.453 48.504 ;
     RECT  52.412 49.728 52.453 50.952 ;
     RECT  52.301 42.72 52.481 42.744 ;
     RECT  52.453 28.416 52.499 31.944 ;
     RECT  52.453 46.704 52.499 50.952 ;
     RECT  52.499 46.704 52.553 49.032 ;
     RECT  52.369 33.408 52.697 34.584 ;
     RECT  52.499 50.928 52.765 50.952 ;
     RECT  51.304 21.504 52.837 21.72 ;
     RECT  51.923 36.576 52.885 37.08 ;
     RECT  52.049 38.448 52.885 38.472 ;
     RECT  51.443 23.664 52.945 23.832 ;
     RECT  52.451 44.976 52.945 45 ;
     RECT  52.765 50.928 52.981 51.864 ;
     RECT  52.837 21.504 53.084 22.2 ;
     RECT  53.084 21.168 53.125 22.2 ;
     RECT  52.945 23.664 53.125 24.648 ;
     RECT  52.697 34.56 53.377 34.584 ;
     RECT  52.885 36.576 53.377 38.472 ;
     RECT  53.125 21.168 53.449 24.648 ;
     RECT  52.945 44.976 53.449 45.624 ;
     RECT  52.553 46.704 53.449 47.88 ;
     RECT  53.377 36.528 53.485 38.472 ;
     RECT  52.049 39.456 53.485 39.624 ;
     RECT  53.449 44.976 53.557 47.88 ;
     RECT  52.553 49.008 53.557 49.032 ;
     RECT  53.485 36.528 53.629 39.624 ;
     RECT  53.269 42 53.629 42.024 ;
     RECT  53.485 43.824 53.629 43.848 ;
     RECT  53.557 44.976 53.629 49.032 ;
     RECT  53.629 36.528 53.665 42.024 ;
     RECT  53.197 19.296 53.708 19.32 ;
     RECT  53.449 20.976 53.708 24.648 ;
     RECT  53.077 25.824 53.708 26.232 ;
     RECT  52.499 28.416 53.708 28.872 ;
     RECT  52.499 30 53.708 31.944 ;
     RECT  52.697 33.408 53.708 33.576 ;
     RECT  53.377 34.56 53.708 35.496 ;
     RECT  53.665 36.528 53.708 42.216 ;
     RECT  53.629 43.824 53.708 49.032 ;
     RECT  52.981 50.928 53.708 52.536 ;
     RECT  53.708 2.148 53.812 62.652 ;
     RECT  53.812 2.418 54.004 62.382 ;
     RECT  54.004 10.752 54.131 11.688 ;
     RECT  54.004 36.528 54.131 42.744 ;
     RECT  54.004 43.824 54.131 48.648 ;
     RECT  54.131 44.064 54.137 48.648 ;
     RECT  54.137 44.064 54.173 45.048 ;
     RECT  54.004 23.04 54.179 23.832 ;
     RECT  54.004 31.392 54.179 31.8 ;
     RECT  54.137 46.512 54.179 48.648 ;
     RECT  54.004 50.928 54.179 53.016 ;
     RECT  54.004 33.552 54.209 33.672 ;
     RECT  54.173 44.064 54.317 45 ;
     RECT  54.179 46.512 54.317 47.88 ;
     RECT  54.131 36.624 54.389 37.08 ;
     RECT  54.131 38.16 54.461 42.744 ;
     RECT  54.004 19.296 54.497 19.32 ;
     RECT  54.389 36.624 54.497 36.936 ;
     RECT  54.004 35.472 54.605 35.496 ;
     RECT  54.004 26.784 54.749 27.144 ;
     RECT  54.461 38.16 54.947 39.864 ;
     RECT  54.004 21.168 55.001 21.528 ;
     RECT  54.179 50.928 55.177 51.912 ;
     RECT  54.004 30.288 55.249 30.312 ;
     RECT  54.179 31.392 55.249 31.416 ;
     RECT  54.749 27.12 55.285 27.144 ;
     RECT  54.004 28.416 55.285 28.44 ;
     RECT  55.249 30.288 55.285 31.416 ;
     RECT  55.069 16.128 55.357 16.152 ;
     RECT  54.461 41.04 55.433 42.744 ;
     RECT  54.497 36.624 55.477 36.648 ;
     RECT  54.947 39.36 55.501 39.864 ;
     RECT  55.357 14.832 55.537 14.856 ;
     RECT  55.357 16.128 55.537 16.488 ;
     RECT  55.177 50.448 55.645 51.912 ;
     RECT  54.179 52.944 55.645 53.016 ;
     RECT  55.645 18.144 55.681 18.168 ;
     RECT  54.317 47.136 55.681 47.88 ;
     RECT  54.131 10.752 55.717 10.776 ;
     RECT  55.433 41.904 55.717 42.744 ;
     RECT  54.317 44.064 55.717 44.472 ;
     RECT  55.645 50.448 55.724 53.016 ;
     RECT  55.285 28.416 55.753 31.416 ;
     RECT  55.724 50.112 55.765 53.976 ;
     RECT  55.681 18 55.789 18.168 ;
     RECT  55.753 28.416 55.789 32.136 ;
     RECT  55.789 24.912 55.813 24.936 ;
     RECT  55.789 22.416 55.82 22.44 ;
     RECT  55.813 24.912 55.861 25.032 ;
     RECT  54.947 38.16 55.861 38.184 ;
     RECT  55.861 24.528 55.897 25.08 ;
     RECT  55.897 24.336 55.916 25.08 ;
     RECT  55.477 36.192 55.969 36.648 ;
     RECT  55.285 27.12 56.005 27.24 ;
     RECT  55.789 28.416 56.005 32.232 ;
     RECT  55.861 33.408 56.005 34.2 ;
     RECT  55.916 24.336 56.012 25.368 ;
     RECT  56.005 26.4 56.012 27.24 ;
     RECT  55.969 13.68 56.041 13.704 ;
     RECT  55.537 14.832 56.041 16.488 ;
     RECT  55.765 50.112 56.108 54.744 ;
     RECT  55.001 21.168 56.113 21.432 ;
     RECT  55.82 22.416 56.113 23.16 ;
     RECT  55.969 36.096 56.149 36.648 ;
     RECT  55.681 47.136 56.149 48.504 ;
     RECT  56.041 55.92 56.149 55.944 ;
     RECT  56.012 24.336 56.157 27.24 ;
     RECT  56.005 28.416 56.157 34.2 ;
     RECT  55.861 19.968 56.185 19.992 ;
     RECT  55.861 38.016 56.185 38.184 ;
     RECT  55.501 39.36 56.185 40.488 ;
     RECT  56.005 46.128 56.185 46.152 ;
     RECT  56.149 47.136 56.185 49.08 ;
     RECT  56.157 24.336 56.197 34.2 ;
     RECT  56.113 21.168 56.245 23.16 ;
     RECT  56.197 24.24 56.245 34.488 ;
     RECT  56.245 21.168 56.257 34.488 ;
     RECT  56.185 19.968 56.285 20.184 ;
     RECT  56.257 21.168 56.285 34.728 ;
     RECT  56.041 13.68 56.365 16.488 ;
     RECT  55.789 17.472 56.365 18.168 ;
     RECT  56.293 9.6 56.401 9.624 ;
     RECT  56.285 19.968 56.401 34.728 ;
     RECT  56.149 36.096 56.401 36.84 ;
     RECT  56.401 9.072 56.408 9.624 ;
     RECT  55.717 10.656 56.408 10.776 ;
     RECT  56.245 11.952 56.408 11.976 ;
     RECT  56.365 13.68 56.408 18.168 ;
     RECT  56.401 19.968 56.408 36.84 ;
     RECT  56.185 38.016 56.408 40.488 ;
     RECT  55.717 41.904 56.408 44.472 ;
     RECT  56.185 46.128 56.408 49.08 ;
     RECT  56.108 50.112 56.408 54.84 ;
     RECT  56.149 55.92 56.408 56.04 ;
     RECT  56.408 2.148 56.512 62.652 ;
     RECT  56.512 2.418 56.704 62.382 ;
     RECT  56.704 24.096 56.765 40.824 ;
     RECT  56.704 8.496 56.801 9.624 ;
     RECT  56.704 11.952 57.011 12.36 ;
     RECT  56.765 24.096 57.011 37.608 ;
     RECT  56.704 42.288 57.017 44.472 ;
     RECT  56.704 50.736 57.053 53.592 ;
     RECT  56.704 56.016 57.053 56.04 ;
     RECT  57.011 12.336 57.089 12.36 ;
     RECT  56.704 46.224 57.089 49.224 ;
     RECT  57.011 29.76 57.161 37.608 ;
     RECT  56.704 10.656 57.233 10.68 ;
     RECT  57.053 52.896 57.277 53.592 ;
     RECT  57.011 24.096 57.305 28.68 ;
     RECT  56.704 14.928 57.485 22.824 ;
     RECT  57.089 46.224 57.521 47.4 ;
     RECT  57.305 24.912 57.629 28.68 ;
     RECT  57.161 36 57.635 37.608 ;
     RECT  57.485 22.656 57.697 22.824 ;
     RECT  57.017 44.304 57.697 44.472 ;
     RECT  57.485 14.928 57.773 21.432 ;
     RECT  57.161 29.76 57.809 34.872 ;
     RECT  57.017 42.288 57.841 42.744 ;
     RECT  57.773 17.712 57.845 21.432 ;
     RECT  57.635 36 57.881 37.08 ;
     RECT  56.765 38.784 57.913 40.824 ;
     RECT  57.841 41.904 57.913 42.744 ;
     RECT  57.913 38.784 57.953 42.744 ;
     RECT  57.697 44.304 57.98 45.288 ;
     RECT  56.704 13.68 57.985 13.944 ;
     RECT  57.773 14.928 57.985 16.584 ;
     RECT  57.053 50.736 58.028 51.912 ;
     RECT  57.809 29.76 58.061 33.672 ;
     RECT  57.521 46.704 58.093 47.4 ;
     RECT  57.089 48.432 58.093 49.224 ;
     RECT  58.028 50.448 58.093 51.912 ;
     RECT  57.277 52.896 58.093 53.064 ;
     RECT  57.985 13.68 58.097 16.584 ;
     RECT  57.845 17.712 58.097 21.24 ;
     RECT  57.881 37.008 58.133 37.08 ;
     RECT  57.697 22.656 58.364 23.688 ;
     RECT  58.445 11.424 58.46 11.448 ;
     RECT  57.809 34.656 58.489 34.872 ;
     RECT  57.881 36 58.489 36.024 ;
     RECT  58.093 46.704 58.561 53.064 ;
     RECT  57.953 41.616 58.597 42.744 ;
     RECT  57.98 43.824 58.597 45.288 ;
     RECT  58.597 41.616 58.741 45.288 ;
     RECT  57.629 26.592 58.813 28.68 ;
     RECT  58.061 30.24 58.813 33.672 ;
     RECT  58.489 34.656 58.813 36.024 ;
     RECT  58.741 41.616 58.885 45.48 ;
     RECT  57.877 54.72 58.957 54.744 ;
     RECT  57.829 55.872 58.957 55.896 ;
     RECT  58.097 19.968 59.065 21.24 ;
     RECT  58.364 22.656 59.065 23.928 ;
     RECT  58.561 46.704 59.065 53.592 ;
     RECT  58.957 54.72 59.065 55.896 ;
     RECT  56.801 8.496 59.108 8.76 ;
     RECT  58.46 11.424 59.108 11.976 ;
     RECT  58.097 13.68 59.108 16.2 ;
     RECT  58.097 17.712 59.108 18.984 ;
     RECT  59.065 19.968 59.108 23.928 ;
     RECT  57.629 24.912 59.108 25.08 ;
     RECT  58.813 26.352 59.108 28.68 ;
     RECT  58.813 30.24 59.108 36.024 ;
     RECT  58.133 37.056 59.108 37.08 ;
     RECT  57.953 38.784 59.108 40.44 ;
     RECT  58.885 41.616 59.108 45.576 ;
     RECT  59.065 46.704 59.108 55.896 ;
     RECT  58.957 57.6 59.108 57.624 ;
     RECT  59.108 2.148 59.212 62.652 ;
     RECT  59.212 2.418 59.404 62.382 ;
     RECT  59.404 26.352 59.429 28.392 ;
     RECT  59.404 44.352 59.429 45.48 ;
     RECT  59.404 15.84 59.465 16.584 ;
     RECT  59.404 46.608 59.501 47.736 ;
     RECT  59.404 54.672 59.501 54.744 ;
     RECT  59.404 21.696 59.537 21.72 ;
     RECT  59.429 26.544 59.573 28.392 ;
     RECT  59.404 40.368 59.573 40.392 ;
     RECT  59.404 50.016 59.573 52.536 ;
     RECT  59.573 50.832 59.609 52.536 ;
     RECT  59.404 53.568 59.609 53.592 ;
     RECT  59.404 13.68 59.681 13.704 ;
     RECT  59.465 15.888 59.681 16.392 ;
     RECT  59.404 17.712 59.717 17.928 ;
     RECT  59.609 51.744 59.717 52.536 ;
     RECT  59.573 26.592 59.861 28.392 ;
     RECT  59.404 8.544 59.897 8.568 ;
     RECT  59.404 30.864 59.897 31.848 ;
     RECT  59.717 51.744 59.897 51.96 ;
     RECT  59.501 54.672 60.005 54.696 ;
     RECT  59.404 57.6 60.005 57.624 ;
     RECT  59.681 15.888 60.077 15.912 ;
     RECT  59.429 45.456 60.077 45.48 ;
     RECT  59.717 17.904 60.149 17.928 ;
     RECT  59.404 55.728 60.149 55.752 ;
     RECT  59.404 24.336 60.221 25.224 ;
     RECT  59.897 31.344 60.293 31.848 ;
     RECT  59.501 46.608 60.329 47.4 ;
     RECT  60.293 31.344 60.365 31.752 ;
     RECT  59.404 42.192 60.437 42.744 ;
     RECT  60.437 42.72 60.473 42.744 ;
     RECT  60.329 47.376 60.473 47.4 ;
     RECT  60.221 25.2 60.509 25.224 ;
     RECT  59.404 33.6 60.509 36.024 ;
     RECT  59.861 27.312 60.545 28.392 ;
     RECT  60.509 35.136 60.545 36.024 ;
     RECT  60.545 27.408 60.581 28.392 ;
     RECT  59.404 22.752 60.613 23.16 ;
     RECT  60.613 22.752 60.689 23.544 ;
     RECT  60.545 36 60.761 36.024 ;
     RECT  59.897 51.744 61.225 51.768 ;
     RECT  60.509 33.6 61.549 33.624 ;
     RECT  61.549 33.264 61.657 33.624 ;
     RECT  60.689 23.28 61.808 23.544 ;
     RECT  61.441 24.624 61.808 24.648 ;
     RECT  60.581 28.368 61.808 28.392 ;
     RECT  60.365 31.344 61.808 31.416 ;
     RECT  61.657 33.264 61.808 33.96 ;
     RECT  61.369 36.528 61.808 36.552 ;
     RECT  61.693 41.712 61.808 41.736 ;
     RECT  59.429 44.352 61.808 44.376 ;
     RECT  60.721 46.368 61.808 46.392 ;
     RECT  60.577 48.384 61.808 48.408 ;
     RECT  61.225 51.36 61.808 51.768 ;
     RECT  61.808 2.148 61.912 62.652 ;
     RECT  61.912 2.418 62.104 62.382 ;
     RECT  62.104 32.112 62.165 35.016 ;
     RECT  62.104 36.528 62.165 39.432 ;
     RECT  62.165 32.112 63.169 32.712 ;
     RECT  62.165 34.032 63.169 35.016 ;
     RECT  62.104 18.864 63.205 18.888 ;
     RECT  62.104 20.208 63.205 20.232 ;
     RECT  62.104 51.312 63.205 51.384 ;
     RECT  62.104 11.184 63.241 12.36 ;
     RECT  62.104 14.64 63.241 14.664 ;
     RECT  62.104 15.984 63.241 17.544 ;
     RECT  63.205 18.864 63.241 20.232 ;
     RECT  62.104 21.552 63.241 25.416 ;
     RECT  62.104 26.736 63.241 29.256 ;
     RECT  63.169 32.112 63.241 35.016 ;
     RECT  62.165 36.72 63.241 39.432 ;
     RECT  62.104 44.208 63.241 44.232 ;
     RECT  62.104 46.128 63.241 46.344 ;
     RECT  62.104 48.048 63.241 48.072 ;
     RECT  63.205 51.312 63.241 53.256 ;
     RECT  63.241 44.208 63.277 48.072 ;
     RECT  63.241 49.2 63.277 49.224 ;
     RECT  63.241 51.312 63.277 53.832 ;
     RECT  63.241 54.96 63.277 54.984 ;
     RECT  63.241 11.184 63.745 13.32 ;
     RECT  63.241 14.64 63.745 30.024 ;
     RECT  62.104 41.52 63.781 41.736 ;
     RECT  63.277 43.248 63.781 49.224 ;
     RECT  63.277 51.312 63.781 54.984 ;
     RECT  63.277 8.688 63.817 8.712 ;
     RECT  63.745 11.184 63.817 30.024 ;
     RECT  63.241 32.112 63.817 39.432 ;
     RECT  63.781 41.52 63.817 49.224 ;
     RECT  63.781 50.352 63.817 54.984 ;
     RECT  63.241 56.496 63.817 56.52 ;
     RECT  63.817 8.496 63.853 9.864 ;
     RECT  63.817 11.184 63.853 39.432 ;
     RECT  63.817 41.136 63.853 55.368 ;
     RECT  63.853 8.112 63.889 10.056 ;
     RECT  63.853 11.184 63.889 55.368 ;
     RECT  63.889 8.112 64.465 55.368 ;
     RECT  63.817 56.496 64.465 56.712 ;
     RECT  64.465 8.112 64.764 56.712 ;
    LAYER M5 ;
     RECT  32.4 0.016 32.424 0.085 ;
     RECT  31.92 0.085 32.424 0.131 ;
     RECT  31.92 0.131 31.944 2.137 ;
     RECT  34.56 0.016 34.584 2.137 ;
     RECT  2.4 2.137 2.52 2.151 ;
     RECT  5.1 2.137 5.22 2.151 ;
     RECT  7.8 2.137 7.92 2.151 ;
     RECT  10.5 2.137 10.62 2.151 ;
     RECT  13.2 2.137 13.32 2.151 ;
     RECT  15.9 2.137 16.02 2.151 ;
     RECT  18.6 2.137 18.72 2.151 ;
     RECT  21.3 2.137 21.42 2.151 ;
     RECT  24 2.137 24.12 2.151 ;
     RECT  26.7 2.137 26.82 2.151 ;
     RECT  29.4 2.137 29.52 2.151 ;
     RECT  31.92 2.137 32.22 2.151 ;
     RECT  34.56 2.137 34.92 2.151 ;
     RECT  37.5 2.137 37.62 2.151 ;
     RECT  40.2 2.137 40.32 2.151 ;
     RECT  42.9 2.137 43.02 2.151 ;
     RECT  45.6 2.137 45.72 2.151 ;
     RECT  48.3 2.137 48.42 2.151 ;
     RECT  51 2.137 51.12 2.151 ;
     RECT  53.7 2.137 53.82 2.151 ;
     RECT  56.4 2.137 56.52 2.151 ;
     RECT  59.1 2.137 59.22 2.151 ;
     RECT  61.8 2.137 61.92 2.151 ;
     RECT  34.56 2.151 35.112 6.899 ;
     RECT  59.1 2.151 59.412 8.485 ;
     RECT  56.4 2.151 56.712 9.589 ;
     RECT  53.7 2.151 54.012 10.741 ;
     RECT  58.464 8.485 59.412 11.459 ;
     RECT  53.7 10.741 54.12 11.699 ;
     RECT  56.304 9.589 56.712 11.941 ;
     RECT  56.256 11.941 57 13.715 ;
     RECT  56.256 13.715 56.712 15.829 ;
     RECT  56.256 15.829 56.808 16.117 ;
     RECT  58.512 11.459 59.412 16.211 ;
     RECT  55.872 16.117 56.808 16.357 ;
     RECT  55.872 16.357 56.856 18.133 ;
     RECT  55.872 18.133 57 19.909 ;
     RECT  55.872 19.909 57.048 20.003 ;
     RECT  51 2.151 51.312 20.149 ;
     RECT  58.608 16.211 59.412 21.109 ;
     RECT  53.7 11.699 54.012 21.157 ;
     RECT  56.016 20.003 57.048 21.203 ;
     RECT  51 20.149 51.912 21.731 ;
     RECT  56.016 21.203 57 21.731 ;
     RECT  53.136 21.157 54.012 22.211 ;
     RECT  51 21.731 51.312 22.741 ;
     RECT  53.7 22.211 54.012 23.029 ;
     RECT  56.016 21.731 56.952 23.125 ;
     RECT  15.9 2.151 16.212 23.893 ;
     RECT  55.872 23.125 56.952 24.131 ;
     RECT  53.7 23.029 54.168 24.613 ;
     RECT  51 22.741 51.432 24.899 ;
     RECT  55.872 24.131 56.904 24.997 ;
     RECT  53.088 24.613 54.168 26.243 ;
     RECT  51 24.899 51.312 26.725 ;
     RECT  53.7 26.243 54.168 26.819 ;
     RECT  58.416 21.109 59.412 27.107 ;
     RECT  55.824 24.997 56.904 27.205 ;
     RECT  5.1 2.151 5.412 27.301 ;
     RECT  18.6 2.151 18.912 28.405 ;
     RECT  50.88 26.725 51.312 28.643 ;
     RECT  52.464 28.453 52.488 28.837 ;
     RECT  53.7 26.819 54.012 28.837 ;
     RECT  13.2 2.151 13.512 28.933 ;
     RECT  5.1 27.301 5.688 29.123 ;
     RECT  48.3 2.151 48.612 29.461 ;
     RECT  55.296 27.205 57 29.555 ;
     RECT  18.6 28.405 19.08 29.605 ;
     RECT  48.3 29.461 49.32 29.605 ;
     RECT  55.296 29.555 56.904 30.035 ;
     RECT  5.1 29.123 5.412 30.133 ;
     RECT  55.344 30.035 56.904 30.275 ;
     RECT  17.952 29.605 19.944 30.611 ;
     RECT  55.488 30.275 56.904 30.757 ;
     RECT  18.6 30.611 19.944 31.235 ;
     RECT  52.464 28.837 54.012 31.379 ;
     RECT  21.3 2.151 21.612 31.381 ;
     RECT  53.7 31.379 54.012 31.381 ;
     RECT  55.488 30.757 57.048 31.427 ;
     RECT  10.5 2.151 10.812 31.477 ;
     RECT  52.464 31.379 52.488 31.955 ;
     RECT  24 2.151 24.312 32.485 ;
     RECT  14.592 28.789 14.616 32.531 ;
     RECT  21.3 31.381 22.248 32.723 ;
     RECT  26.7 2.151 27.012 33.013 ;
     RECT  29.4 2.151 29.712 33.013 ;
     RECT  23.904 32.485 24.312 33.059 ;
     RECT  15.9 23.893 16.632 33.107 ;
     RECT  55.488 31.427 56.904 33.589 ;
     RECT  26.208 33.013 27.012 33.683 ;
     RECT  53.7 31.381 54.168 33.683 ;
     RECT  28.656 33.013 29.712 33.827 ;
     RECT  13.2 28.933 13.608 33.875 ;
     RECT  51 28.643 51.312 33.877 ;
     RECT  15.9 33.107 16.212 34.117 ;
     RECT  55.488 33.589 57.048 34.117 ;
     RECT  24 33.059 24.312 34.165 ;
     RECT  48.3 29.605 49.416 34.453 ;
     RECT  51 33.877 51.912 34.453 ;
     RECT  48.3 34.453 51.912 34.835 ;
     RECT  58.464 27.107 59.412 34.835 ;
     RECT  55.488 34.117 57.48 34.883 ;
     RECT  10.5 31.477 11.64 35.075 ;
     RECT  5.1 30.133 5.544 35.317 ;
     RECT  24 34.165 24.504 35.747 ;
     RECT  34.8 6.899 35.112 35.845 ;
     RECT  30.816 35.845 30.84 36.133 ;
     RECT  31.92 2.151 32.412 36.133 ;
     RECT  30.816 36.133 32.412 36.179 ;
     RECT  55.488 34.883 56.856 36.227 ;
     RECT  10.5 35.075 11.208 36.421 ;
     RECT  5.1 35.317 5.832 36.515 ;
     RECT  53.7 33.683 54.012 36.517 ;
     RECT  5.1 36.515 5.688 36.563 ;
     RECT  55.824 36.227 56.856 36.563 ;
     RECT  39.024 31.381 39.048 36.613 ;
     RECT  38.784 36.613 39.048 36.659 ;
     RECT  48.3 34.835 49.416 36.803 ;
     RECT  56.304 36.563 56.856 36.851 ;
     RECT  51 34.835 51.912 36.997 ;
     RECT  51 36.997 52.68 37.045 ;
     RECT  53.7 36.517 54.12 37.045 ;
     RECT  34.032 35.845 35.88 37.091 ;
     RECT  51 37.045 54.12 37.139 ;
     RECT  56.4 36.851 56.856 37.573 ;
     RECT  38.784 36.659 38.808 37.619 ;
     RECT  52.656 37.139 54.12 37.859 ;
     RECT  56.4 37.573 57.624 38.005 ;
     RECT  15.792 34.117 16.212 38.147 ;
     RECT  31.344 36.179 32.412 38.195 ;
     RECT  34.8 37.091 35.88 38.389 ;
     RECT  51 37.139 51.312 38.677 ;
     RECT  52.656 37.859 52.68 38.677 ;
     RECT  10.5 36.421 11.592 38.725 ;
     RECT  51 38.677 52.68 38.725 ;
     RECT  18.6 31.235 19.08 39.061 ;
     RECT  53.7 37.859 54.012 39.061 ;
     RECT  55.872 38.005 57.624 39.061 ;
     RECT  9.648 38.725 11.592 39.107 ;
     RECT  15.9 38.147 16.212 39.109 ;
     RECT  41.616 38.149 41.64 39.205 ;
     RECT  42.9 2.151 43.212 39.205 ;
     RECT  41.616 39.205 43.212 39.251 ;
     RECT  37.5 2.151 37.812 39.253 ;
     RECT  21.3 32.723 21.612 39.301 ;
     RECT  48.3 36.803 49.032 39.443 ;
     RECT  50.496 38.725 52.68 39.491 ;
     RECT  52.656 39.491 52.68 39.587 ;
     RECT  53.7 39.061 57.624 39.587 ;
     RECT  15.792 39.109 16.212 39.827 ;
     RECT  42.144 39.251 43.212 40.021 ;
     RECT  45.6 2.151 45.912 40.405 ;
     RECT  59.1 34.835 59.412 40.405 ;
     RECT  42.144 40.021 43.32 40.547 ;
     RECT  42.144 40.547 43.212 40.595 ;
     RECT  24 35.747 24.312 40.693 ;
     RECT  21.072 39.301 21.612 40.835 ;
     RECT  53.7 39.587 56.712 41.075 ;
     RECT  34.8 38.389 36.456 41.123 ;
     RECT  48.3 39.443 48.612 41.221 ;
     RECT  53.7 41.075 54.12 41.507 ;
     RECT  58.704 40.405 59.412 41.651 ;
     RECT  9.648 39.107 10.812 41.699 ;
     RECT  28.224 36.613 28.248 41.941 ;
     RECT  29.4 33.827 29.712 41.941 ;
     RECT  24 40.693 24.408 42.227 ;
     RECT  36.432 41.123 36.456 42.227 ;
     RECT  28.224 41.941 29.712 42.467 ;
     RECT  18.6 39.061 19.368 42.563 ;
     RECT  53.7 41.507 54.012 42.565 ;
     RECT  32.1 38.195 32.412 42.709 ;
     RECT  28.752 42.467 29.712 42.755 ;
     RECT  55.872 41.075 56.712 42.755 ;
     RECT  59.1 41.651 59.412 42.901 ;
     RECT  47.904 41.221 48.612 43.283 ;
     RECT  50.496 39.491 51.312 43.379 ;
     RECT  37.5 39.253 37.944 43.523 ;
     RECT  58.752 42.901 59.412 43.523 ;
     RECT  32.1 42.709 32.52 43.811 ;
     RECT  51 43.379 51.312 44.437 ;
     RECT  45.6 40.405 46.104 44.483 ;
     RECT  52.416 44.341 52.44 45.011 ;
     RECT  53.7 42.565 54.12 45.059 ;
     RECT  58.032 43.813 58.056 45.059 ;
     RECT  50.88 44.437 51.312 45.155 ;
     RECT  44.448 44.389 44.472 45.301 ;
     RECT  45.6 44.483 45.912 45.301 ;
     RECT  44.448 45.301 45.912 45.347 ;
     RECT  53.7 45.059 54.012 46.117 ;
     RECT  49.68 44.965 49.704 46.499 ;
     RECT  42.768 40.595 43.212 46.787 ;
     RECT  52.368 46.693 52.392 47.027 ;
     RECT  45.264 45.347 45.912 47.075 ;
     RECT  56.016 42.755 56.712 47.173 ;
     RECT  47.232 46.117 47.256 47.219 ;
     RECT  59.1 43.523 59.412 47.269 ;
     RECT  53.568 46.117 54.012 47.557 ;
     RECT  45.504 47.075 45.912 47.603 ;
     RECT  56.016 47.173 56.856 47.603 ;
     RECT  53.568 47.557 54.168 48.131 ;
     RECT  48.3 43.283 48.612 48.229 ;
     RECT  56.4 47.603 56.856 48.421 ;
     RECT  58.128 47.269 59.412 48.421 ;
     RECT  56.4 48.421 59.412 50.101 ;
     RECT  52.464 48.997 52.488 50.291 ;
     RECT  48.192 48.229 48.612 50.963 ;
     RECT  53.7 48.131 54.168 51.829 ;
     RECT  55.776 50.101 59.412 52.499 ;
     RECT  52.992 51.829 54.168 52.547 ;
     RECT  53.7 52.547 54.168 53.027 ;
     RECT  56.4 52.499 59.412 53.075 ;
     RECT  58.992 53.075 59.412 53.267 ;
     RECT  56.4 53.075 57.864 53.557 ;
     RECT  56.16 53.557 57.864 53.603 ;
     RECT  56.16 53.603 56.712 53.941 ;
     RECT  59.1 53.267 59.412 54.709 ;
     RECT  55.776 53.941 56.712 54.755 ;
     RECT  58.992 54.709 59.412 55.427 ;
     RECT  57.84 53.603 57.864 55.907 ;
     RECT  56.16 54.755 56.712 56.051 ;
     RECT  2.4 2.151 2.712 62.649 ;
     RECT  5.1 36.563 5.412 62.649 ;
     RECT  7.8 2.151 8.112 62.649 ;
     RECT  10.5 41.699 10.812 62.649 ;
     RECT  13.2 33.875 13.512 62.649 ;
     RECT  15.9 39.827 16.212 62.649 ;
     RECT  18.6 42.563 18.912 62.649 ;
     RECT  21.3 40.835 21.612 62.649 ;
     RECT  24 42.227 24.312 62.649 ;
     RECT  26.7 33.683 27.012 62.649 ;
     RECT  29.4 42.755 29.712 62.649 ;
     RECT  32.1 43.811 32.412 62.649 ;
     RECT  34.8 41.123 35.112 62.649 ;
     RECT  37.5 43.523 37.812 62.649 ;
     RECT  40.2 2.151 40.512 62.649 ;
     RECT  42.9 46.787 43.212 62.649 ;
     RECT  45.6 47.603 45.912 62.649 ;
     RECT  48.3 50.963 48.612 62.649 ;
     RECT  51 45.155 51.312 62.649 ;
     RECT  53.7 53.027 54.012 62.649 ;
     RECT  56.4 56.051 56.712 62.649 ;
     RECT  59.1 55.427 59.412 62.649 ;
     RECT  61.8 2.151 62.112 62.649 ;
     RECT  2.4 62.649 2.52 62.663 ;
     RECT  5.1 62.649 5.22 62.663 ;
     RECT  7.8 62.649 7.92 62.663 ;
     RECT  10.5 62.649 10.62 62.663 ;
     RECT  13.2 62.649 13.32 62.663 ;
     RECT  15.9 62.649 16.02 62.663 ;
     RECT  18.6 62.649 18.72 62.663 ;
     RECT  21.3 62.649 21.42 62.663 ;
     RECT  24 62.649 24.12 62.663 ;
     RECT  26.7 62.649 26.82 62.663 ;
     RECT  29.4 62.649 29.52 62.663 ;
     RECT  32.1 62.649 32.22 62.663 ;
     RECT  34.8 62.649 34.92 62.663 ;
     RECT  37.5 62.649 37.62 62.663 ;
     RECT  40.2 62.649 40.32 62.663 ;
     RECT  42.9 62.649 43.02 62.663 ;
     RECT  45.6 62.649 45.72 62.663 ;
     RECT  48.3 62.649 48.42 62.663 ;
     RECT  51 62.649 51.12 62.663 ;
     RECT  53.7 62.649 53.82 62.663 ;
     RECT  56.4 62.649 56.52 62.663 ;
     RECT  59.1 62.649 59.22 62.663 ;
     RECT  61.8 62.649 61.92 62.663 ;
  END
END ot_qfd_vm_su_read_control
END LIBRARY
